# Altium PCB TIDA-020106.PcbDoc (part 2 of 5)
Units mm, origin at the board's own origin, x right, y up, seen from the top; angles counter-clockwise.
Board outline 158.53 x 83.25 mm, 6 copper layers (Top Layer, GND, Power, Sig4, GND (Mid4), Bottom Layer), stack 1.59 mm thick; 407 components, 254 nets, 1274 pads, 2396 vias.
Unrouted connection lines stored in the file: 294.

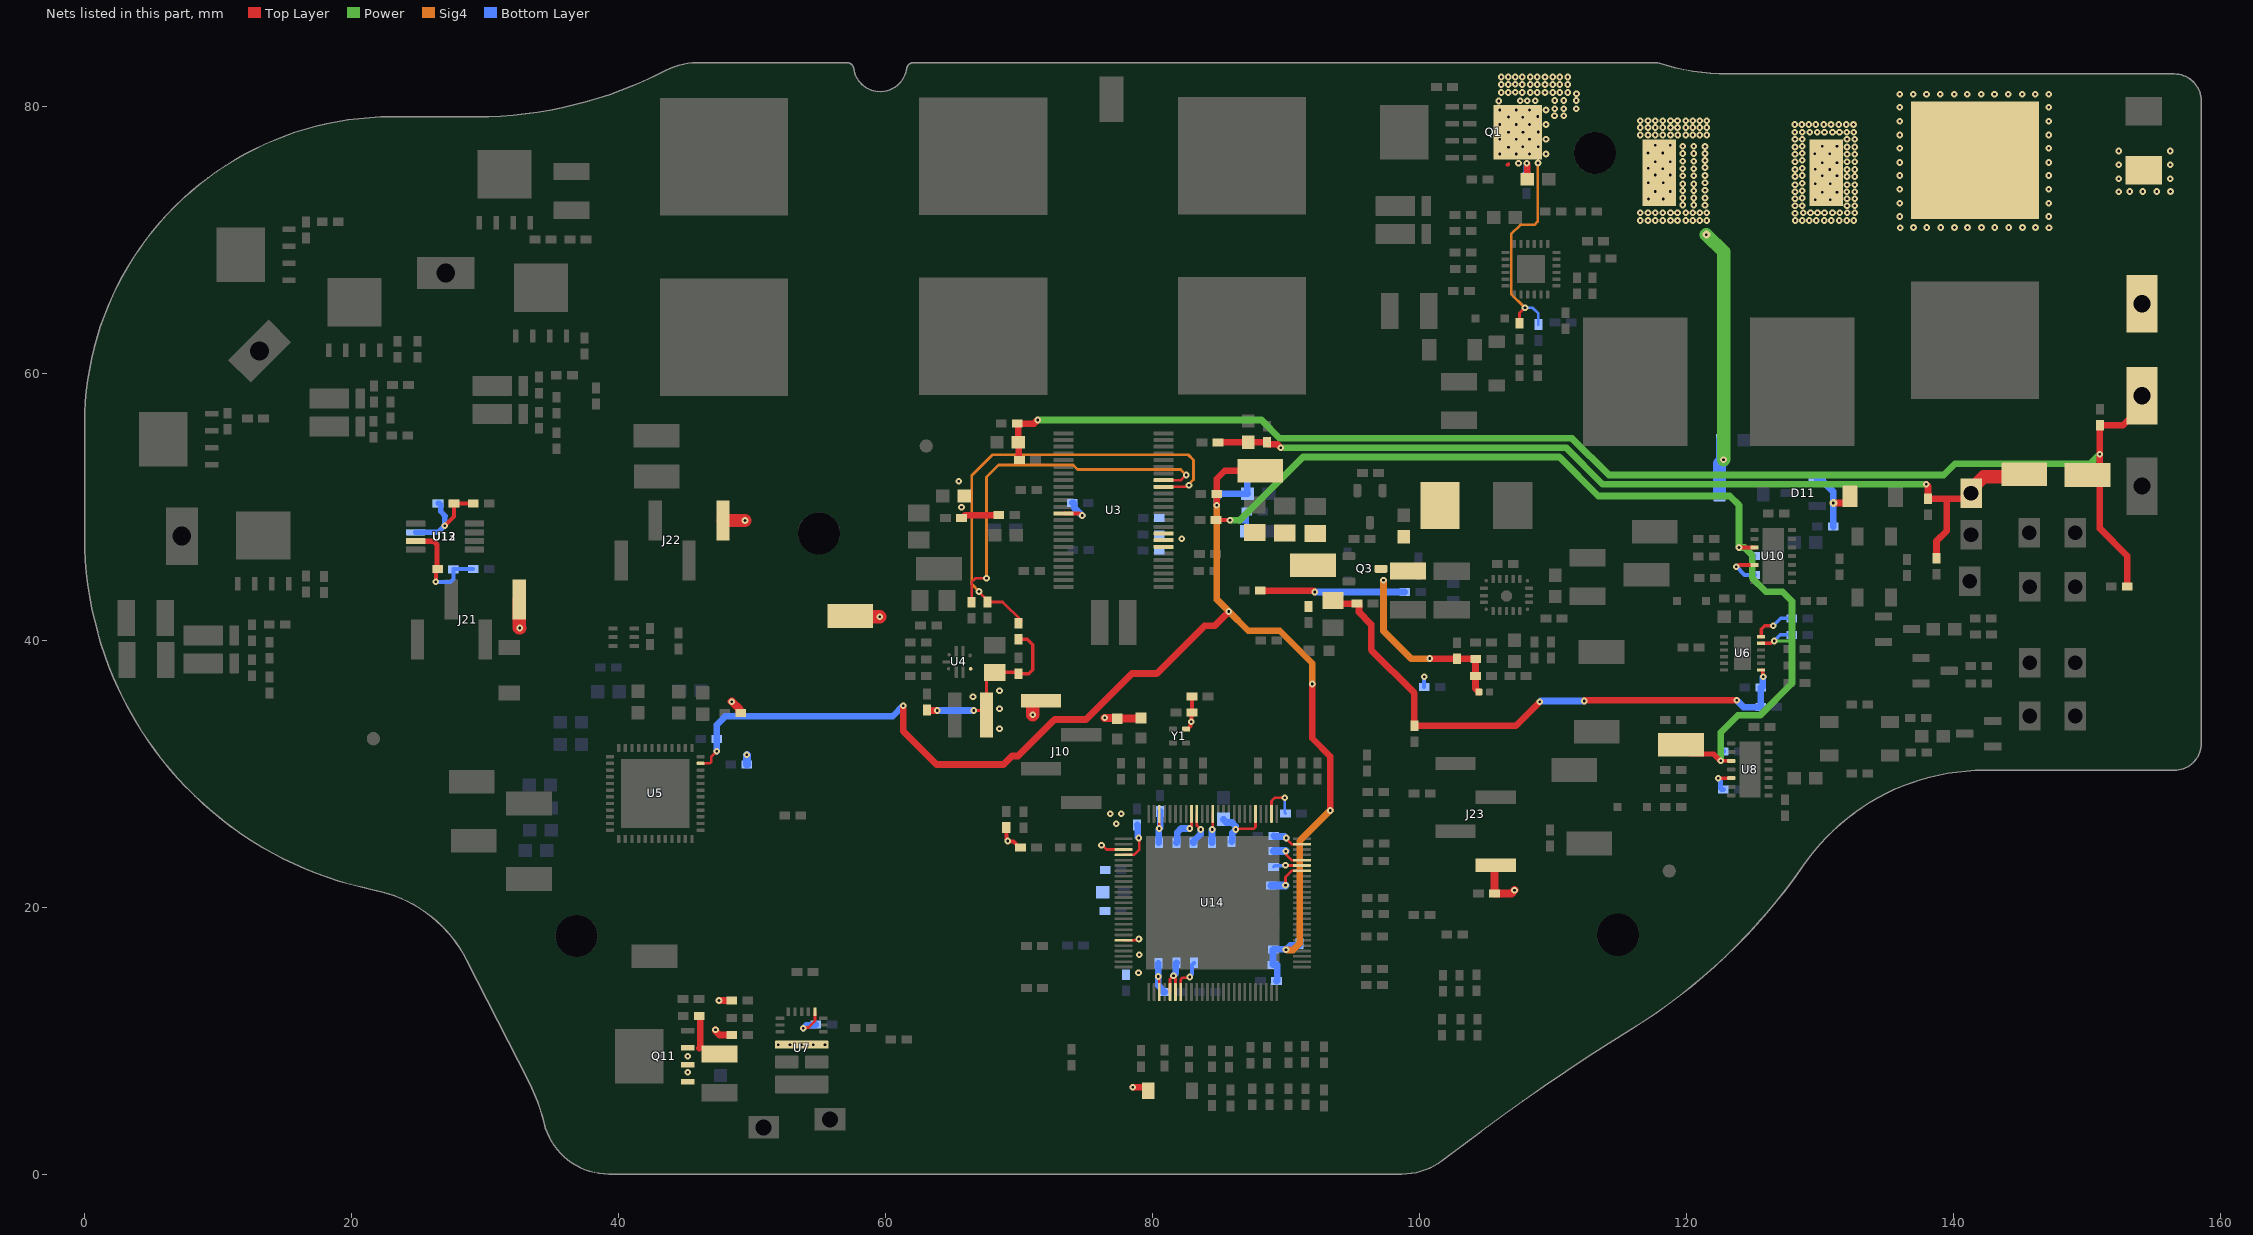
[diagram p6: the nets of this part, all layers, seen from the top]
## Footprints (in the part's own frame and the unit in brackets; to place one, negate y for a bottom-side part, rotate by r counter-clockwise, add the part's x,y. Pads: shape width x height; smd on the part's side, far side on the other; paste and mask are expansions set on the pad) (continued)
RYT0009A-MFG [mm]
  rrect40% 0.875x0.25 smd paste+0 mask+0: 1(-0.763,0.25) 2(-0.763,-0.25) 5(0.763,-0.25) 6(0.763,0.25)
  round 0.255 smd paste+0 mask+0: 3(-0.509,-0.828)
  round 0.278 smd paste+0 mask+0: 4(0.487,-0.787)
  round 0.26 smd paste+0 mask+0: 7(0.537,0.787)
  rrect40% 0.25x0.65 smd paste+0 mask+0: 8(0,0.95)
  round 0.242 smd paste+0 mask+0: 9(-0.509,0.828)
  Top Layer region: -1.2,-0.825 -1.193,-0.85 -1.175,-0.868 -1.15,-0.875 -1.15,-0.875 -0.675,-0.875 -0.656,-0.879 -0.64,-0.89 -0.629,-0.906 -0.625,-0.925 -0.625,-0.925 -0.625,-1.225 -0.618,-1.25 -0.6,-1.268 -0.575,-1.275 -0.575,-1.275 -0.425,-1.275 -0.406,-1.271 -0.39,-1.26 -0.379,-1.244 -0.375,-1.225 -0.375,-1.225 -0.375,-0.912 -0.368,-0.887 -0.35,-0.868 -0.35,-0.868 -0.337,-0.857 -0.328,-0.842 -0.325,-0.825 -0.325,-0.825 -0.325,-0.675 -0.329,-0.656 -0.34,-0.64 -0.356,-0.629 -0.375,-0.625 -0.375,-0.625 -1.15,-0.625 -1.169,-0.629 -1.185,-0.64 -1.196,-0.656 -1.2,-0.675 -1.2,-0.675
  Top Layer region: 1.2,0.825 1.193,0.85 1.175,0.868 1.15,0.875 1.15,0.875 0.675,0.875 0.656,0.879 0.64,0.89 0.629,0.906 0.625,0.925 0.625,0.925 0.625,1.225 0.618,1.25 0.6,1.268 0.575,1.275 0.575,1.275 0.425,1.275 0.406,1.271 0.39,1.26 0.379,1.244 0.375,1.225 0.375,1.225 0.375,0.675 0.379,0.656 0.39,0.64 0.406,0.629 0.425,0.625 0.425,0.625 1.15,0.625 1.169,0.629 1.185,0.64 1.196,0.656 1.2,0.675 1.2,0.675
  Top Layer region: -1.2,0.825 -1.193,0.85 -1.175,0.868 -1.15,0.875 -1.15,0.875 -0.675,0.875 -0.656,0.879 -0.64,0.89 -0.629,0.906 -0.625,0.925 -0.625,0.925 -0.625,1.225 -0.618,1.25 -0.6,1.268 -0.575,1.275 -0.575,1.275 -0.425,1.275 -0.406,1.271 -0.39,1.26 -0.379,1.244 -0.375,1.225 -0.375,1.225 -0.375,0.675 -0.379,0.656 -0.39,0.64 -0.406,0.629 -0.425,0.625 -0.425,0.625 -1.15,0.625 -1.169,0.629 -1.185,0.64 -1.196,0.656 -1.2,0.675 -1.2,0.675
  Top Layer region: 1.2,-0.825 1.193,-0.85 1.175,-0.868 1.15,-0.875 1.15,-0.875 0.675,-0.875 0.656,-0.879 0.64,-0.89 0.629,-0.906 0.625,-0.925 0.625,-0.925 0.625,-1.225 0.618,-1.25 0.6,-1.268 0.575,-1.275 0.575,-1.275 0.425,-1.275 0.406,-1.271 0.39,-1.26 0.379,-1.244 0.375,-1.225 0.375,-1.225 0.375,-0.912 0.372,-0.894 0.363,-0.879 0.35,-0.868 0.35,-0.868 0.337,-0.857 0.328,-0.842 0.325,-0.825 0.325,-0.825 0.325,-0.675 0.329,-0.656 0.34,-0.64 0.356,-0.629 0.375,-0.625 0.375,-0.625 1.15,-0.625 1.169,-0.629 1.185,-0.64 1.196,-0.656 1.2,-0.675 1.2,-0.675
  silkscreen extent -1.92,-1.68 1.05,1.68, body extent -1.3,-1.38 1.3,1.38, height 0.25
RZT0020A-MFG [mm]
  round 0.259 smd paste+0 mask+0: 1(-1.069,1.519) 7(-1.069,-1.569) 11(1.069,-1.569) 17(1.069,1.519)
  rrect40% 0.6x0.25 smd paste+0 mask+0: 2(-1.2,1) 3(-1.2,0.5) 4(-1.2,0) 5(-1.2,-0.5) 6(-1.2,-1) 12(1.2,-1) 13(1.2,-0.5) 14(1.2,0) 15(1.2,0.5) 16(1.2,1)
  rrect40% 0.25x0.6 smd paste+0 mask+0: 8(-0.55,-1.7) 9(-0.05,-1.7) 10(0.5,-1.7) 18(0.5,1.7) 19(-0.05,1.7) 20(-0.55,1.7)
  round 0.855 smd paste-1000 mask+0: 21(-0.075,0)
  Top Layer region: -0.55,1 -0.543,1.025 -0.525,1.043 -0.5,1.05 -0.5,1.05 0.099,1.05 0.124,1.044 0.142,1.026 0.149,1.001 0.149,1.001 0.178,0.897 0.252,0.819 0.354,0.785 0.354,0.785 0.377,0.777 0.394,0.759 0.4,0.735 0.4,0.735 0.4,-0.735 0.394,-0.759 0.377,-0.777 0.354,-0.785 0.354,-0.785 0.252,-0.819 0.178,-0.897 0.149,-1.001 0.149,-1.001 0.142,-1.026 0.124,-1.044 0.099,-1.05 0.099,-1.05 -0.249,-1.05 -0.274,-1.044 -0.292,-1.026 -0.299,-1.001 -0.299,-1.001 -0.328,-0.897 -0.402,-0.819 -0.504,-0.785 -0.504,-0.785 -0.527,-0.777 -0.544,-0.759 -0.55,-0.735 -0.55,-0.735
  Top Layer region: 1.45,1.375 1.469,1.379 1.485,1.39 1.496,1.406 1.5,1.425 1.5,1.425 1.5,1.575 1.496,1.594 1.485,1.61 1.469,1.621 1.45,1.625 1.45,1.625 1.275,1.625 1.237,1.633 1.204,1.654 1.183,1.687 1.175,1.725 1.175,1.725 1.175,1.95 1.171,1.969 1.16,1.985 1.144,1.996 1.125,2 1.125,2 0.975,2 0.956,1.996 0.94,1.985 0.929,1.969 0.925,1.95 0.925,1.95 0.925,1.425 0.929,1.406 0.94,1.39 0.956,1.379 0.975,1.375 0.975,1.375
  Top Layer region: 1.45,-1.375 1.469,-1.379 1.485,-1.39 1.496,-1.406 1.5,-1.425 1.5,-1.425 1.5,-1.575 1.496,-1.594 1.485,-1.61 1.469,-1.621 1.45,-1.625 1.45,-1.625 1.275,-1.625 1.237,-1.633 1.204,-1.654 1.183,-1.687 1.175,-1.725 1.175,-1.725 1.175,-1.95 1.171,-1.969 1.16,-1.985 1.144,-1.996 1.125,-2 1.125,-2 0.975,-2 0.956,-1.996 0.94,-1.985 0.929,-1.969 0.925,-1.95 0.925,-1.95 0.925,-1.425 0.929,-1.406 0.94,-1.39 0.956,-1.379 0.975,-1.375 0.975,-1.375
  Top Layer region: -1.45,-1.375 -1.469,-1.379 -1.485,-1.39 -1.496,-1.406 -1.5,-1.425 -1.5,-1.425 -1.5,-1.575 -1.496,-1.594 -1.485,-1.61 -1.469,-1.621 -1.45,-1.625 -1.45,-1.625 -1.275,-1.625 -1.237,-1.633 -1.204,-1.654 -1.183,-1.687 -1.175,-1.725 -1.175,-1.725 -1.175,-1.95 -1.171,-1.969 -1.16,-1.985 -1.144,-1.996 -1.125,-2 -1.125,-2 -0.975,-2 -0.956,-1.996 -0.94,-1.985 -0.929,-1.969 -0.925,-1.95 -0.925,-1.95 -0.925,-1.425 -0.929,-1.406 -0.94,-1.39 -0.956,-1.379 -0.975,-1.375 -0.975,-1.375
  Top Layer region: -1.45,1.375 -1.469,1.379 -1.485,1.39 -1.496,1.406 -1.5,1.425 -1.5,1.425 -1.5,1.575 -1.493,1.6 -1.475,1.618 -1.45,1.625 -1.45,1.625 -1.275,1.625 -1.237,1.633 -1.204,1.654 -1.183,1.687 -1.175,1.725 -1.175,1.725 -1.175,1.95 -1.168,1.975 -1.15,1.993 -1.125,2 -1.125,2 -0.975,2 -0.956,1.996 -0.94,1.985 -0.929,1.969 -0.925,1.95 -0.925,1.95 -0.925,1.425 -0.929,1.406 -0.94,1.39 -0.956,1.379 -0.975,1.375 -0.975,1.375
  silkscreen extent -2.17,-2.22 1.73,2.22, body extent -1.6,-2.1 1.6,2.1, height 0.25
SMB-Bi [mm] "Molded Diode, 2-Leads, Body 5.4x3.6mm, IPC Medium Density, based on OnSemi component dimensions"
  rect 2.159x2.743 smd: 1(-2.21,0) 2(2.21,0)
  silkscreen extent -3.18,-1.99 3.18,1.99, body extent -2.65,-1.85 2.65,1.85, height 2.26
SOD-123 [mm] "On Semi recommended land pattern"
  rect 0.915x1.22 smd: 1(-1.637,0) 2(1.637,0)
  silkscreen extent -2.74,-1.17 2.03,1.17, body extent -1.93,-0.9 1.93,0.9, height 1.35
SOD-323 [mm] "NXP recommended land pattern"
  rect 0.6x0.6 smd paste-0.05: 1(-1.1,0) 2(1.1,0)
  silkscreen extent -2.06,-0.86 1.53,0.86, body extent -1.3,-0.67 1.3,0.68, height 1.1
SOT-23 [mm] "SOT23, 3-Leads, Body 2.9x1.3mm, Pitch 0.95mm, Lead Span 2.5mm, IPC Medium Density"
  rrect50% 1x0.6 smd: 1(-1.2,0.95) 2(-1.2,-0.95) 3(1.2,0)
  silkscreen extent -1.62,-1.5 0.7,1.5, body extent -1.16,-1.45 1.21,1.45, height 1
Testpoint_Keystone_Miniature [mil] "Miniature SMT test point"
  rect 135x70 smd: 1(0,0)
  silkscreen extent -78,-46 78,45, body extent -52,-20 52,20, height 61
TI_Stacked_Overlay_Small [mm]
  silkscreen extent -10.63,-2.49 10.63,2.49
VAK0015A-MFG [mm]
  rrect40% 0.65x0.25 smd paste+0 mask+0: 1(-1.625,2.375) 2(-1.625,1.875) 3(-1.625,1.375) 8(1.625,1.375) 9(1.625,1.875) 10(1.625,2.375)
  rrect17% 4x0.6 smd paste-1000 mask-1000: 4(0,0.4)
  rrect20% 1.75x1 smd paste-1000 mask-1000: 5(-1.125,-0.9) 7(1.125,-0.9)
  rrect15% 4x1.35 smd paste-1000 mask-1000: 6(0,-2.575)
  rrect40% 0.25x0.65 smd paste+0 mask+0: 11(1,2.875) 12(0.5,2.875) 13(0,2.875) 14(-0.5,2.875) 15(-1,2.875)
  silkscreen extent -2.62,2.25 1.8,3.05, body extent -2.1,-3.35 2.1,3.3, height 0.25
WE-HCM_1390 [mm] "SMD, Body 12.5x13mm"
  rect 2.5x5 smd: 1(-6.25,0) 2(6.25,0)
  silkscreen extent -6.5,-6.75 6.5,6.75, body extent -6.5,-6.75 6.5,6.75, height 9.5
WE-LHMI_7050 [mm] "Wurth"
  rect 2.95x3.5 smd: 1(-2.725,0) 2(2.725,0)
  silkscreen extent -3.55,-3.55 3.55,3.55, body extent -3.8,-3.45 3.8,3.45, height 5
WE-MAPI_3012 [mm] "SMD, 2-Leads, Body 3.2x3.2mm"
  rect 1.3x3.4 smd: 1(-1.05,0) 2(1.05,0)
  silkscreen extent -0.1,-1.6 0.1,1.6, body extent -1.5,-1.5 1.5,1.5, height 1.2
WEEE_Minimum [mm] "WEEElie bin"
  silkscreen extent -2.42,-4.38 2.52,2.65
Wurth_61000418221 [mm] "Header, 2.54mm, 4x1, SMT"
  rect 3x1 smd: 1(-1.5,3.81) 2(1.5,1.27) 3(-1.5,-1.27) 4(1.5,-3.81)
  silkscreen extent -1.27,-5.08 1.27,5.4, body extent -2.5,-5.08 2.5,5.08, height 9.29

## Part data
C1 C2 C13 C35 C41 C55 C59 C66 C70 C71 C81 C82 C84 C85 C86 C87 C88 C90 C94 C118 C120 C148: library part CMP-0860997-1, "CAP, CERM, 1000 pF, 50 V,+/- 10%, X8R, AEC-Q200 Grade 0, 0402", Cap_Case=0402, Manufacturer=TDK, TempCo=X8R, Tolerance_%=10%, Value2=50V, ValueDisplayed=1000pF
C3 C4 C11 C15 C17 C20 C34 C36 C37 C38 C39 C42 C43 C44 C45 C46 C47 C58 C83 C89 C91 C92 C93 C98 C99 C100 C101 C103 C105 C107 C109 C110 C111 C112 C113 C114 C121 C122 C125 C126 C127 C128 C129 C130 C131 C132 C139 C140 C141 C142 C143 C144 C145 C146 C147: library part CMP-0006356-2, "CAP, CERM, 0.1 uF, 50 V, +/- 10%, X7R, AEC-Q200 Grade 1, 0402", Cap_Case=0402, Manufacturer=MuRata, Supplier Part Number 1=490-10672-1-ND, TempCo=X7R, Tolerance_%=10%, Value1=Unknown, Value2=50V, ValueDisplayed=0.1uF
C5 C6 C21 C22 C25 C61 C75 C76 C96: library part CMP-0009182-2, "CAP, CERM, 4.7 uF, 100 V, +/- 10%, X7S, 1210", Cap_Case=1210, Manufacturer=MuRata, Supplier Part Number 1=81-GRM32DC72A475KE1L, TempCo=X7S, Tolerance_%=10%, Value1=Unknown, Value2=100V, ValueDisplayed=4.7uF
C7 C9 C10 C23 C24 C26 C97 C102 C106: library part CMP-0860999-1, "CAP, CERM, 0.1 µF, 100 V,+/- 10%, X8L, AEC-Q200 Grade 0, 0603", Cap_Case=0603, Manufacturer=MuRata, TempCo=X8L, Tolerance_%=10%, Value2=100V, ValueDisplayed=0.1µF
C8 C60 C73 C74: library part CMP-0011277-1, "CAP, AL, 330 uF, 100 V, +/- 20%, SMD", Cap_Case=MN0, Manufacturer=Chemi-Con, Tolerance_%=20%, Value1=Unknown, Value2=100V, ValueDisplayed=330uF
C12 C16 C68: library part CMP-0008815-2, "CAP, CERM, 1 uF, 100 V, +/- 10%, X7R, AEC-Q200 Grade 1, 1206", Cap_Case=1206, Manufacturer=MuRata, Supplier Part Number 1=GCM31CR72A105KA03L-ND, TempCo=X7R, Tolerance_%=10%, Value1=Unknown, Value2=100V, ValueDisplayed=1uF
C14 C18: library part CMP-0006333-1, "CAP, CERM, 0.01 uF, 100 V, +/- 10%, X7S, AEC-Q200 Grade 1, 0402", Cap_Case=0402, Manufacturer=TDK, Supplier Part Number 1=445-6910-1-ND, TempCo=X7S, Tolerance_%=10%, Value1="0.410191 ohm", Value2=100V, ValueDisplayed=0.01uF
C19: library part CMP-0006331-2, "CAP, CERM, 0.068 uF, 50 V, +/- 10%, X7R, AEC-Q200 Grade 1, 0402", Cap_Case=0402, Manufacturer=TDK, Supplier Part Number 1=445-6898-1-ND, TempCo=X7R, Tolerance_%=10%, Value1="0.05606 ohm", Value2=50V, ValueDisplayed=0.068uF
C27 C31 C32 C33 C40 C56 C57: library part CMP-0008305-2, "CAP, CERM, 22 uF, 25 V, +/- 20%, X5R, 0805", Cap_Case=0805, Manufacturer=MuRata, Supplier Part Number 1=490-10749-1-ND, TempCo=X5R, Tolerance_%=20%, Value1=Unknown, Value2=25V, ValueDisplayed=22uF
C28: library part CMP-0011274-1, "CAP, AL, 100 uF, 100 V, +/- 20%, SMD", Cap_Case=LH0, Manufacturer=Chemi-Con, Tolerance_%=20%, Value1=Unknown, Value2=100V, ValueDisplayed=100uF
C29 C63 C64 C65 C67 C69 C72 C77: library part CMP-0123897-1, "Auto Grade Capacitor, 0603, X7R, 25V, 1uF, ±10%", Digikey Part Number=2679-AGC0603X7R250-105KXPTR-ND, Manufacturer=Venkel, Operating Temperature Range="-55°C to +125°C", TempCo=15%, Temperature Characteristic=X7R, Tolerance_%=10%, ValueDisplayed=1uF
C30: library part CMP-0122034-1, "10 pF ±10% 50V Ceramic Capacitor X7R 0402 (1005 Metric)", Digikey Part Number=399-C0402C100K5RAC7867CT-ND, Manufacturer=KEMET, Operating Temperature Range="-55°C to +125°C", TempCo=15%, Temperature Characteristic=X7R, Tolerance_%=10%, ValueDisplayed=10pF
C48 C49 C50 C51 C52 C123 C124: library part CMP-0007497-1, "CAP, CERM, 10 uF, 10 V, +/- 20%, X7R, 0603", Cap_Case=0603, Manufacturer=MuRata, Supplier Part Number 1=81-GRM188Z71A106MA3D, TempCo=X7R, Tolerance_%=20%, Value1=Unknown, Value2=10V, ValueDisplayed=10uF
C53: library part CMP-0084284-1, "CAP, CERM, 2.2 µF, 10 V,+/- 10%, X7R, AEC-Q200 Grade 1, 0603", Cap_Case=0603, Manufacturer=MuRata, TempCo=X7R, Tolerance_%=10%, Value2=10V, ValueDisplayed=2.2µF
C54 C116 C117: library part CMP-0007498-2, "CAP, CERM, 4.7 uF, 10 V, +/- 20%, X7R, 0603", Cap_Case=0603, Manufacturer=MuRata, TempCo=X7R, Tolerance_%=20%, Value1=Unknown, Value2=10V, ValueDisplayed=4.7uF
C62: library part CMP-0007007-3, "CAP, CERM, 10 uF, 25 V, +/- 20%, X5R, 0603", Cap_Case=0603, Manufacturer=TDK, PartNumber=C1608X5R1E106M080AC, Supplier Part Number 1=445-9015-1-ND, TempCo=X5R, Tolerance_%=20%, Value1="0.004639 ohm", Value2=25V, ValueDisplayed=10uF
C78 C79 C80: library part CMP-0860801-1, "CAP, CERM, 470 pF, 50 V,+/- 10%, X7R, AEC-Q200 Grade 1, 0402", Cap_Case=0402, Manufacturer=MuRata, TempCo=X7R, Tolerance_%=10%, Value2=50V, ValueDisplayed=470pF
C95: library part CMP-0007095-1, "CAP, CERM, 0.33 uF, 50 V, +/- 10%, X7R, AEC-Q200 Grade 1, 0603", Cap_Case=0603, Manufacturer=TDK, Supplier Part Number 1=445-174426-1-ND, TempCo=X7R, Tolerance_%=10%, Value1="0.01584 ohm", Value2=50V, ValueDisplayed=0.33uF
C104 C108: library part CMP-0079247-1, "CAP, CERM, 4700 pF, 100 V,+/- 10%, X7R, AEC-Q200 Grade 1, 0603", Cap_Case=0603, Manufacturer=MuRata, Supplier Part Number 1=490-4930-1-ND, TempCo=X7R, Tolerance_%=10%, Value2=100V, ValueDisplayed=4700pF
C133 C134 C135 C136 C137 C138: library part CMP-0081010-1, "CAP, CERM, 2.2 µF, 25 V,+/- 20%, X5R, 0402", Cap_Case=0402, Manufacturer=MuRata, Supplier Part Number 1=490-10457-1-ND, TempCo=X5R, Tolerance_%=20%, Value2=25V, ValueDisplayed=2.2µF
D1: library part CMP-0006055-3, "Diode, TVS, Bi, 51 V, 82.4 Vc, SMB", Manufacturer=Bourns, Value1=600W
D2 D6 D7: library part CMP-0079597-2, "Diode, Switching, 75 V, 0.15 A, AEC-Q101, SOD-323", Manufacturer="Diodes Inc.", Value1=0.15A, Value2=1.25V
D3 D12: library part CMP-0080760-2, "Diode, Schottky, 100 V, 0.15 A, AEC-Q101, SOD-123", Manufacturer=Vishay-Semiconductor, Value1=0.15A, Value2=1V
D4: library part CMP-0078478-1, "LED, Green, SMD", Color=Green, Manufacturer=Lite-On, Power_TotalModule=75mW, Supplier Part Number 1=160-1446-1-ND, Value1=0.075W, Value2=2V
D5: library part CMP-0125988-1, "Automotive, dual, 3-pF, ±24-V, ±30-kV ESD protection diode for in-vehicle networks 3-SOT-23 -55 to 150", Breakdown Voltage=25.5V, Clamping Voltage=37V, Digikey Part Number=296-ESD2CAN24DBZRQ1CT-ND, Manufacturer="Texas Instruments", Mouser Part Number=595-ESD2CAN24DBZRQ1, Operating Temperature Range="-55°C to +150°C", ValueDisplayed=3pF
D8: library part CMP-0002891-1, "LED, Green, SMD", Color=green, Manufacturer=Lite-On, Supplier Part Number 1=160-1888-1-ND, Value1=W, Value2=3.2V
D9: library part CMP-0002950-1, "LED, Red, SMD", Color=Red, Manufacturer=Lite-On, Power_TotalModule=75mW, Supplier Part Number 1=160-1447-1-ND, Value1=0.075W, Value2=2V
D10: library part CMP-0128583-1, "Zener Diode Single 62V 5% 185Ohm 500mW 2-Pin SOD-123 T/R", Digikey Part Number=MMSZ5265B-TP-ND, Manufacturer=MCC, Max Reverse Leakage Current=0.1uA, Mouser Part Number=833-MMSZ5265B-TP, Operating Temperature Range="-65°C to +150°C", Power_W=500mW
D11: library part CMP-0126395-1, "Zener Diode 27 V 250 mW ±5% Surface Mount SOT-23-3", Digikey Part Number=296-BZX84C27VDBZRCT-ND, Manufacturer="Texas Instruments", Max Reverse Leakage Current=0.03uA, Mouser Part Number=595-BZX84C27VDBZR, Operating Temperature Range="-55°C to +150°C", Power_W=250mW
D13: library part CMP-0005829-3, "Diode, Zener, 10 V, 200 mW, SOD-323", Manufacturer="Diodes Inc.", Power_W=200mW, Value1=0.2W
FID1 FID2 FID3: library part CMP-0077181-1, "Fiducial mark.  There is nothing to buy or mount.", Manufacturer=N/A
J10 J21 J22 J23: library part CMP-0054788-1, "Header, 2.54mm, 4x1, Gold, SMT", Color=Black, Manufacturer="Wurth Elektronik", Supplier Part Number 1=732-5365-ND
L1: library part CMP-0063911-1, "Inductor, Shielded Drum Core, Ferrite, 250 nH, 50 A, 0.000165 ohm, SMD", Manufacturer="Wurth Elektronik", Supplier Part Number 1=732-3005-1-ND, Value1="0.000165 ohm", Value2=50A, ValueDisplayed=250nH
L2: library part CMP-0064107-1, "Inductor, Shielded Drum Core, Powdered Iron, 3.3 uH, 6 A, 0.019 ohm, SMD", Manufacturer="Wurth Elektronik", Supplier Part Number 1=732-3353-1-ND, Value1="0.019 ohm", Value2=6A, ValueDisplayed=3.3uH
L3: library part CMP-0084500-1, "Inductor, Shielded, Metal Composite, 2.2 µH, 1.8 A, 0.115 ohm, SMD", Manufacturer="Wurth Elektronik", Value1="0.115 ohm", Value2=1.8A, ValueDisplayed=2.2µH
L4: library part CMP-0090842-1, "Power Inductor, shielded, composite, 1uH 20% tol, DCR 7.2mOhms, SRF 65MHz, Isat 4.8A, Irms 13A, AEC-Q200", Manufacturer=Coilcraft, Operating Temperature Range="to +165°C", Self Resonant Frequency=65MHz, Test Frequency=1MHz, Tolerance_%=20%
L5 L6: library part CMP-0062430-2, "Inductor, Ferrite, 100 uH, 0.15 A, 2 ohm, SMD", Manufacturer=TDK, Supplier Part Number 1=445-3959-1-ND, Value1="2 ohm", Value2=0.15A, ValueDisplayed=100uH
L7 L8 L10: library part CMP-0003235-1, "Ferrite Bead, 100 ohm @ 100 MHz, 1.2 A, 0402", Manufacturer="Wurth Elektronik", Supplier Part Number 1=732-2362-1-ND, Value1="0.09 ohm", Value2=1.2A, ValueDisplayed="100 ohm"
LBL1: library part CMP-0003625-1, "Thermal Transfer Printable Labels, 0.650\" W x 0.200\" H - 10,000 per roll", Manufacturer=Brady, Supplier Part Number 1=97C5133
Logo1: library part CMP-0074844-1
Logo2: library part CMP-0074838-1, "Texas Instrument Corporate Signature"
Logo3: library part CMP-0074847-1, "FCC_disclaimer"
Logo4: library part CMP-0074769-1
LOGO5: library part CMP-0074837-1, "IEC 61010-1 Hot Surface Warning"
LOGO6: library part CMP-0074835-1, "IEC 61010-1 High Voltage Warning"
MP1 MP2 MP3 MP4: library part CMP-0125643-1, "M3 Pan Head Machine Screw Slotted Drive Nylon", Digikey Part Number=36-29344-ND, Manufacturer="Keystone Electronics", Mouser Part Number=534-29344, Operating Temperature Range=to
Q1 Q2 Q4 Q5 Q7 Q8 Q9 Q10 Q11: library part CMP-0086155-1, "MOSFET, N-CH, 80 V, 60 A, AEC-Q101, PowerPAK_SO-8L", Alternate Manufacturer=None, Manufacturer=Vishay-Siliconix, Value1="? ohm", Value2="36 nC"
Q3: library part CMP-0000613-1, "MOSFET, N-CH, 30 V, 4 A, AEC-Q101, SOT-23", Alternate Manufacturer=None, Manufacturer="Diodes Inc.", Supplier Part Number 1=DMN3053L-7DICT-ND, Value1=0, Value2="7.3 nC"
Q6: library part CMP-0049400-1, "Trans Digital BJT NPN/PNP 50V 100mA 250mW 6-Pin SOT-363 T/R", Collector Base Voltage=50V, Digikey Part Number=BCR22PNH6327XTSA1CT-ND, Manufacturer=Infineon, Mouser Part Number=726-BCR22PNH6327XTSA, Operating Temperature Range="to +150°C", Power_W=250mW, Unity Gain Freq=130MHz
Q12: library part CMP-0001041-2, "MOSFET, N-CH, 100 V, 0.7 A, AEC-Q101, SOT-23", Alternate Manufacturer=None, Manufacturer="Diodes Inc.", Supplier Part Number 1=ZXMN10A07FCT-ND, Value2="2.9 nC"
R1 R2 R12 R13 R21 R27 R31 R32 R33 R48 R52 R56 R69 R70 R74 R75 R87 R120 R122 R124 R126 R155: library part CMP-0025950-3, "RES, 100 k, 1%, 0.063 W, AEC-Q200 Grade 0, 0402", Manufacturer=Vishay-Dale, Power_W=63mW, Supplier Part Number 1=541-100KLCT-ND, TempCo="100 ppm/C", Tolerance_%=1%, Value2=0.063W, Value_Code=100k
R3 R4: library part CMP-0026510-2, "RES, 69.8 k, 1%, 0.063 W, AEC-Q200 Grade 0, 0402", Manufacturer=Vishay-Dale, Power_W=63mW, Supplier Part Number 1=541-69.8KLCT-ND, TempCo="100 ppm/C", Tolerance_%=1%, Value2=0.063W, Value_Code=69k8, ValueDisplayed=69.8k
R5 R6 R15 R62 R91 R92 R102 R104 R112 R114 R130 R136 R147 R148 R149 R150 R153 R156: library part CMP-0025958-3, "RES, 10.0 k, 1%, 0.063 W, AEC-Q200 Grade 0, 0402", Manufacturer=Vishay-Dale, Power_W=63mW, Supplier Part Number 1=541-10.0KLCT-ND, TempCo="100 ppm/C", Tolerance_%=1%, Value2=0.063W, Value_Code=10k0, ValueDisplayed=10.0k
R7: library part CMP-0123675-1, "1 mOhms ±1% 7W Chip Resistor Wide 1612 (3831 Metric), 1216 Current Sense, Moisture Resistant", Digikey Part Number=4423-BVN-M-R001-1.0CT-ND, Manufacturer=Isabellenhuette, Operating Temperature Range="-65°C to +170°C", Power_W=7W, TempCo=50ppm/°C, Tolerance_%=1%
R8 R9 R22 R23 R25 R29 R30 R37 R38 R39 R40 R41 R45 R49 R50 R51 R53 R54 R55 R57 R58 R66 R67 R72 R73 R97 R98 R99 R105 R109 R115 R128 R129 R144 R145 R146: library part CMP-0026822-3, "RES, 0, 5%, 0.063 W, AEC-Q200 Grade 0, 0402", Manufacturer=Vishay-Dale, Power_W=63mW, Supplier Part Number 1=541-0.0JCT-ND, TempCo="200 ppm/C", Tolerance_%=5%, Value2=0.063W, Value_Code=0000, ValueDisplayed=0
R10 R17 R19 R24 R26 R28 R36 R95 R119 R121 R123 R125 R131 R134 R151 R152 R154: library part CMP-0026071-3, "RES, 1.00 k, 1%, 0.063 W, AEC-Q200 Grade 0, 0402", Manufacturer=Vishay-Dale, Power_W=63mW, Supplier Part Number 1=541-1.00KLCT-ND, TempCo="100 ppm/C", Tolerance_%=1%, Value2=0.063W, Value_Code=1k00, ValueDisplayed=1.00k
R11: library part CMP-0025948-2, "RES, 50, 1%, 0.125 W, AEC-Q200 Grade 1, 0402", Manufacturer="AT Ceramics", Power_W=125mW, Supplier Part Number 1=1284-1326-1-ND, TempCo="150 ppm/C", Tolerance_%=1%, Value2=0.125W, Value_Code=50R0, ValueDisplayed=50
R14: library part CMP-0026094-3, "RES, 1.74 k, 1%, 0.063 W, AEC-Q200 Grade 0, 0402", Manufacturer=Vishay-Dale, Power_W=63mW, Supplier Part Number 1=541-1.74KLCT-ND, TempCo="100 ppm/C", Tolerance_%=1%, Value2=0.063W, Value_Code=1k74, ValueDisplayed=1.74k
R16 R43 R84 R138 R139: library part CMP-0025951-3, "RES, 100, 1%, 0.063 W, AEC-Q200 Grade 0, 0402", Manufacturer=Vishay-Dale, Power_W=63mW, Supplier Part Number 1=541-100LCT-ND, TempCo="100 ppm/C", Tolerance_%=1%, Value2=0.063W, Value_Code=100R, ValueDisplayed=100
R18: library part CMP-0026555-2, "RES, 7.50 k, 1%, 0.063 W, AEC-Q200 Grade 0, 0402", Manufacturer=Vishay-Dale, Power_W=63mW, Supplier Part Number 1=541-7.50KLCT-ND, TempCo="100 ppm/C", Tolerance_%=1%, Value2=0.063W, Value_Code=7k50, ValueDisplayed=7.50k
R20: library part CMP-0026207-2, "RES, 26.1 k, 1%, 0.063 W, AEC-Q200 Grade 0, 0402", Manufacturer=Vishay-Dale, Power_W=63mW, Supplier Part Number 1=541-26.1KLCT-ND, TempCo="100 ppm/C", Tolerance_%=1%, Value2=0.063W, Value_Code=26k1, ValueDisplayed=26.1k
R34 R35: library part CMP-0026553-2, "RES, 7.15 k, 1%, 0.063 W, AEC-Q200 Grade 0, 0402", Manufacturer=Vishay-Dale, Power_W=63mW, Supplier Part Number 1=541-7.15KLCT-ND, TempCo="100 ppm/C", Tolerance_%=1%, Value2=0.063W, Value_Code=7k15, ValueDisplayed=7.15k
R42 R59 R89 R93 R94 R96 R101 R106 R107 R108 R111 R116 R117 R118 R133 R135 R137 R140 R141 R142 R143: library part CMP-0026908-3, "RES, 33, 5%, 0.063 W, AEC-Q200 Grade 0, 0402", Manufacturer=Vishay-Dale, Power_W=63mW, Supplier Part Number 1=541-33JCT-ND, TempCo="200 ppm/C", Tolerance_%=5%, Value2=0.063W, Value_Code=33R0, ValueDisplayed=33
R44: library part CMP-0026040-3, "RES, 16.2 k, 1%, 0.063 W, AEC-Q200 Grade 0, 0402", Manufacturer=Vishay-Dale, Power_W=63mW, Supplier Part Number 1=541-16.2KLCT-ND, TempCo="100 ppm/C", Tolerance_%=1%, Value2=0.063W, Value_Code=16k2, ValueDisplayed=16.2k
R46: library part CMP-0025956-3, "RES, 107 k, 1%, 0.063 W, AEC-Q200 Grade 0, 0402", Manufacturer=Vishay-Dale, Power_W=63mW, Supplier Part Number 1=541-107KLCT-ND, TempCo="100 ppm/C", Tolerance_%=1%, Value2=0.063W, Value_Code=107k
R47: library part CMP-0026027-3, "RES, 15.0 k, 1%, 0.063 W, AEC-Q200 Grade 0, 0402", Manufacturer=Vishay-Dale, Power_W=63mW, Supplier Part Number 1=541-15.0KLCT-ND, TempCo="100 ppm/C", Tolerance_%=1%, Value2=0.063W, Value_Code=15k0, ValueDisplayed=15.0k
R60 R63 R78 R79 R82 R83 R85 R86 R88 R90: library part CMP-0025963-3, "RES, 10.0, 1%, 0.063 W, AEC-Q200 Grade 0, 0402", Manufacturer=Vishay-Dale, Power_W=63mW, Supplier Part Number 1=541-10.0LCT-ND, TempCo="100 ppm/C", Tolerance_%=1%, Value2=0.063W, Value_Code=10R0, ValueDisplayed=10.0
R61 R80 R81: library part CMP-0126683-1, "0.5 mOhms ±1% 9W Chip Resistor Wide 1612 (3831 Metric), 1216 Current Sense, Moisture Resistant", Digikey Part Number=4423-BVN-Z-R0005-1.0CT-ND, Manufacturer=Isabellenhuette, Operating Temperature Range="-65°C to +170°C", Power_W=9W, TempCo=50ppm/°C, Tolerance_%=1%
R64 R65 R68: library part CMP-0078498-1, "RES, 3.00, 1%, 0.1 W, AEC-Q200 Grade 0, 0603", Manufacturer=Rohm, Power_W=100mW, Supplier Part Number 1=RHM3AYCT-ND, TempCo="100 ppm/C", Tolerance_%=1%, Value2=0.1W, Value_Code=3R00, ValueDisplayed=3.00
R71 R76 R77: library part CMP-0026035-3, "RES, 162, 1%, 0.063 W, AEC-Q200 Grade 0, 0402", Manufacturer=Vishay-Dale, Power_W=63mW, Supplier Part Number 1=541-162LCT-ND, TempCo="100 ppm/C", Tolerance_%=1%, Value2=0.063W, Value_Code=162R, ValueDisplayed=162
R100 R103 R110 R113: library part CMP-0026487-2, "RES, 60.4, 1%, 0.063 W, AEC-Q200 Grade 0, 0402", Manufacturer=Vishay-Dale, Power_W=63mW, Supplier Part Number 1=541-60.4LCT-ND, TempCo="100 ppm/C", Tolerance_%=1%, Value2=0.063W, Value_Code=60R4, ValueDisplayed=60.4
TP1 TP2 TP3 TP4 TP5 TP6 TP7 TP8 TP9 TP10 TP11 TP12 TP13 TP14 TP15 TP17 TP18 TP19 TP22 TP23: library part CMP-0055152-1, "Test Point, Miniature, SMT", Manufacturer=Keystone, Supplier Part Number 1=36-5015TR-ND
TP16: library part CMP-0055152-2, "Test Point, Miniature, SMT", Manufacturer="Keystone Electronics", Supplier Part Number 1=36-5015TR-ND
U1: library part CMP-0021701-1, "Ideal Diode Surge Stopper with Circuit breaker, overvoltage protection and fault output", Manufacturer="Texas Instruments", Max Supply Voltage=65V, Min Supply Voltage=3V, Nominal Supply Current=650-700uA, Operating Temperature Range="-40°C to +150°C"
U2: library part CMP-0096221-1, "3.5V to 65V Synchronous Step-Down Voltage Regulator", Manufacturer="Texas Instruments", Operating Temperature Range=to
U3: library part CMP-0095884-2, "Power Management IC For Safety-Relevant Applications HTSSOP48 5 Outputs 4 LDO and 1 Synchronous Buck-Boost Regulator", Manufacturer="Texas Instruments", Max Supply Voltage=28V, Min Supply Voltage=2.3V, Operating Temperature Range="-40°C to +150°C"
U4: library part CMP-0121948-1, "3-V to 18-V, 2-A, Automotive Low IQ Buck Converter with +165°C TJ", Digikey Part Number=296-TPS62902QRYTRQ1CT-ND, Manufacturer="Texas Instruments", Max Supply Voltage=18V, Min Supply Voltage=3V, Mouser Part Number=595-TPS62902QRYTRQ1, Nominal Supply Current=8mA, Operating Temperature Range="-40°C to +165°C", Output Voltage=0.4-5.5V, Switching Frequency=1/2.5MHz
U5: library part CMP-0127481-1, Manufacturer="Texas Instruments", Operating Temperature Range=to
U6: library part CMP-0123269-1, Manufacturer="Texas Instruments", Operating Temperature Range=to
U7: library part CMP-0121932-1, "Automotive 65-V H-Bridge Driver with Integrated Current Sense and Diagnostics", Manufacturer="Texas Instruments", Max Supply Voltage=65V, Min Supply Voltage=3V, Nominal Supply Current=3mA, Operating Temperature Range="-40°C to +150°C", Switching Frequency=0-100kHz
U8 U10: library part CMP-0013353-2, "Fault Protected CAN Transceiver with CAN FD, DMT0014A (VSON-14)", Alternate Manufacturer="Texas Instruments", Alternate PartNumber=TCAN1043HGDMTQ1
U9 U11: library part CMP-0127962-1, "Automotive 2-Channel, 48V ESD Protection Diode for In-Vehicle Networks", Breakdown Voltage=52V, Clamping Voltage=64V, Manufacturer="Texas Instruments", Operating Temperature Range="-55°C to +150°C", ValueDisplayed=1.9pF
U12 U13: library part CMP-0095386-1, "Hall Effect Magnetic Sensor VSSOP8", Manufacturer="Texas Instruments", Max Supply Voltage=5.5V, Min Supply Voltage=2.7V, Operating Temperature Range="-40°C to +150°C"
U14: library part CMP-0128482-1, "Real-Time Microcontrollers", Frequency_Fixed=200MHz, Manufacturer="Texas Instruments", Max Supply Voltage=3.63V, Min Supply Voltage=1.19V, Operating Temperature Range="-40°C to +125°C"
Y1: library part CMP-0128115-1, "Automotive, low-power, low-ppm, bulk-acoustic-wave (BAW), fixed-frequency LVCMOS oscillator 4-VSON -40 to 125", Digikey Part Number=296-CDC6C025000ADLYRQ1CT-ND, Frequency Stability=25ppm, Frequency_Fixed=25MHz, Load Capacitance=30pF, Manufacturer="Texas Instruments", Max Supply Voltage=3.63V, Min Supply Voltage=1.62V, Operating Temperature Range="-40°C to +125°C"

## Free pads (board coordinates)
  round 0.006 on Bottom Overlay: 1(0,47.752) 1(0,47.752) 1(0,47.628) 1(0,47.628) 1(0,47.753) 1(0,47.753) 1(0,47.752) 1(0,47.752) 1(0,56.202) 1(0,56.202) 1(0,56.226) 1(0,56.226) 1(12.197,39.576) 1(12.197,39.576) 1(12.197,39.576) 1(12.197,39.576) 1(21.501,47.871) 1(21.501,47.871) 1(21.501,47.871) 1(21.501,47.871) 1(21.501,47.871) 1(21.501,47.871) 1(21.501,47.871) 1(21.501,47.871) 1(21.686,21.28) 1(21.686,21.28) 1(21.686,21.28) 1(21.686,21.28) 1(23,79.202) 1(23,79.202) 1(23,79.202) 1(23,79.202) 1(26.556,21.055) 1(26.556,21.055) 1(26.556,21.055) 1(26.556,21.055) 1(28.628,16.015) 1(28.628,16.015) 1(28.628,16.015) 1(28.628,16.015) 1(28.996,15.291) 1(28.996,15.291) 1(28.996,15.291) 1(28.996,15.291) 1(29.333,79.202) 1(29.333,79.202) 1(29.334,79.202) 1(29.334,79.202) 1(32.498,47.632) 1(32.498,47.632) 1(32.498,47.632) 1(32.498,47.632) 1(32.498,47.632) 1(32.498,47.632) 1(32.498,47.632) 1(32.498,47.632) 1(33.252,6.937) 1(33.252,6.937) 1(33.253,6.938) 1(33.253,6.938) 1(34.412,3.814) 1(34.412,3.814) 1(34.412,3.814) 1(34.412,3.814) 1(39.269,0) 1(39.269,0) 1(39.269,0) 1(39.269,0) 1(43.558,82.687) 1(43.558,82.687) 1(43.558,82.687) 1(43.558,82.687) 1(45.87,83.254) 1(45.87,83.254) 1(45.87,83.254) 1(45.87,83.254) 1(57.109,83.254) 1(57.109,83.254) 1(57.109,83.254) 1(57.109,83.254) 1(57.605,82.82) 1(57.605,82.82) 1(57.605,82.82) 1(57.605,82.82) 1(59.587,81.087) 1(59.587,81.087) 1(59.587,81.087) 1(59.587,81.087) 1(61.569,82.82) 1(61.569,82.82) 1(61.569,82.82) 1(61.569,82.82) 1(62.064,83.254) 1(62.064,83.254) 1(62.064,83.254) 1(62.064,83.254) 1(67.509,7.773) 1(67.509,7.773) 1(67.509,7.773) 1(67.509,7.773) 1(98.671,0) 1(98.671,0) 1(98.671,0) 1(98.671,0) 1(101.668,0.997) 1(101.668,0.997) 1(101.668,0.997) 1(101.668,0.997) 1(108.509,9.308) 1(108.509,9.308) 1(108.509,9.308) 1(108.509,9.308) 1(115.806,10.827) 1(115.806,10.827) 1(115.806,10.827) 1(115.806,10.827) 1(117.835,83.254) 1(117.835,83.254) 1(117.835,83.254) 1(117.835,83.254) 1(123.124,82.41) 1(123.124,82.41) 1(123.124,82.41) 1(123.124,82.41) 1(128.731,23.117) 1(128.731,23.117) 1(128.731,23.117) 1(128.731,23.117) 1(136,29.103) 1(136,29.103) 1(142.315,30.252) 1(142.315,30.252) 1(142.315,30.252) 1(142.315,30.252) 1(148,82.403) 1(148,82.403) 1(156.533,30.252) 1(156.533,30.252) 1(156.533,30.252) 1(156.533,30.252) 1(156.533,82.41) 1(156.533,82.41) 1(156.533,82.41) 1(156.533,82.41) 1(158.533,32.252) 1(158.533,32.252) 1(158.533,32.252) 1(158.533,32.252) 1(158.533,80.41) 1(158.533,80.41) 1(158.533,80.41) 1(158.533,80.41)

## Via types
v1: diameter 0.5, hole 0.2, Top Layer to Bottom Layer, 2306 vias
v2: diameter 0.5, hole 0.2, Top Layer to Bottom Layer, tented both sides, 87 vias
v3: diameter 0.6, hole 0.2, Top Layer to Bottom Layer, 3 vias

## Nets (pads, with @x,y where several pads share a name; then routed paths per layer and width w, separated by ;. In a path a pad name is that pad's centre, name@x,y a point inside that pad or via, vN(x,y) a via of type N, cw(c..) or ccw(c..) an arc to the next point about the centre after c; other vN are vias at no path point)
1.25V: C57.1 C58.2 C123.1 C124.1 C125.1 C126.1 C127.1 C128.1 C129.1 C130.1 C131.1 C132.1 L4.2 R44.2 R46.2 U4.3 U14.5 U14.6 U14.45 U14.49 U14.55 U14.66 U14.78 U14.95 | length 32.9
  Top Layer w0.2: v1(76.169,24.623) 76.25,24.623 76.555,24.317 U14.78@77.827,24.317 ; U14.95@77.827,17.517 78.872,17.517 v1(78.967,17.612) ; U14.5@81.302,13.642 81.302,14.612 v1@81.552,14.862 ; v1(81.552,14.867) v1@81.552,14.862 ; U14.6@81.702,13.642 81.702,14.636 81.552,14.786 v1@81.552,14.862 ; U14.66@83.302,26.992 83.302,26.106 v1(83.593,25.815) ; v1(86.223,25.815) 86.271,25.863 87.552,25.863 87.702,26.013 U14.55@87.702,26.992 ; v1(89.952,23.14) 89.975,23.117 U14.45@91.177,23.117 ; v1(89.992,25.18) 89.992,25.132 90.407,24.717 U14.49@91.177,24.717
  Top Layer w0.25: U4.3@66.364,37.856 U4.3@66.365,37.856 ; v1(66.604,34.724) 67.216,34.724 L4.2@67.546,34.394 67.546,37.072 68.056,37.582 C57.1@68.157,37.582 69.837,37.582 C58.2@69.935,37.484 70.729,37.484 71.016,37.771 71.016,39.642 70.595,40.063 R44.2@69.935,40.063
  Top Layer w0.5: R46.2@63.077,34.759 63.112,34.724 v1(63.855,34.724)
  Bottom Layer w0.25: C127.1@89.053,23.011 89.134,23.092 89.904,23.092 v1(89.952,23.14)
  Bottom Layer w0.5: v1(63.855,34.724) v1(66.604,34.724) ; v1(81.552,14.867) 81.738,15.053 81.738,15.78 C126.1@81.788,15.83 ; C130.1@83.062,24.83 83.062,24.93 83.593,25.462 v1(83.593,25.815) ; C123.1@85.302,26.587 85.302,26.562 85.527,26.337 85.93,26.337 86.223,26.044 v1(86.223,25.815) 85.969,25.562 85.969,24.967 C129.1@85.919,24.917 ; C128.1@89.079,25.342 89.129,25.292 89.88,25.292 v1(89.992,25.18)
  other v1: 78.942,15.072 78.985,16.426 77.274,26.254 76.817,26.987 77.652,26.987 68.521,33.352 68.521,34.864 66.546,35.77 68.521,36.205
1.25V_EN: R45.2 U3.17 | length 27.8
  Top Layer w0.2: R45.2@66.439,42.836 66.439,44.337 66.736,44.634 v1(67.546,44.634) ; U3.17@80.824,51.985 82.13,51.985 v1(82.511,52.367)
  Sig4 w0.2: v1(67.546,44.634) 67.546,52.211 68.445,53.111 74.038,53.111 74.364,52.785 82.092,52.785 v1(82.511,52.367)
1.25V_VMON1: R44.1 R47.2 U3.16 | length 34.6
  Top Layer w0.2: v1(66.989,43.646) 66.989,43.611 67.638,42.961 R47.2@67.638,42.861 68.766,42.861 70.162,41.466 R44.1@70.162,41.366 ; U3.16@80.824,51.485 82.605,51.485 v1(82.715,51.595)
  Sig4 w0.2: v1(66.989,43.646) 66.446,44.189 66.446,52.318 68.013,53.885 82.662,53.885 83.061,53.486 83.061,52.023 82.715,51.676 v1(82.715,51.595)
3.3V: C37.2 C43.2 C48.1 C91.2 C98.2 C103.1 C107.1 C109.1 C112.1 C121.1 C122.1 C137.1 C138.2 C139.1 C140.1 C141.1 C142.1 C143.1 C144.1 C145.1 C146.1 C147.1 D8.1 D9.1 D12.1 J10.1 J21.1 J22.1 J23.1 R15.2 R31.1 R37.1 R54.1 R62.2 R91.2 R92.1 R120.1 R122.1 R124.1 R126.1 R147.1 R148.1 TP5.1 U3.37 U6.6 U7.11 U8.5 U10.5 U12.7 U13.7 U14.3 U14.7 U14.44 U14.46 U14.52 U14.63 U14.67 U14.73 U14.79 Y1.4 | length 86
  Top Layer w0.2: v1(53.82,10.925) 53.877,10.982 54.214,10.982 54.71,11.478 U7.11@54.71,12.17 ; U14.79@77.827,23.917 78.597,23.917 78.995,24.315 78.995,25.138 v1(78.952,25.181) ; v1(80.425,14.804) 80.425,14.723 80.502,14.646 U14.3@80.502,13.642 ; v1(80.502,25.892) U14.73@80.502,26.992 ; U14.7@82.102,13.642 82.102,14.595 82.227,14.72 82.735,14.72 v1(82.777,14.762) ; v1(82.784,25.892) 82.784,25.973 82.902,26.092 U14.67@82.902,26.992 ; v1(84.453,25.815) 84.502,25.865 U14.63@84.502,26.992 ; U14.52@88.902,26.992 88.902,27.947 89.154,28.199 v1(89.896,28.199) ; v1(89.952,21.635) 89.952,22.262 90.407,22.717 U14.44@91.177,22.717 ; v1(89.96,24.191) 90.017,24.134 90.017,23.907 90.407,23.517 U14.46@91.177,23.517
  Top Layer w0.25: v1(122.352,29.664) 122.355,29.661 123.333,29.661 U8.5@123.336,29.658 ; U6.6@125.571,40.259 125.571,40.817 125.834,41.08 v1(126.484,41.08)
  Top Layer w0.3: v1(26.287,44.368) 26.326,44.406 26.326,45.214 C109.1@26.439,45.327 ; v1(26.964,48.557) 27.671,49.264 R122.1@27.671,50.246 27.679,50.237 29.091,50.237 R120.1@29.1,50.229 R120.1@29.063,50.191 ; C48.1@65.731,50.658 C48.1@65.875,50.801 ; v1@69.031,25.117 R147.1@69.031,25.962 ; v1(69.141,24.952) 69.179,24.914 69.563,24.914 69.995,24.482 R148.1@70.095,24.482 ; U3.37@73.324,49.485 74.507,49.485 74.66,49.332 v1(74.714,49.332) ; Y1.4@82.502,33.339 82.627,33.339 82.845,33.557 82.845,33.856 v1(82.883,33.894) 82.911,33.923 82.911,34.546 82.943,34.578 82.943,35.766 R15.2@82.946,35.77 ; v1@82.944,33.894 v1@82.944,33.951 ; v1(123.717,45.501) 123.771,45.501 123.91,45.64 U10.5@125.089,45.64
  Top Layer w0.4: U12.7@24.8,47.425 24.825,47.4 26.155,47.4 26.389,47.166 26.389,45.377 C109.1@26.439,45.327
  Top Layer w0.5: v1(47.254,10.808) 47.254,10.717 47.547,10.425 R91.2@48.469,10.425 ; v1(47.509,13.005) R92.1@48.469,13.005 ; C43.2@65.675,49.158 65.775,49.158 65.98,49.363 R37.1@68.472,49.363 ; v1(78.512,6.504) 79.457,6.504 79.665,6.297 D12.1@79.665,6.255
  Top Layer w0.6: v1(48.469,35.385) 48.492,35.385 49.042,34.835 49.042,34.528 R54.1@49.142,34.528 ; v1(76.396,34.177) 77.27,34.177 D8.1@77.348,34.1 77.382,34.134 79.088,34.134 D9.1@79.123,34.168 ; J23.1@105.002,22.94 105.202,23.14 J23.1@105.694,23.14 105.602,23.048 C122.1@105.602,21.031 106.866,21.031 v1(107.105,21.27)
  Top Layer w1: J21.1@32.55,43.043 32.55,40.938 v1(32.577,40.911) ; J22.1@47.812,48.963 49.463,48.963 v1(49.465,48.965) ; TP5.1@57.35,41.798 57.387,41.761 v1(59.557,41.761) ; v1(71.016,34.398) 71.016,35.455 J10.1@71.149,35.455
  Bottom Layer w0.2: v1(89.896,28.199) 89.896,27.063 C143.1@89.952,27.008
  Bottom Layer w0.25: v1(126.484,41.08) 127.038,41.634 C91.2@127.859,41.634
  Bottom Layer w0.3: v1(26.287,44.368) 27.388,44.368 27.615,44.596 R126.1@27.615,45.293 27.632,45.31 29.083,45.31 R124.1@29.1,45.327 ; v1(82.777,14.762) 82.777,14.816 82.958,14.997 82.958,15.68 C140.1@83.108,15.83 ; R31.1@100.333,36.505 v1(100.333,37.252) ; v1(123.717,45.501) 124.326,44.892 C107.1@125.102,44.892
  Bottom Layer w0.4: U13.7@24.789,48.077 26.456,48.077 26.936,48.557 v1(26.964,48.557) 26.983,48.576 26.983,49.283 27,49.3 26.671,49.629 26.671,50.146 26.571,50.246 C112.1@26.471,50.246 ; v1(122.352,29.664) 122.352,29.637 122.534,29.456 122.534,28.914 122.634,28.814 C103.1@122.734,28.814
  Bottom Layer w0.5: v1(53.82,10.925) 54.05,11.155 54.723,11.155 C98.2@54.773,11.205 ; C37.2@73.968,50.281 74.068,50.281 74.118,50.231 74.118,49.928 v1(74.714,49.332) ; C144.1@78.84,26.152 78.89,26.102 78.89,25.243 v1(78.952,25.181) ; C139.1@80.425,15.804 v1(80.425,14.804) 80.425,14.12 80.752,13.792 80.752,13.692 80.802,13.642 C137.1@80.902,13.642 ; C147.1@80.454,24.83 80.454,25.844 v1(80.502,25.892) 80.562,25.952 C138.2@80.562,27.167 ; C145.1@81.788,24.832 81.838,24.882 81.838,25.599 82.131,25.892 v1(82.784,25.892) ; C146.1@84.448,24.83 84.448,25.81 v1(84.453,25.815)
  Bottom Layer w0.6: R62.2@49.604,30.682 v1(49.604,31.404) ; C141.1@88.885,21.635 v1(89.952,21.635) ; C142.1@89.085,24.191 v1(89.96,24.191)
  other v1: 65.675,49.952 65.473,51.889
3.3Vref: C44.2 C49.1 C83.1 C134.1 L7.1 L8.1 L10.2 R39.1 TP7.1 U5.23 | length 105
  Top Layer w0.2: U5.23@46.143,30.765 46.819,30.765 46.936,30.882 46.936,31.269 v1(47.351,31.683)
  Top Layer w0.5: v1(61.323,35.095) 61.323,33.165 63.807,30.682 68.819,30.682 69.463,31.325 69.923,31.325 72.653,34.055 75.01,34.055 78.453,37.498 80.312,37.498 83.88,41.066 84.629,41.066 v1(85.707,42.144) ; v1(84.807,50.11) 84.793,50.123 R39.1@84.793,50.935 84.793,52.086 85.393,52.685 TP7.1@88.062,52.685 ; v1(91.953,36.718) 91.953,32.646 93.293,31.306 v1(93.293,27.233)
  Sig4 w0.5: v1(84.807,50.11) 84.807,43.044 v1(85.707,42.144) 87.153,40.698 89.52,40.698 91.953,38.265 v1(91.953,36.718) ; v1(89.984,16.797) 90.05,16.797 90.057,16.789 90.52,16.789 91.003,17.273 91.003,24.943 v1(93.293,27.233)
  Bottom Layer w0.5: v1(47.351,31.683) 47.344,31.69 C83.1@47.344,32.585 47.344,33.641 48.003,34.3 60.527,34.3 v1(61.323,35.095) ; v1(84.807,50.11) 84.807,50.68 85.1,50.973 C49.1@87.103,50.973 87.093,50.984 87.093,52.41 C44.2@87.082,52.42 ; L7.1@88.989,15.681 89.011,15.702 89.011,16.816 C134.1@89.032,16.838 89.943,16.838 v1(89.984,16.797) 90.31,17.123 90.953,17.123 91.003,17.173 L8.1@91.003,17.273 ; L10.2@89.277,14.465 89.29,14.465 89.34,14.515 L7.1@89.34,15.681
5V: C46.2 C51.1 C92.2 C101.1 C105.1 R38.1 TP6.1 U6.5 U8.3 U10.3 | length 82
  Top Layer w0.25: v1(122.551,30.958) U8.3@123.336,30.958 ; U6.5@125.571,39.759 126.312,39.759 126.489,39.935 v1(126.556,39.935)
  Top Layer w0.3: R38.1@84.746,49.005 85.769,49.005 v1(85.789,48.985) ; v1(123.91,46.938) 123.913,46.94 U10.3@125.089,46.94
  Top Layer w0.4: TP6.1@119.575,32.158 120.264,31.469 122.012,31.469 122.523,30.958 v1(122.551,30.958)
  Power w0.25: v1(126.556,39.935) 127.826,39.935 127.889,39.873
  Power w0.5: v1(85.789,48.985) 86.533,48.985 91.263,53.716 110.462,53.716 113.378,50.8 123.224,50.8 123.91,50.114 v1(123.91,46.938) 124.341,46.938 124.898,46.381 124.898,44.665 125.941,43.622 127.175,43.622 127.889,42.908 127.889,39.873 127.889,36.769 125.485,34.365 123.826,34.365 122.551,33.09 v1(122.551,30.958)
  Bottom Layer w0.25: v1(126.556,39.935) 127.015,40.393 C92.2@127.859,40.393
  Bottom Layer w0.3: v1(85.789,48.985) 85.827,48.947 86.409,48.947 86.466,48.89 87.049,48.89 ; C51.1@87.049,48.165 87.049,48.89 ; C46.2@87.049,49.644 87.049,48.89 ; v1(123.91,46.938) 123.949,46.9 124.379,46.9 124.989,46.29 C105.1@125.089,46.29
  Bottom Layer w0.4: v1(122.551,30.958) 122.57,30.977 122.57,31.568 122.67,31.668 C101.1@122.734,31.668
5Vp1: C4.1 C47.2 C52.1 J15.1 R6.2 R41.1 TP9.1 | length 104.2
  Top Layer w0.5: C47.2@69.85,56.216 71.103,56.216 v1(71.379,56.492) ; C47.2@69.935,56.166 C52.1@69.935,54.818 69.976,54.777 69.976,53.526 R41.1@70.017,53.485 ; R6.2@153,44 153,46.296 150.949,48.347 C4.1@150.949,56.102 152.702,56.102 154.1,57.5 J15.1@154.1,58.291 ; J15.1@153.891,58.291 J15.1@154.03,58.43 ; J15.1@154.17,58.152 J15.1@154.17,58.361
  Power w0.5: v1(71.379,56.492) 88.145,56.492 89.521,55.116 111.417,55.116 114.169,52.364 139.257,52.364 140.113,53.219 150.239,53.219 v1(150.949,53.929)
5Vp2: C3.2 C45.2 C50.1 J11.1 R5.1 R40.1 TP8.1 | length 69.4
  Top Layer w0.5: R40.1@84.892,54.818 C50.1@87.164,54.818 87.168,54.814 88.565,54.814 C45.2@88.569,54.81 88.569,54.71 88.619,54.66 89.345,54.66 v1(89.59,54.416) ; v1(137.947,51.664) 138.071,51.539 C3.2@138.071,50.598 139.485,50.598 ; R5.1@138.715,46.14 138.715,47.42 139.485,48.19 139.485,50.598 ; J11.1@141.3,50.999 140.898,50.598 139.485,50.598 ; TP8.1@145.286,52.431 145.443,52.431 TP8.1@146.093,51.781
  Top Layer w1: J11.1@141.3,50.999 141.3,51.299 142.241,52.24 144.695,52.24 TP8.1@145.084,52.629
  Power w0.5: v1(89.59,54.416) 110.957,54.416 113.709,51.664 v1(137.947,51.664)
12V: C27.1 C31.1 C32.1 C33.1 C34.1 C35.1 C36.1 C89.2 R22.1 R23.1 R24.2 R51.2 R97.2 R130.1 TP3.1 U3.7 U3.8 U3.9 U6.1 | length 53.9
  Top Layer w0.25: U6.1@125.571,37.759 125.683,37.759 125.683,37.306 v1(125.731,37.259)
  Top Layer w0.5: R51.2@88.052,43.706 92.036,43.706 v1(92.141,43.601) ; C27.1@93.339,42.959 C27.1@93.504,42.959 93.733,42.73 R23.1@95.3,42.73 95.4,42.73 95.45,42.68 95.45,42.092 96.363,41.178 96.363,39.267 99.603,36.027 R130.1@99.603,33.587 107.199,33.587 v1(108.988,35.376) ; v1(112.313,35.445) 112.371,35.503 v1(123.736,35.503)
  Bottom Layer w0.5: v1(92.141,43.601) R22.1@98.878,43.601 ; v1(108.988,35.376) 109.057,35.445 v1(112.313,35.445) ; v1(123.736,35.503) 124.257,34.982 R97.2@125.536,34.982 ; R97.2@125.536,34.982 C89.2@125.537,36.444 125.637,36.444 125.687,36.494 125.687,37.214 v1(125.731,37.259)
  other v1: 82.17,47.591
12V_Cobra: C25.1 C26.2 C30.2 L2.2 Q3.3 R25.2 R32.1 R33.1 | length 14
  Top Layer w0.5: v1(100.756,38.624) 100.778,38.601 R32.1@104.019,38.601 ; R32.1@104.182,38.567 104.182,37.32 R33.1@104.177,37.316 104.177,36.37 C30.2@104.432,36.114
  Sig4 w0.5: v1(97.285,44.485) 97.285,40.687 99.349,38.624 ; 99.365,38.607 v1@100.773,38.607
48V/12V_BDC: C96.2 C97.1 Q11.1 Q11.2 Q11.3 R87.1 U7.4 | length 2.5
  Top Layer w0.5: R87.1@46.026,11.849 46.063,11.849 46.113,11.799 46.113,9.508 46.041,9.436
  Bottom Layer w0.2: v1@45.156,7.624 45.158,7.624 v1(45.163,7.628)
  other v1: 45.163,8.83
  other v2: 51.96,9.695 52.835,9.695 53.71,9.695 54.585,9.695 55.46,9.695
48V/12V_C: C16.1 D11.1 R99.2 | length 5.8
  Top Layer w0.5: v3(130.984,50.265) 131.936,50.265 132.236,50.565 C16.1@132.236,50.781 C16.1@132.218,50.799
  Bottom Layer w0.5: D11.1@129.781,51.964 130.131,51.964 130.965,51.13 130.965,50.284 v3(130.984,50.265) 130.984,48.502 R99.2@130.983,48.501
48V/12V_IN: C8.1 D1.2 J3.1 L1.1
  other v1: 135.985,70.892 147.138,70.892 136.985,70.908 137.985,70.908 139.02,70.908 140.058,70.908 141.029,70.908 142.085,70.908 143.085,70.908 144.12,70.908 145.158,70.908 146.129,70.908 128.124,71.433 128.651,71.433 129.18,71.436 129.703,71.433 130.307,71.433 130.838,71.433 131.414,71.433 131.982,71.433 132.523,71.433 135.957,71.733 147.109,71.733 128.117,71.986 128.74,72.003 129.267,72.003 129.797,72.005 130.32,72.003 130.924,72.003 131.455,72.003 132.03,72.003 132.599,72.003 128.11,72.54 128.65,72.543 132,72.54 132.599,72.54 135.957,72.733 147.109,72.733 129.633,72.975 130.739,72.975 128.11,73.067 132,73.067 132.599,73.067 128.65,73.122 130.153,73.546 131.258,73.546 128.107,73.596 131.997,73.596 132.596,73.596 152.356,73.594 153.19,73.6 154.162,73.6 155.2,73.6 156.235,73.6 128.65,73.662 135.957,73.768 147.109,73.768 128.11,74.119 132,74.119 132.599,74.119 129.626,74.186 130.739,74.186 128.65,74.231 152.356,74.562 156.223,74.565 128.11,74.723 132,74.723 132.599,74.723 128.65,74.806 130.153,74.783 131.258,74.783 135.957,74.806 147.109,74.806 128.11,75.254 130.705,75.254 132,75.254 132.599,75.254 129.626,75.273 128.65,75.337 152.356,75.6 156.223,75.6 130.153,75.767 131.258,75.767 135.957,75.778 147.109,75.778 128.11,75.83 132,75.83 132.599,75.83 128.65,75.941 128.11,76.398 132,76.398 132.599,76.398 129.601,76.42 130.705,76.42 128.653,76.464 152.356,76.635 156.223,76.638 135.957,76.833 147.109,76.833 128.11,76.938 132,76.938 132.599,76.938 128.65,76.994 130.153,77.003 131.258,77.003 128.11,77.517 128.65,77.521 132,77.517 132.599,77.517 135.957,77.833 147.109,77.833 128.104,78.041 128.645,78.041 129.213,78.041 129.789,78.041 130.32,78.041 130.924,78.041 131.447,78.038 131.976,78.041 132.503,78.041 128.093,78.623 128.62,78.623 129.149,78.626 129.672,78.623 130.277,78.623 130.808,78.623 131.383,78.623 131.951,78.623 132.492,78.623 135.957,78.868 147.109,78.868 135.957,79.906 147.109,79.906 135.957,80.878 147.109,80.878 136.957,80.894 137.957,80.894 138.992,80.894 140.029,80.894 141.001,80.894 142.057,80.894 143.057,80.894 144.092,80.894 145.129,80.894 146.101,80.894
48V/12V_IN_FILTERED: C9.2 C10.2 D3.2 L1.2 Q1.5 R12.2 R13.2 R153.1 | length 40.3
  Top Layer w0.2: R12.2@107.48,63.736 107.48,64.496 v1(107.881,64.896)
  Top Layer w0.25: 106.554,75.614 106.632,75.614 106.654,75.635 106.654,75.706
  Top Layer w0.5: v1(108.013,75.721) 108.059,75.676 C10.2@108.059,74.515
  Top Layer w1: Q1.5@107.281,77.863 Q1.5@107.459,78.041
  Power w1: v3(121.473,70.374) 122.768,69.079 122.768,53.529 v1(122.753,53.514)
  Sig4 w0.2: v1(107.881,64.896) 106.852,65.925 106.852,70.419 107.541,71.108 108.599,71.108 108.84,71.349 108.84,75.719 v1(108.859,75.738)
  Bottom Layer w0.2: v1(107.881,64.896) 108.454,64.896 108.886,64.465 R13.2@108.886,63.641
  Bottom Layer w0.5: R153.1@108.013,74.659 R153.1@108.013,74.808 ; R153.1@108.013,74.809 v1(108.013,75.721)
  Bottom Layer w1: D3.2@122.454,50.999 122.454,53.215 v1(122.753,53.514) 122.712,53.555 C9.2@122.712,54.963
  other v1: 116.52,71.433 117.099,71.433 117.639,71.433 118.208,71.433 118.783,71.433 119.314,71.433 119.918,71.433 120.441,71.43 120.971,71.433 121.498,71.433 116.52,72.005 117.099,72.005 117.639,72.005 118.208,72.005 118.783,72.005 119.314,72.005 119.918,72.005 120.441,72.003 120.971,72.005 121.498,72.005 119.7,72.591 120.523,72.591 121.369,72.581 117.135,73.037 118.242,73.037 119.7,73.118 120.523,73.118 121.369,73.122 117.656,73.608 118.761,73.608 119.697,73.648 120.52,73.648 121.369,73.69 119.7,74.171 120.523,74.171 117.129,74.249 118.242,74.249 121.369,74.266 119.7,74.775 120.523,74.775 121.369,74.797 117.656,74.845 118.761,74.845 119.7,75.306 120.523,75.306 117.129,75.335 118.208,75.316 121.369,75.401 107.4,75.731 117.656,75.829 118.761,75.829 119.7,75.881 120.523,75.881 121.372,75.924 106.004,76.406 107.241,76.406 108.225,76.406 109.462,76.406 119.7,76.45 120.523,76.45 121.369,76.453 117.103,76.482 118.208,76.482 106.645,76.925 107.713,76.959 108.878,76.959 119.7,76.99 120.523,76.99 121.369,76.98 117.656,77.066 118.761,77.066 106.004,77.511 107.241,77.511 108.225,77.511 109.462,77.511 116.527,77.833 117.106,77.833 117.646,77.833 118.215,77.833 118.79,77.833 119.321,77.833 119.925,77.833 120.448,77.83 120.978,77.833 121.505,77.833 106.645,78.038 107.731,78.038 108.878,78.064 116.52,78.399 117.099,78.399 117.639,78.399 118.208,78.399 118.783,78.399 119.314,78.399 119.918,78.399 120.441,78.396 120.971,78.399 121.498,78.399 106.004,78.628 107.241,78.628 108.225,78.628 109.462,78.628 116.52,78.913 117.099,78.913 117.639,78.913 118.208,78.913 118.783,78.913 119.314,78.913 119.918,78.913 120.441,78.91 120.971,78.913 121.498,78.913 107.713,79.164 106.645,79.182 108.84,79.217 110.102,79.287 110.792,79.287 106.004,79.706 107.241,79.706 108.225,79.706 109.462,79.706 110.105,79.809 110.795,79.809 111.736,79.809 105.927,80.388 107.536,80.409 108.059,80.406 108.663,80.406 110.105,80.414 110.795,80.414 111.736,80.414 111.739,80.937 106.1,81.024 106.627,81.024 107.157,81.027 107.679,81.024 108.284,81.024 108.815,81.024 109.39,81.024 109.958,81.024 110.499,81.024 111.077,81.024 106.1,81.623 106.627,81.623 107.157,81.626 107.679,81.623 108.284,81.623 108.815,81.623 109.39,81.623 109.958,81.623 110.499,81.623 111.077,81.623 106.1,82.179 106.627,82.179 107.157,82.181 107.679,82.179 108.284,82.179 108.815,82.179 109.39,82.179 109.958,82.179 110.499,82.179 111.077,82.179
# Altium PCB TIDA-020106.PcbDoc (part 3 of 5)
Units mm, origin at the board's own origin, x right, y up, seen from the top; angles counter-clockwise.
Board outline 158.53 x 83.25 mm, 6 copper layers (Top Layer, GND, Power, Sig4, GND (Mid4), Bottom Layer), stack 1.59 mm thick; 407 components, 254 nets, 1274 pads, 2396 vias.
Unrouted connection lines stored in the file: 294.

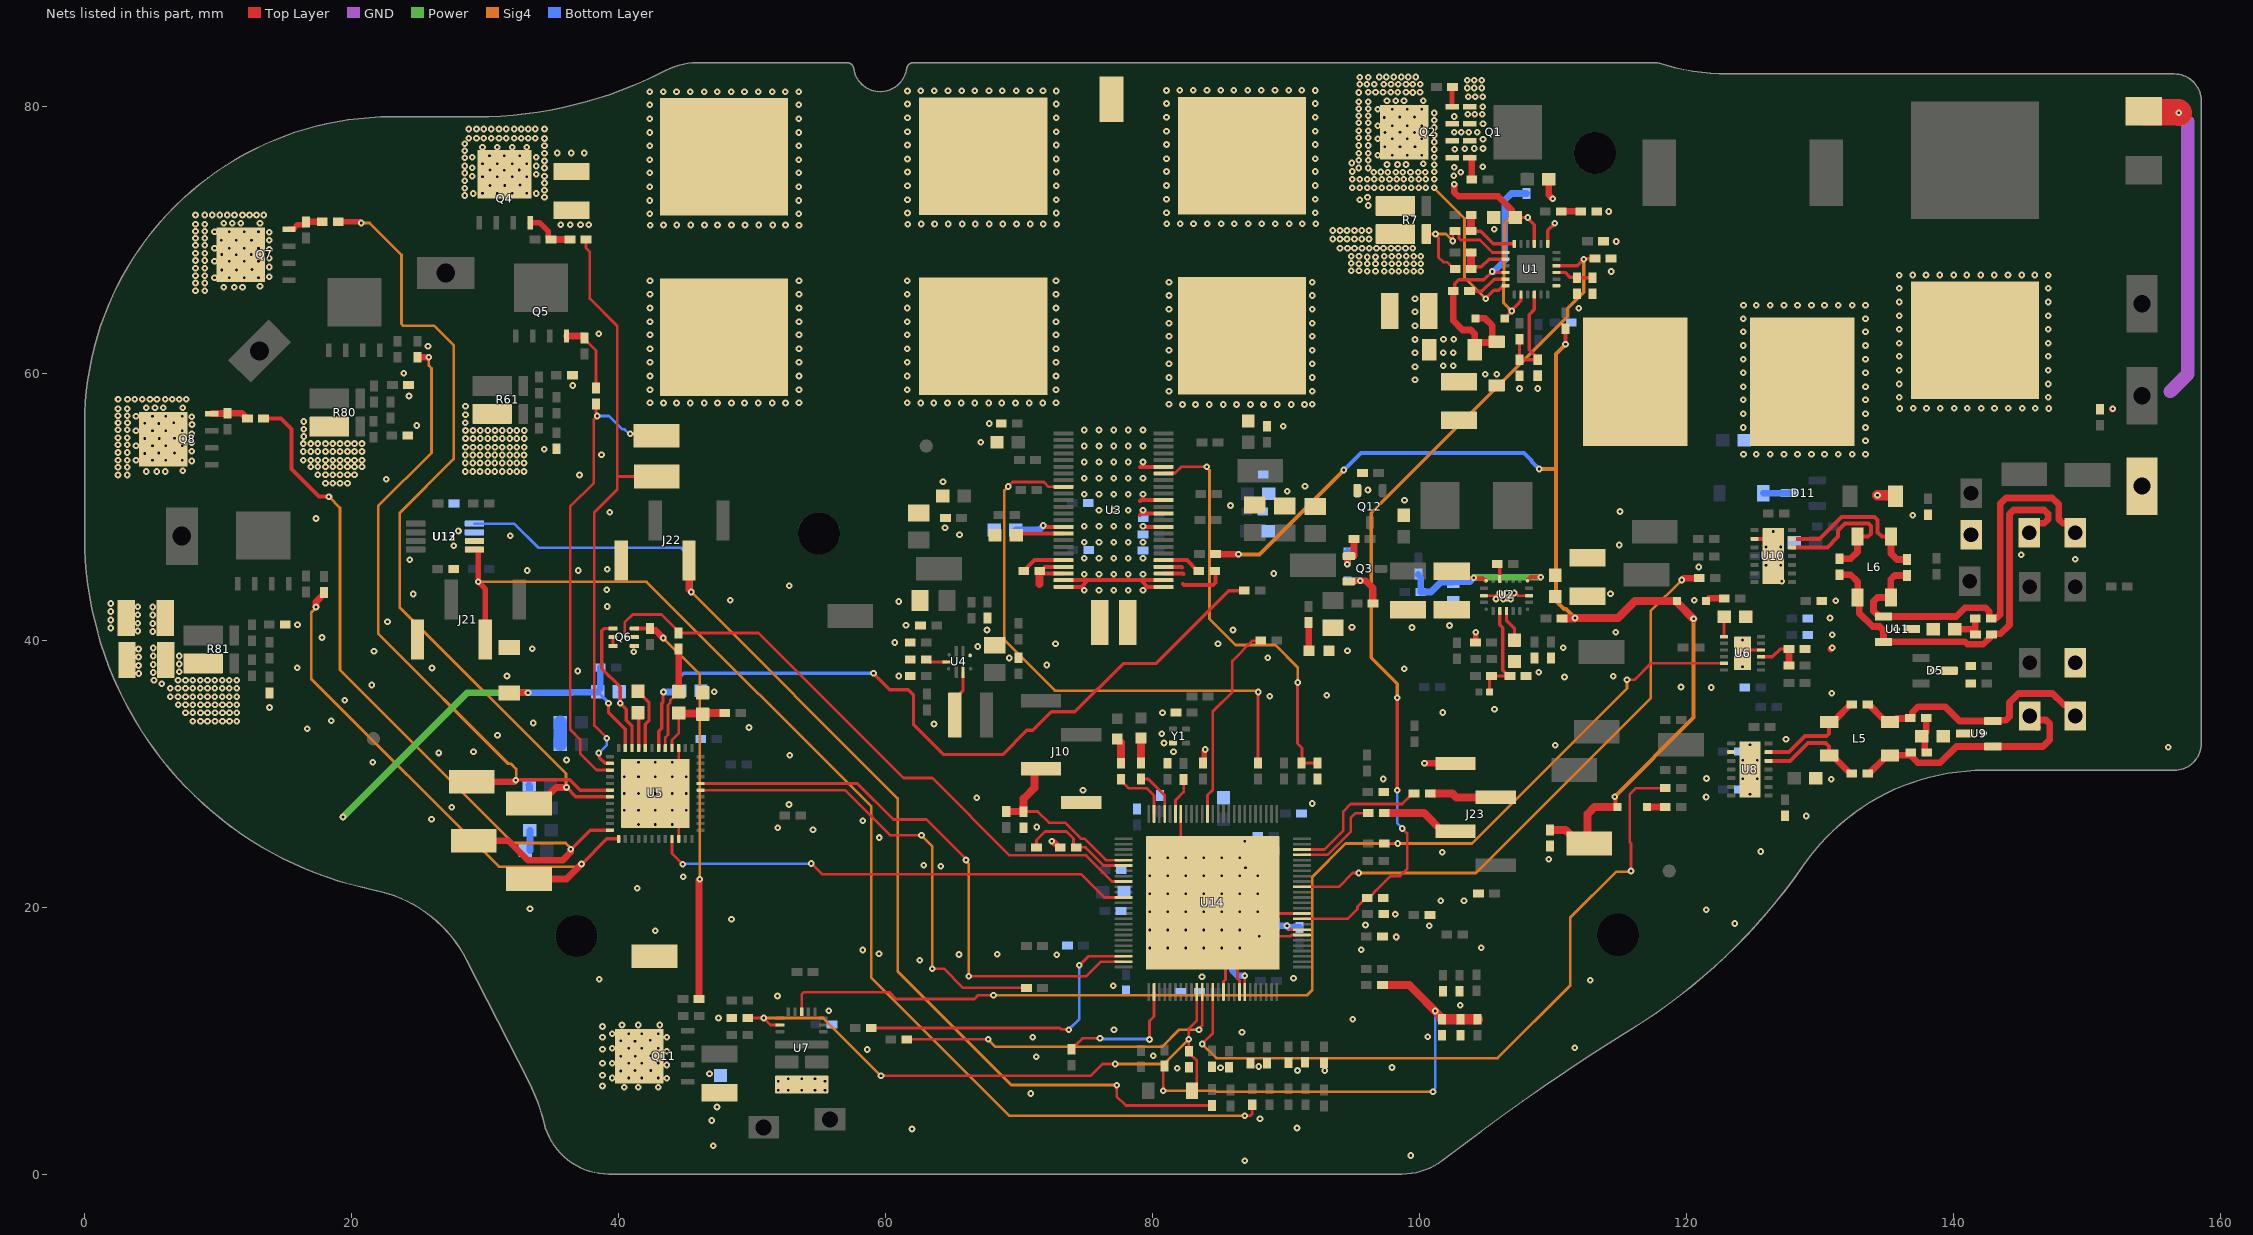
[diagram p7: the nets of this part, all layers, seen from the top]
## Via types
v1: diameter 0.5, hole 0.2, Top Layer to Bottom Layer, 2306 vias
v2: diameter 0.5, hole 0.2, Top Layer to Bottom Layer, tented both sides, 87 vias
v3: diameter 0.6, hole 0.2, Top Layer to Bottom Layer, 3 vias

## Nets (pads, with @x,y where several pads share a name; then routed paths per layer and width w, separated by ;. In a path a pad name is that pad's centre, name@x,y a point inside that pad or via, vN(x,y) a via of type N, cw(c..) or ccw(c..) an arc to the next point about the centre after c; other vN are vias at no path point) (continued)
48V/12V_P: C5.1 C6.1 C21.1 C22.1 C23.2 C24.2 C28.1 C60.1 C61.1 C67.2 C68.1 C73.1 C74.1 C75.1 C76.1 Q4.5 Q7.5 Q8.5 Q11.5 R7.1 R22.2 R27.1 R58.2 TP1.1 U2.11 U2.17 U5.35 | length 46
  Top Layer w0.25: v1(39.233,35.268) 39.233,34.589 40.493,33.329 U5.35@40.493,31.915
  Top Layer w0.3: C22.1@102.402,45.165 102.9,44.667 v1(104.038,44.667) 104.076,44.629 104.73,44.629 104.909,44.45 U2.17@104.983,44.45 ; 108.158,44.587 108.286,44.715 v1(109.061,44.715)
  Top Layer w0.5: C68.1@31.813,36.063 v1(33.213,36.063)
  Power w0.5: v1(19.351,26.751) 28.663,36.063 v1(33.213,36.063) ; v1(104.038,44.667) 104.086,44.715 v1(109.061,44.715)
  Bottom Layer w0.25: C67.2@38.433,36.143 39.185,35.391 39.185,35.316 v1(39.233,35.268)
  Bottom Layer w0.5: v1(33.213,36.063) 36.484,36.063 36.524,36.103 38.393,36.103 C67.2@38.433,36.143 38.612,36.322 R58.2@38.612,37.959 ; R27.1@99.9,44.914 99.9,44.855 100.078,44.677 R22.2@100.078,43.601 100.852,43.601 101.591,44.339 102.441,44.339 102.467,44.366 103.737,44.366 v1(104.038,44.667)
  other v1: 40.421,6.505 41.456,6.505 42.96,6.504 38.788,6.599 43.593,7.178 39.516,7.205 40.753,7.205 41.737,7.205 42.974,7.205 38.788,7.41 40.157,7.724 41.225,7.758 42.391,7.758 43.593,8.178 38.788,8.31 39.516,8.31 40.753,8.31 41.737,8.31 42.974,8.31 40.157,8.837 41.243,8.837 42.391,8.863 43.593,9.213 38.788,9.345 39.516,9.428 40.753,9.428 41.737,9.428 42.974,9.428 40.157,9.981 41.225,9.963 42.352,10.016 38.788,10.251 43.593,10.251 39.516,10.505 40.753,10.505 41.737,10.505 42.974,10.505 38.788,11.061 40.249,11.164 41.456,11.164 43.068,11.17 4.046,37.499 4.035,38.095 4.035,38.733 4.035,39.332 3.987,40.677 1.957,40.91 3.976,41.273 1.946,41.506 3.976,41.911 1.946,42.144 3.976,42.51 1.946,42.743 2.5,52.365 3.2,52.365 4.616,52.627 5.396,52.627 6.028,52.627 7.335,52.693 2.5,52.944 3.2,52.944 8.022,53.417 3.849,53.465 5.086,53.465 6.07,53.465 7.306,53.465 2.5,53.484 3.2,53.484 4.489,53.984 5.557,54.017 6.723,54.017 2.5,54.052 3.2,54.052 8.022,54.139 3.849,54.57 5.086,54.57 6.07,54.57 7.306,54.57 2.5,54.628 3.2,54.628 8.022,54.789 4.489,55.096 5.576,55.096 6.723,55.122 2.5,55.159 3.2,55.159 8.022,55.452 3.849,55.687 5.086,55.687 6.07,55.687 7.306,55.687 2.5,55.763 3.2,55.763 8.034,56.145 5.557,56.222 4.489,56.241 2.503,56.286 3.203,56.286 6.684,56.275 8.022,56.741 3.849,56.765 5.086,56.765 6.07,56.765 7.306,56.765 2.5,56.815 3.2,56.815 2.5,57.342 3.2,57.342 4.616,57.403 5.885,57.403 7.335,57.403 5.266,57.412 2.503,58.03 3.208,58.033 3.748,58.033 4.317,58.033 4.892,58.033 5.423,58.033 6.028,58.033 6.55,58.03 7.08,58.033 7.607,58.033 8.296,66.177 8.996,66.177 10.412,66.439 11.193,66.439 11.824,66.439 13.131,66.504 8.296,66.755 8.996,66.755 9.72,67.141 10.825,67.141 11.942,67.141 13.02,67.141 13.818,67.229 8.296,67.295 8.996,67.295 96.073,67.625 96.688,67.625 97.35,67.631 97.907,67.631 98.428,67.631 98.992,67.631 99.545,67.631 100.079,67.631 94.875,67.668 95.451,67.658 10.273,67.725 11.377,67.725 12.53,67.763 8.296,67.864 8.996,67.864 13.818,67.951 95.451,68.193 96.073,68.182 96.688,68.182 97.35,68.191 97.907,68.191 98.428,68.191 98.992,68.191 99.545,68.191 100.079,68.191 94.875,68.225 9.72,68.378 10.825,68.378 11.942,68.378 13.02,68.378 8.296,68.439 8.996,68.439 13.818,68.601 96.073,68.703 96.688,68.703 94.875,68.745 95.451,68.745 97.35,68.745 97.907,68.745 98.428,68.745 98.992,68.745 99.545,68.745 100.079,68.745 11.351,68.872 10.273,68.89 12.477,68.89 8.296,68.97 8.996,68.97 13.818,69.264 9.72,69.362 10.825,69.362 11.942,69.362 13.02,69.362 94.032,69.355 94.589,69.355 95.11,69.355 95.674,69.355 96.227,69.355 96.761,69.355 97.293,69.355 97.85,69.355 98.371,69.355 98.935,69.355 99.488,69.355 8.296,69.575 8.996,69.575 10.239,69.958 11.351,69.958 12.496,69.958 13.83,69.957 93.475,70.048 94.032,70.048 94.552,70.048 95.117,70.048 95.67,70.048 96.204,70.048 8.299,70.097 8.999,70.097 13.818,70.553 9.72,70.599 10.825,70.599 11.942,70.599 13.02,70.599 8.296,70.627 8.996,70.627 93.475,70.686 94.032,70.686 94.552,70.686 95.117,70.686 95.67,70.686 96.204,70.686 42.355,71.084 53.508,71.084 43.355,71.1 44.355,71.1 45.39,71.1 46.428,71.1 47.4,71.1 48.455,71.1 49.455,71.1 50.49,71.1 51.528,71.1 52.5,71.1 61.662,71.148 72.815,71.148 8.296,71.154 8.996,71.154 62.662,71.164 63.662,71.164 64.697,71.164 65.735,71.164 66.707,71.164 67.762,71.164 68.762,71.164 69.797,71.164 70.835,71.164 71.807,71.164 81.057,71.183 82.057,71.199 83.057,71.199 84.092,71.199 85.129,71.199 86.101,71.199 87.157,71.199 88.157,71.199 89.192,71.199 90.229,71.199 91.201,71.199 92.209,71.183 10.412,71.215 11.063,71.223 11.681,71.215 13.131,71.215 8.299,71.842 9.004,71.845 9.545,71.845 10.113,71.845 10.689,71.845 11.22,71.845 11.824,71.845 12.347,71.842 12.876,71.845 13.403,71.845 42.327,71.925 53.48,71.925 61.634,71.989 72.787,71.989 81.029,72.024 92.181,72.024 42.327,72.925 53.48,72.925 61.634,72.989 72.787,72.989 81.029,73.024 92.181,73.024 34.443,73.178 28.471,73.303 29.103,73.45 33.813,73.45 29.803,73.469 30.908,73.469 32.026,73.469 33.103,73.469 34.443,73.705 28.471,73.843 42.327,73.96 53.48,73.96 61.634,74.024 72.787,74.024 30.356,74.053 31.461,74.053 81.029,74.059 92.181,74.059 32.614,74.091 34.44,74.234 28.471,74.412 29.803,74.706 30.908,74.706 32.026,74.706 33.103,74.706 29.037,74.757 34.443,74.757 33.813,74.9 28.471,74.987 42.327,74.998 53.48,74.998 61.634,75.062 72.787,75.062 81.029,75.096 92.181,75.096 31.435,75.2 30.356,75.219 32.561,75.219 34.443,75.361 29.037,75.388 28.471,75.518 33.822,75.518 29.803,75.69 30.908,75.69 32.026,75.69 33.103,75.69 34.443,75.892 42.327,75.97 53.48,75.97 61.634,76.034 72.787,76.034 81.029,76.068 92.181,76.068 28.471,76.122 29.037,76.169 33.813,76.169 30.322,76.286 31.435,76.286 32.579,76.286 34.443,76.468 35.402,76.489 36.457,76.489 37.429,76.489 28.474,76.645 29.803,76.927 30.908,76.927 32.026,76.927 33.103,76.927 34.443,77.036 42.327,77.025 53.48,77.025 61.634,77.089 72.787,77.089 81.029,77.124 92.181,77.124 28.471,77.175 28.775,77.585 29.354,77.585 29.894,77.585 30.462,77.585 31.038,77.585 31.569,77.585 32.173,77.585 32.696,77.582 33.225,77.585 33.752,77.585 34.443,77.577 42.327,78.025 53.48,78.025 61.634,78.089 72.787,78.089 81.029,78.124 92.181,78.124 28.775,78.285 29.354,78.285 29.894,78.285 30.462,78.285 31.038,78.285 31.569,78.285 32.173,78.285 32.696,78.282 33.225,78.285 33.752,78.285 34.44,78.282 42.327,79.06 53.48,79.06 61.634,79.124 72.787,79.124 81.029,79.159 92.181,79.159 42.327,80.098 53.48,80.098 61.634,80.162 72.787,80.162 81.029,80.196 92.181,80.196 42.327,81.07 53.48,81.07 43.327,81.086 44.327,81.086 45.362,81.086 46.4,81.086 47.372,81.086 48.427,81.086 49.427,81.086 50.462,81.086 51.5,81.086 52.472,81.086 61.634,81.134 62.634,81.15 63.634,81.15 64.669,81.15 65.707,81.15 66.679,81.15 67.734,81.15 68.734,81.15 69.769,81.15 70.807,81.15 71.779,81.15 72.787,81.134 81.029,81.168 92.181,81.168 82.029,81.184 83.029,81.184 84.064,81.184 85.101,81.184 86.073,81.184 87.129,81.184 88.129,81.184 89.164,81.184 90.201,81.184 91.173,81.184
BOOT1: J10.3 R147.2 R149.2 U14.80 | length 13.9
  Top Layer w0.2: R149.2@70.336,27.162 71.379,27.162 72.219,26.322 73.44,26.322 74.634,25.128 74.886,25.128 76.497,23.517 U14.80@77.827,23.517
  Top Layer w0.5: R147.2@69.031,27.162 69.035,27.157 70.331,27.157 R149.2@70.336,27.153
  Top Layer w0.6: R149.2@70.336,27.162 70.336,28.122 71.149,28.935 J10.3@71.149,30.375
BOOT2: R148.2 R150.2 U14.81 | length 8.7
  Top Layer w0.2: R148.2@71.295,24.482 71.295,25.029 71.931,25.665 73.531,25.665 74.068,25.128 74.068,24.682 R150.2@74.269,24.482 ; R150.2@74.269,24.482 74.966,24.482 76.331,23.117 U14.81@77.827,23.117
CAN1H: J17.1 L5.2 R98.1 R100.2 U9.2 | length 19.9
  Top Layer w0.5: R98.1@133.551,35.17 133.651,35.17 134.756,34.065 135.026,34.065 L5.2@135.226,33.865 135.451,33.865 135.716,34.13 136.697,34.13 R100.2@136.747,34.18 136.847,34.18 136.897,34.23 136.897,34.57 137.344,35.017 139.353,35.017 140.433,33.937 U9.2@142.933,33.937 142.983,33.987 143.901,33.987 144.175,34.262 144.175,35.323 144.859,36.007 147.404,36.007 148.25,35.161 148.55,35.161 149.1,34.611 J17.1@149.1,34.311 ; J17.1@149.2,34.011 J17.1@149.2,34.311
CAN1L: J18.1 L5.1 R103.1 R105.1 U9.1 | length 19.3
  Top Layer w0.5: R105.1@133.551,29.997 133.651,29.997 134.801,31.147 134.801,31.165 135.001,31.365 L5.1@135.226,31.365 R103.1@136.876,31.365 ; R103.1@136.876,31.515 136.926,31.515 136.926,31.201 137.312,30.815 138.975,30.815 140.197,32.037 U9.1@142.933,32.037 146.679,32.037 147.2,32.558 147.2,33.73 146.907,34.023 J18.1@145.7,34.023
  Bottom Layer w0.5: J18.1@145.7,34.311 145.7,34.011 J18.1@146.25,33.461
CAN2H: J19.1 L6.2 R109.1 R110.2 U11.1 | length 31.6
  Top Layer w0.5: R109.1@136.492,44.84 135.577,44.84 135.284,44.547 135.284,43.211 L6.2@135.301,43.193 134.285,43.193 133.992,42.901 133.992,42.167 134.392,41.767 U11.1@134.742,41.767 140.188,41.767 140.841,42.421 142.375,42.421 142.668,42.128 142.668,41.684 142.718,41.634 R110.2@142.818,41.634 142.868,41.684 143.253,41.684 143.475,41.906 143.475,50.199 143.924,50.648 147.381,50.648 147.875,50.153 147.875,49.043 148.168,48.75 148.65,48.75 149.2,48.2 J19.1@149.2,47.9
CAN2L: J20.1 L6.1 R113.1 R115.1 U11.2 | length 31.3
  Top Layer w0.5: R115.1@131.455,44.892 132.291,44.892 132.801,44.382 L6.1@132.801,43.193 132.919,43.076 132.919,42.034 133.936,41.017 134.449,41.017 134.742,40.724 U11.2@134.742,39.867 140.858,39.867 141.039,39.686 142.211,39.686 142.675,40.15 142.675,40.386 142.725,40.436 R113.1@142.825,40.436 142.875,40.486 143.525,40.486 144.175,41.136 144.175,49.439 144.486,49.75 146.777,49.75 147.071,49.457 147.071,49.043 146.778,48.75 146.3,48.75 145.75,48.2 J20.1@145.75,47.9
CLK_DRV3263: R143.1 U5.19 | length 35.9
  Top Layer w0.2: U5.19@46.143,28.765 56.949,28.765 60.323,25.391 v1(62.676,25.391) ; v1(63.495,15.392) 64.352,15.392 65.785,13.958 R143.1@70.549,13.958
  Sig4 w0.2: v1(62.676,25.391) 62.676,25.347 63.495,24.528 v1(63.495,15.392)
CLK_PMIC: R142.2 U3.33 | length 42.1
  Top Layer w0.2: v1(69.173,51.502) 69.512,51.84 71.854,51.84 72.208,51.485 U3.33@73.324,51.485 ; R142.2@87.882,30.797 87.882,36.194 v1@87.902,36.214
  Sig4 w0.2: v1(69.173,51.502) 68.884,51.212 68.884,40.014 72.683,36.214 v1@87.902,36.214
  other v1: 87.902,36.114
CLKEPB: R135.1 U6.11 U7.13 | length 87.4
  Top Layer w0.2: U7.13@53.71,12.17 53.71,13.465 53.876,13.631 60.268,13.631 60.777,13.122 66.636,13.122 66.914,13.399 v1(68.08,13.399) ; R135.1@97.35,24.782 98.338,24.782 v1(98.355,24.765) ; v1(115.521,37.029) 116.076,37.029 117.306,38.259 U6.11@122.791,38.259
  Sig4 w0.2: v1(68.08,13.399) 91.571,13.399 91.952,13.781 91.952,22.273 94.445,24.765 v1(98.355,24.765) 103.9,24.765 115.521,36.386 v1(115.521,37.029)
COS_P1: J21.2 R121.1 U12.1 | length 90
  Top Layer w0.2: v1(86.899,4.365) 86.917,4.383 87.34,4.383 87.457,4.5 R121.1@87.457,5.2
  Top Layer w0.4: U12.1@29.2,46.775 29.465,46.775 29.49,46.75 v1(29.49,44.369) 29.49,44.342 30.01,43.822 J21.2@30.01,40.043
  Sig4 w0.2: v1(29.49,44.369) 42.095,44.369 58.92,27.544 58.92,14.703 69.258,4.365 v1(86.899,4.365)
COS_P2: J22.2 R125.1 U13.1 | length 85.3
  Top Layer w0.2: v1(77.301,6.654) 77.301,5.828 77.984,5.145 R125.1@84.456,5.145
  Top Layer w0.5: J22.2@45.272,45.963 45.272,43.771 v1(45.441,43.603)
  Sig4 w0.2: v1(45.441,43.603) 60.892,28.152 60.892,15.196 69.406,6.682 77.273,6.682 v1(77.301,6.654)
  Bottom Layer w0.2: U13.1@29.189,48.727 32.17,48.727 33.977,46.919 44.664,46.919 45.441,46.143 v1(45.441,43.603)
CUTOFF_ASCIN: Q6.2 R53.1 U14.84 | length 47.7
  Top Layer w0.2: Q6.2@41.175,40.216 40.611,40.216 40.45,40.377 40.45,41.316 41.054,41.92 43.212,41.92 44.494,40.638 R53.1@44.494,40.538 50.465,40.538 61.328,29.675 63.495,29.675 69.288,23.882 75,23.882 76.965,21.917 U14.84@77.827,21.917
Cutoff_EPB: Q6.3 R57.1 R85.1 | length 30.7
  Top Layer w0.3: Q6.3@41.175,40.866 R57.1@42.34,40.866
  Top Layer w0.5: R57.1@42.34,40.866 42.34,40.766 42.39,40.716 42.772,40.716 v1(43.329,40.159) ; R85.1@46.018,13.122 46.018,22.02 v1(46.077,22.079)
  Sig4 w0.2: v1(43.329,40.159) 46.077,37.412 v1(46.077,22.079)
DRVOFF_DRV3263: U5.9 U14.87 | length 36.3
  Top Layer w0.2: U5.9@43.993,25.115 43.993,24.023 v1(44.794,23.222) ; v1(54.429,23.267) 55.223,22.473 74.621,22.473 76.377,20.717 U14.87@77.827,20.717
  Bottom Layer w0.2: v1(44.794,23.222) 44.817,23.245 54.406,23.245 v1(54.429,23.267)
DRVOFF_EPB: R90.1 U14.2 | length 10
  Top Layer w0.2: R90.1@73.919,9.354 73.919,9.454 74.119,9.654 74.219,9.654 74.736,10.171 v1(76.052,10.171) ; v1(79.762,10.08) 79.762,11.48 80.102,11.82 U14.2@80.102,13.642
  Bottom Layer w0.2: v1(76.052,10.171) 76.103,10.12 79.722,10.12 v1(79.762,10.08)
EN_CAN1: R107.1 U14.13 | length 54.2
  Top Layer w0.2: v1(83.701,9.751) 84.262,10.312 84.502,10.552 U14.13@84.502,13.642 ; v1(115.827,22.706) 115.827,24.779 115.727,24.879 115.727,28.428 116.207,28.908 R107.1@118.393,28.908
  Sig4 w0.2: v1(83.701,9.751) 84.77,8.682 105.824,8.682 111.276,14.135 111.276,19.208 114.727,22.658 115.779,22.658 v1(115.827,22.706)
EN_CAN2: R117.1 U14.41 | length 43.2
  Top Layer w0.2: U14.41@91.177,21.517 93.938,21.517 94.975,22.554 v1(95.441,22.554)
  Top Layer w0.5: v1(119.637,44.506) 119.768,44.637 R117.1@120.936,44.637
  Sig4 w0.2: v1(95.441,22.554) 104.216,22.554 117.3,35.638 117.3,42.169 v1(119.637,44.506)
F29H85x_25MHZ_CLK: R137.2 U14.70 | length 2.9
  Top Layer w0.2: U14.70@81.702,26.992 81.702,28.005 82.316,28.62 R137.2@82.316,29.558 ; R137.2@82.458,29.558 R137.2@82.458,29.602
FB: C30.1 R33.2 R35.2 U2.3 | length 7.8
  Top Layer w0.25: C30.1@105.232,36.114 105.232,37.171 R33.2@105.377,37.316 R35.2@106.758,37.316 ; U2.3@106.002,42.181 106.002,41.154 106.227,40.929 106.227,37.747 R35.2@106.658,37.316
FORCE_SENSOR_SENT: C1.2 R1.1 R3.2 R128.2 R145.2 | length 36.6
  Top Layer w0.2: v1@80.798,6.155 v1(80.798,6.255) 80.798,7.99 R145.2@80.902,8.095 ; C1.2@101.681,11.6 C1.2@101.681,11.7
  Top Layer w0.6: R128.2@97.208,14.163 99.218,14.163 C1.2@101.681,11.7
  Top Layer w0.8: C1.2@101.681,11.6 102.281,11.6 R3.2@104.342,11.6
  Sig4 w0.2: v1(80.798,6.255) 84.652,6.255 84.727,6.18 v1(100.994,6.18)
  Bottom Layer w0.2: v1(100.994,6.18) 100.994,6.261 101.162,6.428 v1(101.162,12.219)
GHA: R50.2 TP10.1 U5.38 | length 45.1
  Top Layer w0.2: R50.2@37.556,70.011 37.556,69.365 37.834,69.087 37.834,65.573 39.893,63.515 39.893,52.289 ; v1(39.109,32.661) 39.109,32.664 38.177,33.596 38.177,49.577 39.893,51.293 39.893,52.289 ; TP10.1@42.847,52.26 39.922,52.26 39.893,52.289
  Top Layer w0.25: v1(38.512,31.543) 38.56,31.495 38.56,31.193 38.988,30.765 U5.38@39.343,30.765
  Bottom Layer w0.2: v1(38.512,31.543) 39.109,32.14 v1(39.109,32.661)
GHB: R66.2 TP12.1 U5.43 | length 62.3
  Top Layer w0.25: v1(36.094,28.967) 36.796,28.265 U5.43@39.343,28.265
  Top Layer w0.4: R66.2@18.997,71.338 20.598,71.338 20.693,71.243 v1(20.721,71.243)
  Top Layer w0.5: TP12.1@33.288,27.765 34.113,27.765 35.315,28.967 v1(36.094,28.967)
  Sig4 w0.2: v1(20.721,71.243) 21.345,71.243 23.73,68.858 23.73,63.676 23.847,63.559 26.173,63.559 27.64,62.092 27.64,53.552 23.6,49.513 23.6,42.443 36.05,29.993 36.05,29.011 v1(36.094,28.967)
GHC: R67.2 TP13.1 U5.48 | length 57.2
  Top Layer w0.25: v1(36.41,24.343) 36.447,24.343 37.869,25.765 U5.48@39.343,25.765
  Top Layer w0.3: R67.2@13.4,56.594 14.698,56.594 15.491,55.802 15.491,52.808 17.552,50.746 v1(18.295,50.746)
  Top Layer w0.5: TP13.1@29.137,24.965 31.762,24.965 33.227,23.5 35.794,23.5 36.41,24.117 v1(36.41,24.343)
  Sig4 w0.2: v1(18.295,50.746) 19.128,49.913 19.128,37.777 32.098,24.806 36.028,24.806 36.41,24.424 v1(36.41,24.343)
GLA: R55.2 TP11.1 U5.39 | length 35.2
  Top Layer w0.2: R55.2@38.299,57.684 38.299,56.97 38.399,56.87 v1(38.399,56.789) 38.399,56.78 38.141,56.522 38.141,51.778 36.361,49.999 36.361,33.322 37.111,32.572 37.111,31.494 38.34,30.265 U5.39@39.343,30.265 ; v1(40.862,55.465) 42.688,55.465 TP11.1@42.843,55.31
  Bottom Layer w0.2: v1(38.399,56.789) 39.273,56.789 40.27,55.792 40.453,55.792 40.78,55.465 v1(40.862,55.465)
GLB: R72.2 TP14.1 U5.42 | length 49.5
  Top Layer w0.2: R72.2@24.942,61.081 R72.2@24.942,61.181
  Top Layer w0.25: v1(32.281,29.496) 32.327,29.542 36.332,29.542 37.109,28.765 U5.42@39.343,28.765
  Top Layer w0.5: R72.2@24.942,61.181 25.759,61.181 v1(25.776,61.199) ; TP14.1@28.996,29.384 32.17,29.384 v1(32.281,29.496)
  Sig4 w0.2: v1(25.776,61.199) 25.776,60.568 25.984,60.36 25.984,54.033 21.988,50.037 21.988,40.48 31.728,30.74 31.925,30.74 32.318,30.348 32.318,29.532 v1(32.281,29.496)
GLC: R73.2 TP15.1 U5.1 | length 41
  Top Layer w0.25: v1(37.219,23.226) 39.108,25.115 U5.1@39.993,25.115
  Top Layer w0.5: v1(17.33,42.481) 17.33,42.86 17.939,43.469 R73.2@17.939,43.569 ; TP15.1@33.288,22.1 36.097,22.1 37.219,23.222 v1(37.219,23.226)
  Sig4 w0.2: v1(17.33,42.481) 17.33,42.417 16.971,42.058 16.971,37.092 17.332,36.732 31.038,23.026 36.788,23.026 36.793,23.031 36.943,23.031 37.138,23.226 v1(37.219,23.226)
GND: C1.1 C2.2 C3.1 C4.2 C5.2 C6.2 C7.1 C8.2 C9.1 C10.1 C12.1 C15.2 C16.2 C17.2 C18.2 C19.2 C21.2 C22.2 C23.1 C24.1 C25.2 C26.1 C27.2 C28.2 C29.1 C31.2 C32.2 C33.2 C34.2 C35.2 C36.2 C37.1 C40.2 C41.2 C42.2 C43.1 C44.1 C45.1 C46.1 C47.1 C48.2 C49.2 C50.2 C51.2 C52.2 C53.1 C54.1 C55.2 C56.2 C57.2 C58.1 C59.1 C60.2 C61.2 C62.2 C64.1 C68.2 C70.2 C71.2 C73.2 C74.2 C75.2 C76.2 C78.2 C79.2 C80.2 C83.2 C84.2 C85.2 C86.2 C87.2 C88.1 C89.1 C90.1 C91.1 C92.1 C93.1 C94.1 C95.2 C96.1 C97.2 C98.1 C99.1 C100.1 C101.2 C102.2 C103.2 C104.1 C105.2 C106.2 C107.2 C108.1 C109.2 C110.2 C111.2 C112.2 C113.2 C114.2 C116.2 C117.2 C118.1 C120.2 C121.2 C122.2 C123.2 C124.2 C125.2 C126.2 C127.2 C128.2 C129.2 C130.2 C131.2 C132.2 C133.2 C134.2 C135.2 C136.2 C137.2 C138.1 C139.2 C140.2 C141.2 C142.2 C143.2 C144.2 C145.2 C146.2 C147.2 C148.1 D1.1 D4.2 D5.3 D10.2 J4.1 J10.4 J13.1 J16.1 J21.4 J22.4 J23.4 Q6.1 Q12.2 R1.2 R2.1 R14.1 R17.1 R18.1 R20.1 R21.1 R29.1 R30.2 R34.1 R35.1 R47.1 R48.2 R49.1 R61.1 R80.1 R81.1 R95.1 R104.2 R114.2 R131.1 R136.2 R146.2 R149.1 R150.1 R155.2 R156.2 TP2.1 U1.7 U1.13 U2.9 U2.19 U2.21 U3.1 U3.2 U3.10 U3.12 U3.14 U3.19 U3.47 U3.48 U4.4 U5.10 U5.27 U5.49 U6.4 U6.13 U7.6 U8.2 U8.15 U9.3 U10.2 U10.15 U11.3 U12.2 U13.2 U14.15 U14.18 U14.32 U14.36 U14.69 U14.101 Y1.2 | length 100.9
  Top Layer w0.2: U5.10@44.493,25.115 44.493,26.765 v2(44.003,27.255) v2(42.743,28.515) v2(44.003,29.775) 44.493,30.265 U5.27@44.493,31.915 ; U14.69@82.102,26.992 82.102,22.717 v2(82.477,22.342) v2(83.827,20.992) U14.101@84.502,20.317 v2(85.177,19.642) U14.101@85.302,19.517 ; U14.15@85.302,13.642 85.302,14.412 85.452,14.563 U14.101@85.452,19.367 ; U14.18@86.502,13.642 86.502,14.49 86.352,14.64 86.352,18.467 U14.101@85.452,19.367 ; v2(86.527,18.292) 87.003,17.816 90.306,17.816 90.407,17.917 U14.32@91.177,17.917 ; U14.36@91.177,19.517 U14.101@85.302,19.517 ; U2.19@104.802,43.331 105.706,43.331 105.906,43.531 v1(105.987,43.531) ; v1(106.537,43.531) U2.21@106.788,43.28 ; U2.21@106.812,43.28 107.015,43.28 ; v1(107.087,43.531) 107.168,43.531 107.368,43.331 U2.9@108.202,43.331 ; U14.101@85.302,19.517 U14.101@85.452,19.367
  Top Layer w0.25: U1.13@109.586,69.689 109.586,70.686 110.105,71.206 v1(110.105,71.227) ; v2(124.181,39.009) 124.431,39.259 U6.4@125.571,39.259
  Top Layer w0.3: U3.48@73.324,43.985 74.668,43.985 75.168,44.485 ; U3.47@73.324,44.485 75.168,44.485 ; 79.064,49.377 79.173,49.485 U3.12@80.824,49.485 ; 79.064,50.433 79.117,50.485 U3.14@80.824,50.485 ; 79.064,52.985 U3.19@80.824,52.985 ; v1(79.274,48.535) 79.328,48.535 79.378,48.485 U3.10@80.824,48.485 ; U3.1@80.824,43.985 79.623,43.985 79.123,44.485 ; U3.2@80.824,44.485 79.123,44.485 ; U10.2@125.089,47.59 125.839,47.59 126.489,46.94 U10.15@126.489,46.29 ; 75.168,44.485 79.123,44.485
  Top Layer w0.4: v1@24.26,58.319 v1(24.295,58.284) ; R146.2@83.771,30.802 83.871,30.902 83.871,31.717 83.936,31.782 v1(83.936,31.809) ; R34.1@104.177,39.807 104.186,39.816 104.186,40.585 v1(104.195,40.593)
  Top Layer w0.5: C64.1@46.293,36.053 C64.1@46.368,36.128 ; v1(72.45,24.928) 72.523,24.928 72.969,24.482 R150.1@73.069,24.482 ; J10.4@74.149,27.835 74.535,27.835 J10.4@74.785,28.085 ; C121.2@81.735,34.57 C121.2@81.74,34.575 ; v1@94.89,40.927 v1(94.925,40.961) ; C148.1@97.263,20.67 C148.1@97.279,20.655 ; R131.1@97.279,19.516 R131.1@97.295,19.501 ; v1@98.17,19.501 98.179,19.491 v1(98.179,19.465) ; v1@98.219,17.8 v1(98.251,17.767) ; C25.2@99.125,42.274 C25.2@99.18,42.22 ; v1(100.361,30.767) 102.687,30.767 J23.4@102.694,30.76 ; C118.1@100.719,19.35 C118.1@100.766,19.396 ; C7.1@105.553,71.658 C7.1@105.581,71.63 ; C10.1@109.659,74.515 109.659,73.365 109.96,73.063 v1(109.96,73.051) ; v1@114.15,72.122 v1(114.169,72.102) ; v1@114.335,67.631 114.352,67.614 v1(114.357,67.614) ; v1@114.699,69.877 v1(114.718,69.858) ; v1@130.797,39.337 v1(130.893,39.433) ; v1@151.884,57.302 v1(151.919,57.337)
  Top Layer w0.8: v1(134.285,50.844) 135.572,50.844 C16.2@135.636,50.781
  Top Layer w1: C56.2@62.49,42.896 C56.2@62.561,42.967
  Top Layer w2: D1.1@154.229,79.61 154.309,79.53 156.823,79.53 v1(156.853,79.5)
  GND w1: 156.223,58.621 157.533,59.93 157.533,78.821 v1(156.853,79.5)
  other v1: 86.899,0.997 99.326,1.392 47.079,2.121 61.966,3.379 90.811,3.454 46.968,4.021 88.037,4.137 47.36,5.03 70.857,6.041 46.799,7.519 90.847,7.762 92.883,7.762 81.838,7.929 85.077,7.96 97.931,7.99 87.953,8.068 71.271,8.795 80.043,8.876 58.614,9.338 111.61,9.467 71.021,10.26 100.593,10.29 86.683,10.639 77.104,10.815 94.991,11.6 47.472,11.694 55.729,12.23 103.036,12.651 51.894,13.342 77.052,14.117 112.763,14.515 38.549,14.586 90.552,14.684 83.698,14.776 62.561,16.023 72.822,16.426 65.49,16.448 68.346,16.472 59.501,16.518 58.282,16.789 95.625,16.816 104.606,16.949 87.992,17.816 42.743,18.222 100.719,18.595 95.946,18.661 123.587,18.771 48.446,19.095 121.454,19.797 33.355,19.882 101.568,20.465 103.324,20.465 41.392,21.405 44.835,22.273 86.951,22.941 64.117,23.073 62.843,23.139 109.678,23.575 101.696,24.102 125.536,24.16 86.899,24.923 59.514,25.209 54.557,25.784 51.909,25.957 71.312,26.008 58.273,26.467 25.985,26.572 128.95,26.824 27.507,27.488 52.754,27.692 91.952,27.767 66.821,28.187 121.451,28.251 124.736,28.458 74.785,28.752 130.83,29.575 97.263,29.597 124.186,29.618 125.286,29.618 121.486,29.637 21.588,30.84 124.186,30.998 125.286,30.998 36.097,31.023 52.813,31.375 26.511,31.551 29.13,31.63 81.552,31.639 156.065,31.977 110.151,32.117 124.736,32.158 80.848,32.294 127.439,32.586 30.919,32.87 80.678,32.99 142.225,33.015 16.664,33.353 49.761,33.458 63.62,33.713 33.6,33.792 8.101,33.92 8.671,33.92 9.206,33.92 9.758,33.92 10.323,33.92 10.843,33.92 11.401,33.92 18.47,33.966 7.558,34.558 8.101,34.558 8.671,34.558 9.206,34.558 9.758,34.558 10.323,34.558 10.843,34.558 11.401,34.558 80.731,34.57 101.724,34.578 105.602,34.829 13.847,34.954 7.001,35.157 7.558,35.157 8.101,35.157 8.671,35.157 9.206,35.157 9.758,35.157 10.323,35.157 10.843,35.157 11.401,35.157 19.487,35.495 6.409,35.761 6.99,35.753 7.547,35.753 8.09,35.753 8.66,35.753 9.195,35.753 9.747,35.753 10.312,35.753 10.832,35.753 11.39,35.753 88.766,35.805 93.03,35.859 130.857,36.015 47.168,36.128 6.409,36.391 6.99,36.391 7.547,36.391 8.09,36.391 8.66,36.391 9.195,36.391 9.747,36.391 10.312,36.391 10.832,36.391 11.39,36.391 121.838,36.444 119.575,36.487 21.501,36.642 5.771,36.737 5.189,36.99 6.99,36.99 7.547,36.99 8.09,36.99 8.66,36.99 9.195,36.99 9.747,36.99 10.312,36.99 10.832,36.99 11.39,36.99 110.84,37.233 114.499,37.283 31.637,37.317 60.982,37.317 5.147,37.574 108.928,37.585 7.083,37.635 36.943,37.693 138.468,37.732 98.843,37.859 26.02,37.909 15.928,37.937 72.056,38.142 5.136,38.17 7.08,38.209 69.249,38.657 88.619,38.671 5.136,38.808 7.08,38.808 41.132,39.116 21.671,39.156 94.585,39.202 33.528,39.344 5.136,39.407 110.757,39.434 66.891,39.525 72.718,39.733 84.897,39.733 60.671,39.817 17.776,40.198 130.893,40.393 114.679,40.59 5.107,40.65 67.593,40.763 86.018,40.762 135.716,40.817 99.419,40.941 102.226,41.094 61.523,41.111 15.944,41.157 5.096,41.246 22.687,41.385 130.738,41.656 5.096,41.884 5.096,42.483 39.137,42.52 60.982,42.896 131.159,42.941 120.565,42.977 48.365,42.985 105.712,43.081 106.262,43.081 106.812,43.081 24.616,43.451 114.29,43.462 74.874,43.735 75.974,43.735 77.074,43.735 78.174,43.735 79.274,43.735 39.109,43.765 52.77,44.072 127.129,44.419 74.874,44.935 75.974,44.935 77.074,44.935 78.174,44.935 79.274,44.935 89.056,44.985 33.161,45.214 36.966,45.214 39.137,45.312 120.911,45.477 125.939,45.6 127.039,45.6 24.35,46.022 149.1,46.066 74.874,46.135 75.974,46.135 77.074,46.135 78.174,46.135 79.274,46.135 145.06,46.391 125.939,46.98 127.039,46.98 27.639,47.061 114.945,47.125 74.874,47.335 75.974,47.335 77.074,47.335 78.174,47.335 79.274,47.335 31.882,47.817 65.526,47.896 126.489,48.14 27.995,48.174 64.444,48.417 74.874,48.535 75.974,48.535 77.074,48.535 78.174,48.535 17.33,49.103 136.926,49.351 39.329,49.577 115,49.632 75.974,49.735 77.074,49.735 78.174,49.735 79.274,49.735 85.827,50.085 98.855,50.485 74.874,50.935 75.974,50.935 77.074,50.935 78.174,50.935 79.274,50.935 90.082,51.155 96.121,51.247 91.404,51.517 18.041,51.74 18.575,51.74 19.128,51.74 19.692,51.74 64.291,51.86 22.583,52.051 74.874,52.135 75.974,52.135 77.074,52.135 78.174,52.135 79.274,52.135 17.47,52.378 18.041,52.378 18.575,52.378 19.128,52.378 19.692,52.378 20.213,52.378 37.067,52.365 28.512,52.627 29.069,52.627 29.612,52.627 30.182,52.627 30.717,52.627 31.269,52.627 31.834,52.627 32.354,52.627 32.912,52.627 16.927,52.977 17.47,52.977 18.041,52.977 18.575,52.977 19.128,52.977 19.692,52.977 20.213,52.977 20.77,52.977 28.512,53.265 29.069,53.265 29.612,53.265 30.182,53.265 30.717,53.265 31.269,53.265 31.834,53.265 32.354,53.265 32.912,53.265 74.874,53.335 75.974,53.335 77.074,53.335 78.174,53.335 79.274,53.335 16.37,53.484 16.927,53.484 17.47,53.484 18.041,53.484 18.575,53.484 19.128,53.484 19.692,53.484 20.213,53.484 20.77,53.484 28.512,53.864 29.069,53.864 29.612,53.864 30.182,53.864 30.717,53.864 31.269,53.864 31.834,53.864 32.354,53.864 32.912,53.864 38.718,53.894 124.248,53.929 125.22,53.929 126.257,53.929 127.292,53.929 128.292,53.929 129.348,53.929 130.32,53.929 131.357,53.929 132.392,53.929 133.392,53.929 16.37,54.122 16.927,54.122 17.47,54.122 18.041,54.122 18.575,54.122 19.128,54.122 19.692,54.122 20.213,54.122 20.77,54.122 34.418,54.29 28.526,54.458 29.084,54.458 29.626,54.458 30.197,54.458 30.731,54.458 31.284,54.458 31.848,54.458 32.369,54.458 32.926,54.458 74.874,54.535 75.974,54.535 77.074,54.535 78.174,54.535 79.274,54.535 16.37,54.721 16.927,54.721 17.47,54.721 18.041,54.721 18.575,54.721 19.128,54.721 19.692,54.721 20.213,54.721 20.77,54.721 67.118,54.81 133.392,54.929 28.526,55.096 29.084,55.096 29.626,55.096 30.197,55.096 30.731,55.096 31.284,55.096 31.848,55.096 32.369,55.096 32.926,55.096 16.403,55.257 28.526,55.695 29.084,55.695 29.626,55.695 30.197,55.695 30.731,55.695 31.284,55.695 31.848,55.695 32.369,55.695 32.926,55.695 74.874,55.735 75.974,55.735 77.074,55.735 78.174,55.735 79.274,55.735 16.403,55.8 124.232,55.929 133.392,55.929 89.777,56.01 24.879,56.073 67.767,56.225 28.51,56.292 16.403,56.371 28.524,56.887 124.232,56.964 133.392,56.964 135.957,57.345 147.109,57.345 136.957,57.361 137.957,57.361 138.992,57.361 140.029,57.361 141.001,57.361 142.057,57.361 143.057,57.361 144.092,57.361 145.129,57.361 146.101,57.361 28.524,57.525 82.228,57.647 83.2,57.647 84.238,57.647 85.273,57.647 86.273,57.647 87.328,57.647 88.3,57.647 89.338,57.647 90.373,57.647 91.373,57.647 81.22,57.663 91.953,57.663 43.355,57.755 44.327,57.755 45.365,57.755 46.4,57.755 47.4,57.755 48.455,57.755 49.427,57.755 50.465,57.755 51.5,57.755 52.5,57.755 62.616,57.755 63.588,57.755 64.626,57.755 65.661,57.755 66.661,57.755 67.716,57.755 68.688,57.755 69.726,57.755 70.761,57.755 71.761,57.755 42.347,57.771 53.5,57.771 61.608,57.771 72.761,57.771 124.232,58.001 133.392,58.001 135.929,58.186 147.081,58.186 81.22,58.635 91.953,58.635 42.347,58.743 53.5,58.743 61.608,58.743 72.761,58.743 107.48,58.842 108.842,58.842 124.232,58.973 133.392,58.973 36.57,59.073 135.929,59.186 147.081,59.186 99.653,59.496 81.22,59.673 91.953,59.673 42.347,59.781 53.5,59.781 61.608,59.781 72.761,59.781 104.918,59.922 105.778,59.922 23.889,59.978 124.232,60.029 133.392,60.029 135.929,60.221 147.081,60.221 99.653,60.467 101.768,60.551 102.523,60.551 81.22,60.708 91.953,60.708 42.347,60.816 53.5,60.816 61.608,60.816 72.761,60.816 124.232,61.029 133.392,61.029 135.929,61.258 147.081,61.258 99.653,61.523 101.768,61.523 102.523,61.523 81.22,61.708 91.953,61.708 42.347,61.816 53.5,61.816 61.608,61.816 72.761,61.816 25.722,62.008 124.232,62.064 133.392,62.064 135.929,62.23 147.081,62.23 99.653,62.523 101.784,62.531 102.539,62.531 81.22,62.763 91.953,62.763 42.347,62.871 53.5,62.871 61.608,62.871 72.761,62.871 38.498,62.959 124.232,63.101 133.392,63.101 135.929,63.286 147.081,63.286 99.653,63.558 81.22,63.735 91.953,63.735 42.347,63.843 53.5,63.843 61.608,63.843 72.761,63.843 124.232,64.073 133.392,64.073 135.929,64.286 147.081,64.286 99.653,64.596 81.22,64.773 91.953,64.773 111.917,64.851 42.347,64.881 53.5,64.881 61.608,64.881 72.761,64.881 124.248,65.081 125.22,65.081 126.257,65.081 127.292,65.081 128.292,65.081 129.348,65.081 130.32,65.081 131.357,65.081 132.392,65.081 133.392,65.081 135.929,65.321 147.081,65.321 99.653,65.567 81.22,65.808 91.953,65.808 42.347,65.916 53.5,65.916 61.608,65.916 72.761,65.916 135.929,66.358 147.081,66.358 81.22,66.808 91.953,66.808 42.347,66.916 53.5,66.916 61.608,66.916 72.761,66.916 135.929,67.33 147.081,67.33 136.929,67.346 137.929,67.346 138.964,67.346 140.001,67.346 140.973,67.346 142.029,67.346 143.029,67.346 144.064,67.346 145.101,67.346 146.073,67.346 105.581,70.77 35.656,71.117 36.373,71.117 37.135,71.117 37.768,71.117
  other v2: 51.96,6.295 52.71,6.295 53.71,6.295 54.71,6.295 55.46,6.295 51.96,6.945 55.46,6.945 52.71,7.145 53.71,7.145 54.71,7.145 79.777,16.942 81.127,16.942 82.477,16.942 83.827,16.942 85.177,16.942 86.527,16.942 79.777,18.292 81.127,18.292 82.477,18.292 83.827,18.292 85.177,18.292 79.777,19.642 81.127,19.642 82.477,19.642 83.827,19.642 86.527,19.642 87.877,19.642 79.777,20.992 81.127,20.992 82.477,20.992 85.177,20.992 86.527,20.992 87.877,20.992 79.777,22.342 81.127,22.342 83.827,22.342 85.177,22.342 86.527,22.342 87.877,22.342 79.777,23.692 81.127,23.692 82.477,23.692 83.827,23.692 85.177,23.692 86.527,23.692 41.483,26.19 42.743,26.19 44.003,26.19 40.418,27.255 41.483,27.255 42.743,27.255 45.068,27.255 40.418,28.515 41.483,28.515 44.003,28.515 45.068,28.515 40.418,29.775 41.483,29.775 42.743,29.775 45.068,29.775 41.483,30.84 42.743,30.84 44.003,30.84 124.181,38.009 124.181,40.009
IMON_LM74930: C148.2 R18.2 U1.10 U14.35 | length 66.1
  Top Layer w0.2: U14.35@91.177,19.117 94.585,19.117 95.338,19.87 95.338,20.045 95.963,20.67 96.163,20.67 96.563,21.07 96.563,21.095 96.739,21.27 96.763,21.27 97.811,22.317 98.521,22.317 99.062,22.858 99.062,25.517 v1(98.686,25.892)
  Top Layer w0.25: v1(98.312,28.752) v1(98.312,35.681) ; U1.10@110.236,68.039 111.813,68.039 112.327,68.553 113.1,68.553 R18.2@113.135,68.589
  Sig4 w0.25: v1(98.312,35.681) 98.312,36.747 96.363,38.695 96.363,49.522 111.066,64.225 111.066,64.813 112.292,66.039 v1(112.292,68.518)
  Bottom Layer w0.2: v1(98.312,28.752) 98.312,26.296 98.686,25.921 v1(98.686,25.892)
IN1_EPB: R94.1 U14.98 | length 23.6
  Top Layer w0.2: R94.1@58.92,10.947 73.052,10.947 73.152,10.847 73.67,10.847 v1(73.702,10.815) ; v1(74.501,15.647) 75.171,16.317 U14.98@77.827,16.317
  Bottom Layer w0.2: v1(73.702,10.815) 74.501,11.614 v1(74.501,15.647)
IN2_EPB: R93.1 U14.11 | length 25.7
  Top Layer w0.2: R93.1@61.49,10.093 v1(67.671,10.093) ; v1(83.467,10.815) 83.467,10.896 83.702,11.131 U14.11@83.702,13.642
  Sig4 w0.2: v1(67.671,10.093) 68.234,9.53 80.682,9.53 81.967,10.815 v1(83.467,10.815)
INH_CAN: D6.1 D7.1 R19.1 R26.1 R36.1 R156.1 TP19.1 | length 87.5
  Top Layer w0.3: v1(110.919,62.15) R19.1@110.919,63.312 ; v1(114.613,28.275) 114.613,28.221 114.666,28.167 114.666,27.65 D6.1@114.816,27.5
  Top Layer w0.5: R36.1@84.709,46.441 86.412,46.441 v1(86.425,46.428)
  Top Layer w0.6: R156.1@109.767,25.78 110.931,25.78 111.283,25.429 111.283,25.354 111.872,24.765 TP19.1@112.697,24.765 112.56,24.903 112.56,26.962 113.098,27.5 D6.1@114.816,27.5 ; R26.1@110.661,41.634 111.614,41.634 v1(111.636,41.656) 114.851,41.656 116.116,42.922 D7.1@119.254,42.922 119.254,42.851 v1(120.515,41.591)
  Sig4 w0.3: v1(86.425,46.428) 88.009,46.428 v1(94.318,52.736) ; v1(108.945,52.816) 110.196,52.816 ; v1(110.919,62.15) 110.196,61.427 110.196,52.816 ; v1(111.636,41.656) 110.974,42.318 110.819,42.318 110.196,42.941 110.196,52.816 ; v1(114.613,28.275) 114.613,28.292 120.515,34.194 v1(120.515,41.591)
  Bottom Layer w0.3: v1(94.318,52.736) 95.59,54.008 107.822,54.008 108.379,53.452 108.379,53.382 v1(108.945,52.816)
Isense_EPB: C100.2 D12.2 R95.2 U7.2 U14.10 | length 45.5
  Top Layer w0.2: R95.2@49.669,11.694 v1(50.857,11.694) 51.381,11.17 U7.2@52.085,11.17 ; v1(59.653,7.359) 75.355,7.359 76.249,8.253 v1(77.202,8.253) ; D12.2@82.94,6.255 83.297,6.612 83.297,7.465 83.303,7.471 83.303,8.519 83.127,8.695 83.103,8.695 82.703,9.095 C100.2@82.703,9.195 82.708,9.201 v1(82.708,10.114) 82.708,10.902 83.302,11.496 U14.10@83.302,13.642
  Sig4 w0.2: v1(50.857,11.694) 55.318,11.694 v1(59.653,7.359) ; v1(77.202,8.253) 80.848,8.253 v1(82.708,10.114)
LED1: R152.2 U14.72 | length 3.7
  Top Layer w0.2: R152.2@79.123,29.593 79.667,29.593 80.902,28.357 U14.72@80.902,26.992
LED2: R151.2 U14.74 | length 4.4
  Top Layer w0.2: R151.2@77.631,29.573 77.631,29.473 78.15,28.953 78.152,28.953 78.212,28.893 79.561,28.893 80.102,28.352 U14.74@80.102,26.992
MCU_ERRORSTS: R134.1 R136.1 U3.18 | length 31.6
  Top Layer w0.2: U3.18@80.824,52.485 80.857,52.518 81.686,52.518 82.154,52.985 v1(84.058,52.985) ; v1(90.856,36.828) 90.847,36.819 90.847,32.257 91.186,31.918 91.186,30.839 R134.1@91.144,30.797 R136.1@92.357,30.797
  Sig4 w0.2: v1(84.058,52.985) 84.058,52.917 84.257,52.718 84.257,41.595 86.212,39.64 89.183,39.64 90.856,37.967 v1(90.856,36.828)
MCU_TCK: R139.1 U14.48 | length 11
  Top Layer w0.2: U14.48@91.177,24.317 92.863,24.317 94.274,25.729 94.274,27.168 94.827,27.721 98.686,27.721 99.479,28.513 R139.1@99.579,28.513
MCU_TMS: R138.1 U14.47 | length 7
  Top Layer w0.2: U14.47@91.177,23.917 93.106,23.917 94.836,25.647 94.827,25.657 94.827,26.687 95.178,27.039 R138.1@96.15,27.039 ; R138.1@96.069,26.914 R138.1@96.146,26.837
MOS_LM68645: R154.2 U14.64 | length 15
  Top Layer w0.2: U14.64@84.102,26.992 84.102,28.384 84.497,28.779 84.497,34.65 85.969,36.122 85.969,38.44 87.484,39.955 R154.2@88.103,39.955
nCS_DRV3263: U5.20 U14.99 | length 43.2
  Top Layer w0.2: U5.20@46.143,29.265 57.87,29.265 60.57,26.565 63.053,26.565 66.013,23.605 v1(66.013,23.532) ; v1(66.23,14.811) 75.013,14.811 76.119,15.917 U14.99@77.827,15.917
  Sig4 w0.2: v1(66.013,23.532) 66.013,23.451 66.23,23.234 v1(66.23,14.811)
NetC7_2: C7.2 D2.2 Q1.1 Q1.2 Q1.3 Q2.1 Q2.2 Q2.3 U1.2 U1.15 | length 20.2
  Top Layer w0.25: D2.2@106.371,64.098 106.892,64.62 v1(106.892,64.648) 106.892,64.716 107.293,65.117 107.293,65.123 107.586,65.416 U1.2@107.586,65.889 ; C7.2@107.157,71.658 v1(108.094,71.658) ; v1@108.097,71.61 108.586,71.121 U1.15@108.586,69.689
  Top Layer w0.5: v1(102.591,74.135) 102.591,73.536 102.884,73.243 105.863,73.243 106.903,72.202 106.903,71.883 107.128,71.658 C7.2@107.153,71.658 C7.2@107.157,71.658
  Sig4 w0.25: v1(106.892,64.648) 106.345,65.214 106.275,65.287 106.275,65.39 106.38,71.227 106.811,71.658 v1(108.094,71.658)
  other v1: 102.559,74.785 103.072,75.036 102.591,75.412 104.711,75.464 102.625,76.78 103.367,76.799 104.091,76.819 104.741,76.819 104.739,77.521 102.592,78.041 103.112,78.041 103.67,78.041 104.316,78.041 104.739,78.676 102.591,79.219 103.601,79.383 104.122,79.383 104.679,79.383 104.711,79.959 103.633,80.696 104.154,80.696 104.711,80.696 103.562,81.355 104.083,81.355 104.64,81.355 103.562,81.942 104.083,81.942 104.64,81.942
NetC11_1: C11.1 U1.23 | length 3.1
  Top Layer w0.2: C11.1@103.723,66.135 C11.1@103.823,66.135
  Top Layer w0.25: C11.1@103.823,66.135 104.663,66.135 105.568,67.039 U1.23@106.436,67.039
NetC11_2: C11.2 C12.2 D2.1 D10.1 R153.2 U1.22 | length 22.4
  Top Layer w0.25: C11.2@102.523,66.135 102.634,66.246 102.634,66.685 102.931,66.981 104.796,66.981 105.422,67.608 v1(105.422,67.614) 105.49,67.614 105.565,67.539 U1.22@106.436,67.539
  Top Layer w0.5: C11.2@102.523,66.135 102.523,63.925 103.213,63.235 103.829,63.235 104.122,62.942 C12.2@104.122,61.991 ; C12.2@104.122,61.741 C12.2@104.122,61.991 ; D2.1@104.171,64.098 104.894,64.098 105.435,63.558 105.435,62.558 D10.1@105.642,62.351 ; D10.1@105.704,62.291 104.422,62.291 C12.2@104.122,61.991
  Bottom Layer w0.5: v1(105.422,67.614) 105.551,67.614 106.371,68.434 106.371,72.963 106.866,73.459 R153.2@108.013,73.459
NetC13_1: C13.1 R10.1 U1.18 | length 4.8
  Top Layer w0.25: C13.1@103.849,70.633 104.558,70.633 105.501,69.689 U1.18@107.086,69.689
  Top Layer w0.6: C13.1@103.849,70.633 R10.1@103.849,71.845
NetC13_2: C13.2 C14.2 R7.3 U1.19 | length 11.1
  Top Layer w0.2: R7.3@100.462,70.413 100.464,70.415 v1(101.187,70.415) 101.187,70.368 101.407,70.148 101.407,68.669 101.767,68.309 102.04,68.309 102.56,67.789 C14.2@102.66,67.789 ; v1(102.487,69.895) 102.487,70.433 102.687,70.633 102.749,70.633 102.949,70.433 102.949,70.086 103.066,69.969 104.512,69.969 105.443,69.039 U1.19@106.436,69.039
  Sig4 w0.2: v1(101.187,70.415) 101.967,70.415 v1(102.487,69.895)
NetC14_1: C14.1 R11.1 U1.20 | length 4.1
  Top Layer w0.25: C14.1@103.849,67.789 C14.1@103.86,67.789 104.035,67.964 104.624,67.964 105.199,68.539 U1.20@106.436,68.539
  Top Layer w0.6: C14.1@103.849,67.789 R11.1@103.849,69.039
NetC15_1: C15.1 R12.1 R14.2 U1.4 | length 8.2
  Top Layer w0.25: R12.1@107.48,62.536 R14.2@107.48,61.004 108.292,61.004 C15.1@108.842,61.004 108.842,61.104 108.205,61.741 108.205,64.384 108.586,64.765 108.586,65.364 U1.4@108.586,65.889
NetC18_1: C18.1 R16.1 | length 1.5
  Top Layer w0.5: R16.1@110.596,72.122 C18.1@112.056,72.122
NetC19_1: C19.1 R21.2 U1.9 | length 2.9
  Top Layer w0.25: U1.9@110.236,67.539 110.886,67.539 111.251,67.174 111.736,67.174 R21.2@111.771,67.139 112.943,67.139 C19.1@112.947,67.135
NetC20_1: C20.1 U2.15 | length 1.2
  Top Layer w0.25: C20.1@105.815,45.711 105.827,45.711 106.002,45.536 U2.15@106.002,44.581
NetC29_2: C29.2 U2.4 | length 2.4
  Top Layer w0.25: U2.4@106.502,42.181 106.502,41.463 107.102,40.863 C29.2@107.102,40.002
NetC38_1: C38.1 L3.2 U3.3 U3.4 | length 6
  Top Layer w0.3: U3.3@80.824,44.985 81.802,44.985 82.282,44.985 82.316,44.952 ; U3.4@80.824,45.485 82.158,45.485 82.196,45.447 ; 82.274,44.203 82.356,44.121 84.525,44.121 84.702,44.298 C38.1@84.702,44.895
NetC38_2: C38.2 U3.5 | length 3
  Top Layer w0.3: U3.5@80.824,45.985 82.564,45.985 83.358,45.191 C38.2@83.458,45.191
NetC39_1: C39.1 L3.1 U3.45 U3.46 | length 4.7
  Top Layer w0.3: C39.1@71.536,45.191 C39.1@71.636,45.191 ; U3.46@73.324,44.985 71.841,44.985 C39.1@71.636,45.191 ; U3.45@73.324,45.485 71.931,45.485 C39.1@71.636,45.191
  Top Layer w0.6: 71.536,44.206 C39.1@71.536,45.191
NetC39_2: C39.2 U3.44 | length 3.4
  Top Layer w0.3: C39.2@70.336,45.191 70.436,45.191 70.586,45.341 70.586,45.441 71.131,45.985 U3.44@73.324,45.985
NetC53_2: C53.2 U3.39 | length 3.8
  Top Layer w0.3: v1(71.8,48.584) 71.854,48.584 71.953,48.485 U3.39@73.324,48.485
  Bottom Layer w0.5: C53.2@69.743,48.243 71.488,48.243 71.8,48.554 v1(71.8,48.584)
NetC54_2: C54.2 U3.40 | length 3.3
  Top Layer w0.3: C54.2@70.03,47.956 70.058,47.984 71.882,47.984 71.883,47.985 72.08,47.985 U3.40@73.324,47.985
NetC59_2: C59.2 U4.8 | length 1.7
  Top Layer w0.25: C59.2@62.957,38.549 63.057,38.549 63.241,38.365 U4.8@64.586,38.365
NetC62_1: C62.1 R51.1 U5.30 | length 57.9
  Top Layer w0.25: U5.30@42.993,31.915 42.993,33.168 43.218,33.393 43.218,35.263 43.32,35.365 43.32,36.076 v1(43.36,36.115) ; v1(59.085,37.517) 60.311,36.291 61.692,36.291 62.08,35.903 62.08,33.707 64.358,31.428 68.753,31.428 70.561,33.236 71.021,33.236 72.414,34.63 74.169,34.63 77.783,38.244 80.246,38.244 85.707,43.706 R51.1@86.852,43.706
  Bottom Layer w0.25: C62.1@44.569,36.218 44.569,37.202 44.884,37.517 v1(59.085,37.517)
  Bottom Layer w0.5: v1(43.36,36.115) 44.466,36.115 C62.1@44.569,36.218
NetC63_1: C63.1 R53.2 U5.29 | length 7.8
  Top Layer w0.2: U5.29@43.493,31.915 43.493,32.714 43.694,32.915 43.694,35.138 43.874,35.318 43.874,35.523 C63.1@44.494,36.143
  Top Layer w0.5: C63.1@44.494,36.143 R53.2@44.494,39.338
NetC63_2: C63.2 C64.2 R54.2 U5.28 | length 6.3
  Top Layer w0.2: U5.28@43.993,31.915 43.993,32.515 44.494,33.016 C63.2@44.494,34.543
  Top Layer w0.6: C63.2@44.494,34.543 44.539,34.498 46.248,34.498 C64.2@46.293,34.453 46.393,34.553 R54.2@47.888,34.553
NetC65_1: C65.1 U5.33 | length 2.7
  Top Layer w0.25: C65.1@41.443,34.57 41.493,34.52 U5.33@41.493,31.915
NetC65_2: C65.2 U5.32 | length 4.7
  Top Layer w0.25: C65.2@41.443,36.17 42.268,35.345 42.268,33.965 41.993,33.69 U5.32@41.993,31.915
NetC67_1: C67.1 Q6.4 U5.34 | length 11.5
  Top Layer w0.25: Q6.4@39.575,40.866 38.9,40.866 38.741,40.708 38.741,37.857 40.108,36.49 v1(40.108,35.268) 40.568,34.808 40.568,34.005 40.993,33.58 U5.34@40.993,31.915
  Bottom Layer w0.25: C67.1@40.033,36.143 40.108,36.068 v1(40.108,35.268)
NetC69_2: C69.2 R64.2 | length 1.7
  Bottom Layer w1: C69.2@35.619,32.186 R64.2@35.619,33.839
NetC72_2: C72.2 R65.2 | length 1.8
  Bottom Layer w0.2: R65.2@33.288,27.491 R65.2@33.352,27.427
  Bottom Layer w0.5: R65.2@33.288,27.491 33.32,27.523 33.32,29.113 C72.2@33.288,29.145
NetC77_2: C77.2 R68.2 | length 1.6
  Bottom Layer w0.5: R68.2@33.338,25.765 33.355,25.748 33.355,24.242 C77.2@33.372,24.225
NetC93_2: C93.2 R88.1 U6.3 | length 3.6
  Top Layer w0.25: U6.3@125.571,38.759 126.421,38.759 126.995,39.333 C93.2@127.655,39.333
  Top Layer w0.5: R88.1@127.659,38.105 C93.2@127.659,39.337
NetC95_1: C95.1 U6.7 | length 1.5
  Top Layer w0.25: U6.7@122.791,40.259 122.791,41.724 C95.1@122.816,41.749
NetC104_2: C104.2 R100.1 R103.2 | length 2.9
  Top Layer w0.5: R100.1@137.947,34.18 137.947,33.098 137.643,32.794 137.826,32.61 137.826,31.615 137.876,31.565 R103.2@137.976,31.565
NetC108_2: C108.2 R110.1 R113.2 | length 2.8
  Top Layer w0.5: C108.2@140.064,40.817 141.452,40.817 141.621,40.986 ; R110.1@141.618,41.634 141.621,41.63 141.621,40.986 ; R113.2@141.625,40.436 141.621,40.44 141.621,40.986
NetC116_1: C116.1 L7.2 U14.19 | length 5
  Top Layer w0.2: U14.19@86.902,13.642 v1(86.902,14.867)
  Bottom Layer w0.5: v1(86.902,14.867) 86.356,14.867 85.957,15.266 85.957,15.876 C116.1@85.843,15.989 87.309,15.989 L7.2@87.618,15.681
NetC117_1: C117.1 L8.2 U14.33 | length 3.4
  Top Layer w0.2: v1(90.057,18.595) 90.057,18.573 90.313,18.317 U14.33@91.177,18.317
  Bottom Layer w0.5: C117.1@88.989,18.723 89.116,18.595 v1(90.057,18.595) 90.18,18.473 L8.2@91.003,18.473
NetD3_1: D3.1 D11.3 | length 2
  Bottom Layer w0.5: D3.1@125.729,50.999 125.737,51.007 127.674,51.007 D11.3@127.681,51.014
NetD4_1: D4.1 R24.1 | length 2.1
  Top Layer w0.5: R24.1@91.665,41.317 91.684,41.298 91.684,39.221 D4.1@91.703,39.202
NetD6_2: D6.2 R102.2 | length 1.4
  Top Layer w0.5: D6.2@117.016,27.5 R102.2@118.393,27.5
NetD7_2: D7.2 R112.2 | length 1.4
  Top Layer w0.5: D7.2@121.454,42.922 121.66,43.127 R112.2@122.803,43.127
NetD8_2: D8.2 R151.1 | length 1.9
  Top Layer w0.6: D8.2@77.348,32.6 77.631,32.317 R151.1@77.631,30.773
NetD9_2: D9.2 R152.1 | length 1.9
  Top Layer w0.6: R152.1@79.123,30.793 D9.2@79.123,32.668
NetD13_1: D13.1 Q3.1 R28.1 | length 3
  Top Layer w0.5: v1(94.584,45.677) 94.584,46.241 94.634,46.291 Q3.1@94.699,46.291 ; Q3.1@95.026,46.255 95.076,46.305 R28.1@95.076,47.591
  Bottom Layer w0.5: v1(94.584,45.677) 94.589,45.681 D13.1@94.589,46.649
NetD13_2: D13.2 Q3.2 R23.2 | length 4
  Top Layer w0.5: Q3.2@94.875,44.366 94.949,44.441 95.53,44.441 v1(95.538,44.449) 95.949,44.449 96.5,43.898 R23.2@96.5,42.73
  Bottom Layer w0.5: D13.2@94.589,44.449 v1(95.538,44.449)
NetJ23_2: J23.2 R138.2 | length 5.9
  Top Layer w0.2: J23.2@101.927,25.68 J23.2@102.694,25.68
  Top Layer w0.6: R138.2@97.35,27.039 100.335,27.039 101.694,25.68 J23.2@101.927,25.68
NetJ23_3: J23.3 R139.2 | length 5
  Top Layer w0.6: R139.2@100.779,28.513 102.446,28.513 102.739,28.22 J23.3@105.694,28.22
NetL4_1: L4.1 U4.2 | length 3.5
  Top Layer w0.25: L4.1@65.176,34.394 65.176,35.604 65.786,36.214 U4.2@65.786,37.603
NetL5_3: L5.3 R98.2 U8.13 | length 8.2
  Top Layer w0.3: U8.13@126.136,31.608 127.677,31.608 128.877,32.808 130.472,32.808 130.676,33.012 L5.3@130.676,33.865
  Top Layer w0.5: L5.3@130.676,33.865 130.876,34.065 131.147,34.065 132.251,35.17 R98.2@132.351,35.17
NetL5_4: L5.4 R105.2 U8.12 | length 8.1
  Top Layer w0.3: U8.12@126.136,30.958 127.734,30.958 129.084,32.308 130.408,32.308 130.676,32.04 L5.4@130.676,31.365
  Top Layer w0.5: L5.4@130.676,31.365 130.901,31.365 132.201,30.065 132.201,30.047 132.251,29.997 R105.2@132.351,29.997
NetL6_3: L6.3 R109.2 U10.13 | length 11.9
  Top Layer w0.3: U10.13@127.889,47.59 129.959,47.59 131.598,49.228 134.051,49.228 134.3,48.98 134.3,48.071 134.627,47.743 L6.3@135.301,47.743
  Top Layer w0.5: L6.3@135.301,47.743 135.301,46.49 135.751,46.04 R109.2@136.492,46.04
NetL6_4: L6.4 R115.2 U10.12 | length 11.4
  Top Layer w0.3: U10.12@127.889,46.94 130.54,46.94 131.343,47.743 131.343,48.217 131.854,48.728 133.624,48.728 133.8,48.553 133.8,47.967 133.576,47.743 L6.4@132.801,47.743
  Top Layer w0.5: R115.2@131.455,46.092 132.275,46.092 132.793,46.611 132.793,47.736 L6.4@132.801,47.743
NetQ1_4: Q1.4 R9.2 | length 1.7
  Top Layer w0.5: Q1.4@103.849,76.136 103.865,76.136 103.91,76.091 R9.2@103.91,74.515
NetQ2_4: Q2.4 R8.2 | length 1.4
  Top Layer w0.4: R8.2@102.422,81.3 102.422,79.951 102.427,79.946 Q2.4@102.451,79.946
NetQ2_5: Q2.5 R7.2 U1.24 | length 11.8
  Top Layer w0.25: v1(104.95,65.566) 104.95,65.592 105.562,66.205 105.927,66.205 106.261,66.539 U1.24@106.436,66.539
  Sig4 w0.2: v1(101.078,73.875) 103.359,71.594 103.359,67.157 v1(104.95,65.566)
  other v1: 96.135,72.552 95.508,72.98 96.091,73.166 94.956,73.875 95.508,73.875 96.073,73.875 96.594,73.875 97.151,73.875 97.734,73.875 98.291,73.875 98.811,73.875 99.376,73.875 99.928,73.875 100.463,73.875 94.956,74.515 95.508,74.515 96.073,74.515 96.594,74.515 97.151,74.515 97.734,74.515 98.291,74.515 98.811,74.515 99.376,74.515 99.928,74.515 100.463,74.515 101.078,74.515 96.549,75.055 97.079,75.058 97.602,75.055 98.206,75.055 98.737,75.055 99.312,75.055 99.881,75.055 100.421,75.055 94.956,75.096 101.078,75.091 95.44,75.359 96.14,75.359 101.078,75.612 97.556,75.621 98.336,75.621 98.967,75.621 100.275,75.687 94.907,75.738 95.44,75.938 96.14,75.938 101.078,76.169 96.861,76.314 97.939,76.314 99.056,76.314 100.161,76.314 95.44,76.478 96.14,76.478 101.078,76.753 97.385,76.954 98.529,76.954 99.642,76.954 95.44,77.047 96.14,77.047 101.078,77.31 96.861,77.551 97.939,77.551 99.056,77.551 100.161,77.551 95.44,77.622 96.14,77.622 101.078,77.83 97.403,78.022 99.608,78.022 98.529,78.041 95.44,78.153 96.14,78.153 101.078,78.395 96.861,78.535 97.939,78.535 99.056,78.535 100.161,78.535 95.44,78.757 96.14,78.757 101.078,78.948 97.35,79.15 98.503,79.188 99.608,79.188 95.442,79.28 96.142,79.28 101.078,79.482 96.861,79.771 97.939,79.771 99.056,79.771 100.161,79.771 95.44,79.809 96.14,79.809 95.44,80.336 96.14,80.336 97.556,80.397 98.206,80.406 98.825,80.397 100.275,80.397 95.442,81.024 96.148,81.027 96.688,81.027 97.256,81.027 97.832,81.027 98.363,81.027 98.967,81.027 99.49,81.024 100.019,81.027 95.508,81.626 96.029,81.626 96.586,81.626 97.316,81.626 97.85,81.626 98.403,81.626 98.967,81.626 99.488,81.626 100.045,81.626 95.508,82.158 96.148,82.158 96.963,82.181 97.498,82.181 98.05,82.181 98.615,82.181 99.135,82.181 99.693,82.181
NetQ4_4: Q4.4 R50.1 R52.2 | length 3.8
  Top Layer w0.4: Q4.4@33.362,71.273 34.074,71.273 34.73,70.617 34.73,70.111 34.83,70.011 R52.2@34.93,70.011
  Top Layer w0.5: R52.2@34.93,70.011 R50.1@36.356,70.011
NetQ5_4: Q5.4 R55.1 R56.2 | length 5.6
  Top Layer w0.2: R56.2@37.441,62.627 37.441,62.527 37.641,62.327 37.665,62.327 38.299,61.694 R55.1@38.299,58.884
  Top Layer w0.5: Q5.4@36.092,62.777 37.391,62.777 37.441,62.727 R56.2@37.441,62.627
NetQ6_5: Q6.5 Q6.6 | length 0.7
  Top Layer w0.2: Q6.6@39.575,39.566 Q6.5@39.575,40.216
NetQ7_4: Q7.4 R66.1 R69.2 | length 2.8
  Top Layer w0.2: R66.1@17.776,71.317 R66.1@17.797,71.338
  Top Layer w0.4: Q7.4@15.308,70.763 15.603,70.763 15.956,71.117 16.466,71.117 16.566,71.217 R69.2@16.566,71.317
  Top Layer w0.5: R69.2@16.566,71.317 16.576,71.327 17.766,71.327 R66.1@17.776,71.317
NetQ8_4: Q8.4 R67.1 R70.2 | length 2.9
  Top Layer w0.5: Q8.4@9.511,56.952 9.535,56.976 10.676,56.976 R70.2@10.7,57 11.75,57 12.05,56.7 12.05,56.644 12.1,56.594 R67.1@12.2,56.594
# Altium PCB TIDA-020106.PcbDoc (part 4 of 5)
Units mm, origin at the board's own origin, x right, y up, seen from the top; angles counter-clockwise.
Board outline 158.53 x 83.25 mm, 6 copper layers (Top Layer, GND, Power, Sig4, GND (Mid4), Bottom Layer), stack 1.59 mm thick; 407 components, 254 nets, 1274 pads, 2396 vias.
Unrouted connection lines stored in the file: 294.

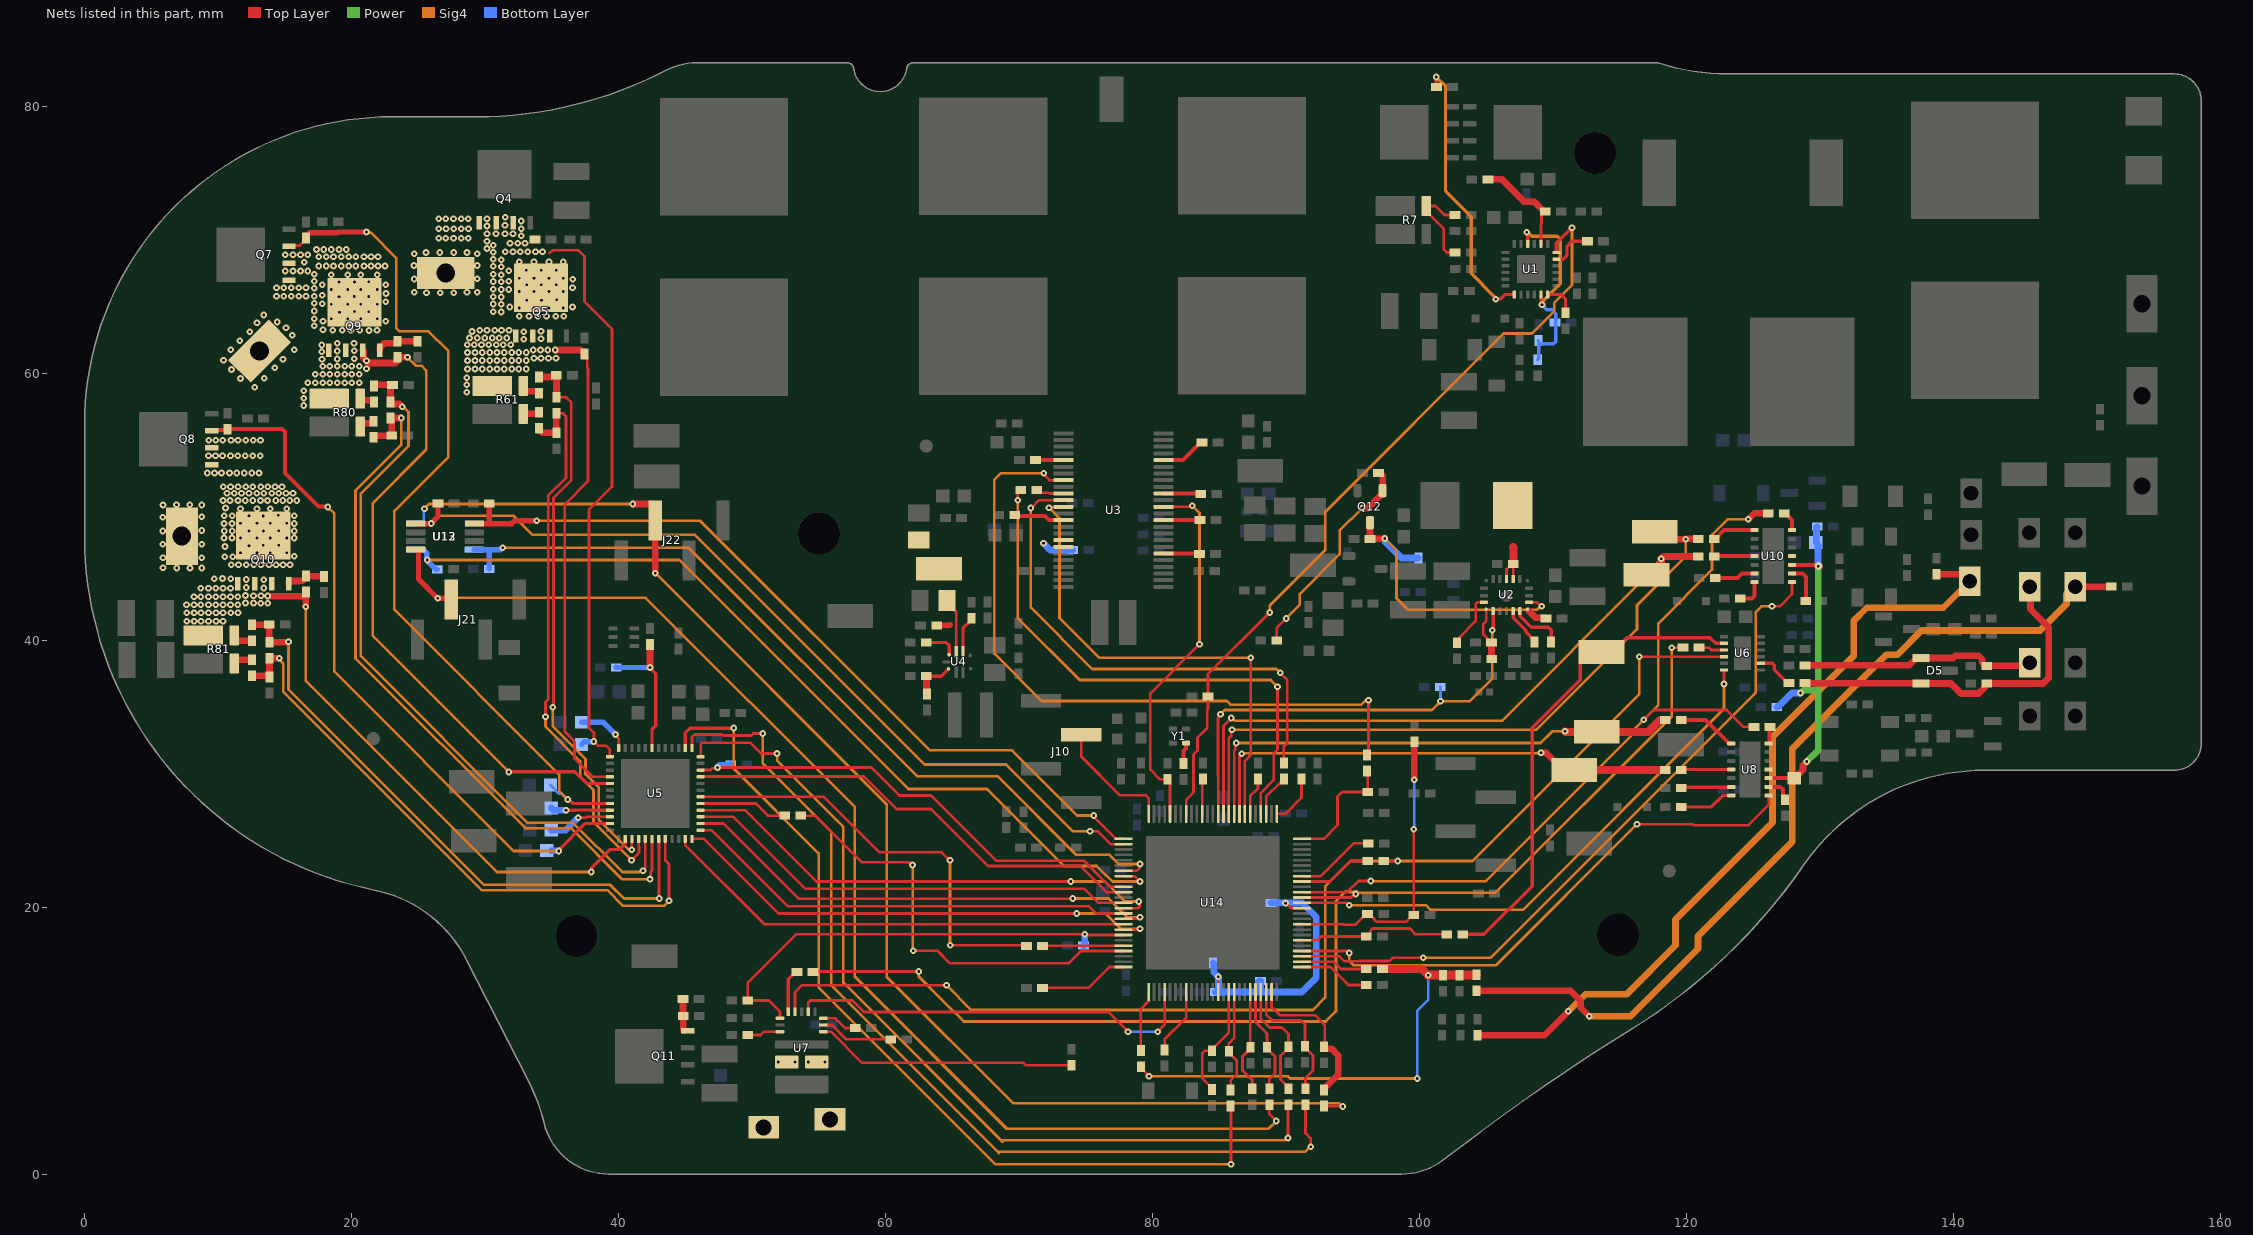
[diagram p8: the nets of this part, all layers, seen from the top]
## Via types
v1: diameter 0.5, hole 0.2, Top Layer to Bottom Layer, 2306 vias
v2: diameter 0.5, hole 0.2, Top Layer to Bottom Layer, tented both sides, 87 vias
v3: diameter 0.6, hole 0.2, Top Layer to Bottom Layer, 3 vias

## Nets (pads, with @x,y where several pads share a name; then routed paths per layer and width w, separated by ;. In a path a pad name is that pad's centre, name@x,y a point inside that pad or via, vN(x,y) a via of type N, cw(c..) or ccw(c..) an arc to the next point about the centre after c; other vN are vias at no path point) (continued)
NetQ9_4: Q9.4 R72.1 R74.2 | length 3.3
  Top Layer w0.2: R72.1@24.941,62.38 R72.1@24.942,62.381
  Top Layer w0.5: Q9.4@22.109,61.713 22.109,61.918 22.421,62.23 23.383,62.23 23.433,62.28 R74.2@23.433,62.38 ; R74.2@23.433,62.38 R72.1@24.941,62.381
NetQ10_4: Q10.4 R73.1 R75.2 | length 3.1
  Top Layer w0.5: Q10.4@15.286,44.226 15.286,44.386 15.331,44.431 16.053,44.431 16.08,44.458 16.316,44.458 16.566,44.708 R75.2@16.566,44.808 16.585,44.788 17.92,44.788 R73.1@17.939,44.769
NetQ11_4: Q11.4 R85.2 R87.2 | length 2.8
  Top Layer w0.2: R87.2@44.791,11.884 R87.2@44.826,11.849 ; R85.2@44.791,13.122 R85.2@44.791,13.222 ; Q11.4@44.931,10.735 Q11.4@45.163,10.735
  Top Layer w0.5: R87.2@44.791,11.884 44.803,11.884 44.818,11.899 R85.2@44.818,13.122 ; R87.2@44.826,11.849 44.826,10.866 44.931,10.761 Q11.4@44.931,10.735
NetQ12_1: Q12.1 R154.1 R155.1 | length 16.3
  Top Layer w0.2: R154.1@89.303,39.955 89.303,40.93 v1(89.992,41.619)
  Top Layer w0.5: v1(95.711,49.901) 96.127,49.901 97.225,50.998 97.225,52.317 97.011,52.531 R155.1@96.911,52.531
  Sig4 w0.2: v1(89.992,41.619) 91.027,42.654 91.027,43.471 94.007,46.451 94.007,48.196 v1(95.711,49.901)
NetQ12_3: Q12.3 R27.2 R28.2 U2.8 | length 22.8
  Top Layer w0.2: U2.8@108.202,42.831 108.802,42.831 109.106,42.527 v1(109.136,42.527)
  Top Layer w0.5: R28.2@96.276,47.591 Q12.3@96.275,48.798 ; R28.2@96.276,47.591 97.354,47.591 v1(97.376,47.614)
  Sig4 w0.2: v1(97.376,47.614) 98.262,46.727 98.262,43.137 99.125,42.274 108.802,42.274 109.055,42.527 v1(109.136,42.527)
  Bottom Layer w0.5: v1(97.376,47.614) 97.376,47.413 98.633,46.155 R27.2@99.9,46.155
NetR7_4: R7.4 R10.2 R11.2 | length 7.2
  Top Layer w0.2: R11.2@102.649,69.039 102.03,69.039 101.807,69.261 101.807,70.809 100.501,72.115 R7.4@100.501,72.515 101.181,72.515 101.851,71.845 R10.2@102.649,71.845
NetR8_1: R8.1 U1.1 | length 20.8
  Top Layer w0.25: v1(101.246,82.179) 101.246,81.428 R8.1@101.253,81.421 ; v1(105.703,65.532) 105.749,65.577 106.086,65.577 106.398,65.889 U1.1@107.086,65.889
  Sig4 w0.25: v1(101.246,82.179) 101.936,81.489 101.936,73.638 103.849,71.725 103.849,67.597 103.849,67.493 105.525,65.804 v1(105.703,65.532)
NetR9_1: R9.1 R16.2 U1.14 | length 7.7
  Top Layer w0.25: U1.14@109.086,69.689 109.086,71.183 109.121,71.218 109.121,71.947 R16.2@109.296,72.122
  Top Layer w0.5: R9.1@105.11,74.515 106.163,74.515 107.85,72.829 108.589,72.829 R16.2@109.296,72.122
NetR19_2: R19.2 U1.6 | length 2.5
  Top Layer w0.25: U1.6@109.586,65.889 110.596,65.889 110.919,65.566 R19.2@110.919,64.512
NetR20_2: R20.2 U1.11 | length 3.3
  Top Layer w0.25: U1.11@110.236,68.539 110.746,68.539 111.036,68.829 111.036,69.514 111.4,69.877 R20.2@112.571,69.877
NetR25_1: R25.1 U2.20 | length 4.1
  Top Layer w0.2: R25.1@102.802,39.807 103.002,40.007 103.002,40.235 104.195,41.428 104.195,42.714 104.312,42.831 U2.20@104.802,42.831
NetR26_2: R26.2 U2.7 | length 1.6
  Top Layer w0.2: U2.7@108.071,42.312 U2.7@108.171,42.312
  Top Layer w0.5: 108.171,42.189 108.677,41.684 109.411,41.684 R26.2@109.461,41.634
NetR29_2: R29.2 U2.6 | length 4
  Top Layer w0.25: U2.6@107.502,42.181 107.502,41.826 108.367,40.961 109.642,40.961 109.842,40.762 R29.2@109.842,39.859
NetR30_1: R30.1 U2.5 | length 3
  Top Layer w0.25: U2.5@107.002,42.181 107.002,41.689 107.939,40.752 107.939,40.618 108.598,39.959 R30.1@108.598,39.859
NetR36_2: R36.2 U3.6 | length 2.7
  Top Layer w0.3: U3.6@80.824,46.485 83.465,46.485 R36.2@83.509,46.441
NetR37_2: R37.2 U3.38 | length 3.8
  Top Layer w0.3: R37.2@69.652,49.363 69.717,49.298 71.935,49.298 72.247,48.985 U3.38@73.324,48.985
NetR38_2: R38.2 U3.11 | length 2.7
  Top Layer w0.3: U3.11@80.824,48.985 83.527,48.985 R38.2@83.546,49.005
NetR39_2: R39.2 U3.15 | length 2.8
  Top Layer w0.3: U3.15@80.824,50.985 83.543,50.985 R39.2@83.593,50.935
NetR40_2: R40.2 U3.20 | length 3.4
  Top Layer w0.3: U3.20@80.824,53.485 82.259,53.485 83.592,54.818 R40.2@83.692,54.818
NetR41_2: R41.2 U3.29 | length 2.1
  Top Layer w0.3: R41.2@71.217,53.485 U3.29@73.324,53.485
NetR42_2: R42.2 U3.34 | length 2.1
  Top Layer w0.2: R42.2@71.312,51.24 71.512,51.04 72.212,51.04 72.267,50.985 U3.34@73.324,50.985
NetR43_1: R43.1 U3.32 | length 52.6
  Top Layer w0.2: v1(71.841,52.505) 71.899,52.448 71.899,52.36 72.274,51.985 U3.32@73.324,51.985 ; R43.1@96.069,31.393 96.163,31.488 v1(96.163,35.502)
  Sig4 w0.2: v1(71.841,52.505) 68.632,52.505 68.143,52.016 68.143,38.985 71.686,35.442 85.557,35.442 85.83,35.169 95.623,35.169 95.899,35.445 96.106,35.445 v1(96.163,35.502)
NetR45_1: R45.1 U4.5 | length 2.8
  Top Layer w0.25: U4.5@65.786,39.128 65.786,40.883 66.439,41.536 R45.1@66.439,41.636
NetR46_1: R46.1 R48.1 U4.9 | length 3.2
  Top Layer w0.25: R48.1@63.042,37.294 64.146,37.294 U4.9@64.707,37.856
  Top Layer w0.5: R48.1@63.042,37.294 63.06,37.277 63.06,35.977 R46.1@63.077,35.959
NetR49_2: R49.2 U4.7 | length 2.5
  Top Layer w0.25: R49.2@62.992,39.817 64.534,39.817 64.748,39.603 U4.7@64.748,38.903
NetR57_2: R57.2 R58.1 U5.31 | length 10.6
  Top Layer w0.25: v1(42.347,37.949) 42.347,37.906 42.768,37.486 42.768,33.58 42.493,33.305 U5.31@42.493,31.915
  Top Layer w0.5: R57.2@42.34,39.666 42.34,37.956 v1(42.347,37.949)
  Bottom Layer w0.4: R58.1@39.812,37.959 39.817,37.954 42.342,37.954 v1(42.347,37.949)
NetR59_2: R59.2 U5.17 | length 6.7
  Top Layer w0.2: U5.17@46.143,27.765 50.274,27.765 51.184,26.855 R59.2@52.435,26.855
NetR60_2: R60.2 R61.4 | length 1.7
  Top Layer w0.3: R61.4@32.911,59.052 R61.4@32.911,59.057
  Top Layer w0.5: R61.4@32.863,59.052 32.863,58.752 32.963,58.652 33.999,58.652 34.049,58.602 R60.2@34.049,58.502
NetR61_3: R61.3 R63.2 | length 1.3
  Top Layer w0.5: R61.3@32.863,56.952 33.985,56.952 34.035,57.002 R63.2@34.035,57.078
NetR64_1: R64.1 U5.36 | length 4
  Top Layer w0.2: v1(39.768,32.924) 39.768,32.843 39.993,32.617 U5.36@39.993,31.915
  Bottom Layer w0.4: R64.1@37.219,33.839 38.853,33.839 v1(39.768,32.924)
NetR65_1: R65.1 U5.45 | length 4.5
  Top Layer w0.25: v1(36.05,27.265) 36.724,27.265 36.734,27.275 37.985,27.275 37.995,27.265 U5.45@39.343,27.265
  Bottom Layer w0.5: R65.1@34.952,27.427 35.114,27.265 v1(36.05,27.265)
NetR68_1: R68.1 U5.46 | length 4.8
  Top Layer w0.2: v1(36.972,26.7) 37.557,26.7 37.622,26.765 U5.46@39.343,26.765
  Bottom Layer w0.5: R68.1@34.938,25.765 36.038,25.765 v1(36.972,26.7)
NetR71_2: R71.2 U5.26 | length 67.7
  Top Layer w0.2: R71.2@85.843,5.102 85.862,5.083 v1(85.862,0.75)
  Top Layer w0.25: U5.26@44.993,31.915 44.993,33.054 45.349,33.411 v1(48.618,33.411)
  Sig4 w0.2: v1(48.618,33.411) 48.618,30.39 54.979,24.029 54.979,13.972 68.201,0.75 v1(85.862,0.75)
NetR76_2: R76.2 U5.25 | length 71.9
  Top Layer w0.2: U5.25@45.493,31.915 45.493,32.732 45.696,32.935 47.743,32.935 47.817,32.861 49.941,32.861 50.085,33.004 v1(50.799,33.004) ; R76.2@91.445,5.191 91.445,3.065 91.827,2.683 v1(91.827,2.045)
  Sig4 w0.2: v1(50.799,33.004) 50.799,30.759 55.929,25.629 55.929,14.117 68.472,1.574 ; 68.472,1.674 91.42,1.674 91.791,2.045 v1(91.827,2.045)
NetR77_2: R77.2 U5.24 | length 67
  Top Layer w0.2: U5.24@46.143,31.265 46.143,32.165 46.293,32.315 49.844,32.315 50.654,31.504 v1(51.856,31.504) ; v1(90.14,2.7) 90.14,5.156 R77.2@90.175,5.191
  Sig4 w0.2: v1(51.856,31.504) 51.889,31.471 51.889,30.954 56.828,26.016 56.828,14.357 68.758,2.427 ; 68.758,2.527 89.885,2.527 90.059,2.7 v1(90.14,2.7)
NetR78_2: R78.2 R80.4 | length 1.3
  Top Layer w0.3: R80.4@20.483,58.053 20.483,58.038 R80.4@20.54,57.981
  Top Layer w0.5: R80.4@20.645,58.085 20.645,58.062 20.745,57.962 21.61,57.962 21.66,57.912 R78.2@21.66,57.838
NetR79_2: R79.2 R81.4 | length 1.7
  Top Layer w0.3: R81.4@11.26,40.36 R81.4@11.26,40.413
  Top Layer w0.5: R81.4@11.195,40.36 11.195,40.057 11.295,39.957 R79.2@12.522,39.957
NetR80_3: R80.3 R82.2 | length 1.3
  Top Layer w0.5: R80.3@20.645,55.985 20.645,56.148 20.745,56.248 21.579,56.248 21.629,56.298 R82.2@21.629,56.398
NetR81_3: R81.3 R83.2 | length 1.6
  Top Layer w0.5: R81.3@11.195,38.26 11.195,38.437 11.295,38.537 R83.2@12.534,38.537
NetR84_1: R84.1 TP16.1 U6.8 | length 36.7
  Top Layer w0.25: R84.1@103.227,17.963 104.811,17.963 108.427,21.579 108.427,33.428 112.028,37.029 112.028,38.345 112.792,39.109 TP16.1@113.617,39.109 114.443,39.109 115.521,40.187 121.738,40.187 122.166,39.759 U6.8@122.791,39.759
NetR86_1: R86.1 U6.2 | length 2.9
  Top Layer w0.25: U6.2@125.571,38.259 126.41,38.259 126.556,38.112 126.556,37.79 127.559,36.787 R86.1@127.659,36.787
NetR89_2: R89.2 U6.9 | length 1.9
  Top Layer w0.2: R89.2@120.916,39.433 121.664,39.433 121.838,39.259 U6.9@122.791,39.259
Netr90_2: R90.2 U7.8 | length 19.6
  Top Layer w0.2: U7.8@55.335,10.67 55.901,10.67 58.238,8.333 70.331,8.333 70.51,8.154 R90.2@73.919,8.154
NetR91_1: R91.1 U7.3 | length 2.5
  Top Layer w0.2: R91.1@49.669,10.425 50.635,10.425 50.88,10.67 U7.3@52.085,10.67
NetR93_2: R93.2 U7.9 | length 5.4
  Top Layer w0.2: U7.9@55.335,11.17 55.967,11.17 57.044,10.093 R93.2@60.29,10.093
NetR94_2: R94.2 U7.10 | length 2.7
  Top Layer w0.2: U7.10@55.335,11.67 56.239,11.67 56.962,10.947 R94.2@57.72,10.947
NetR96_2: R96.2 U7.15 | length 3.3
  Top Layer w0.25: U7.15@52.71,12.17 52.71,14.591 53.26,15.141 R96.2@53.36,15.141
NetR101_2: R101.2 U8.1 | length 4.5
  Top Layer w0.3: R101.2@119.593,34.029 121.416,34.029 123.186,32.258 U8.1@123.336,32.258
NetR102_1: R102.1 U8.7 | length 4.1
  Top Layer w0.25: R102.1@119.593,27.5 121.841,27.5 122.699,28.358 U8.7@123.336,28.358
NetR104_1: R104.1 U8.9 | length 2
  Top Layer w0.3: U8.9@126.136,29.008 127.006,29.008 127.206,28.808 127.206,28.189 R104.1@127.356,28.039
NetR106_2: R106.2 U8.14 | length 1.3
  Top Layer w0.3: U8.14@126.136,32.258 126.186,32.258 126.186,33.458 R106.2@126.237,33.508
NetR107_2: R107.2 U8.6 | length 3.8
  Top Layer w0.25: R107.2@119.593,28.908 119.668,28.983 123.311,28.983 U8.6@123.336,29.008
NetR108_2: R108.2 U8.4 | length 3.8
  Top Layer w0.25: R108.2@119.593,30.264 119.637,30.308 U8.4@123.336,30.308
NetR111_2: R111.2 U10.1 | length 3.4
  Top Layer w0.3: R111.2@122.054,47.591 122.154,47.591 122.803,48.24 U10.1@125.034,48.24 ; U10.1@125.084,48.24 U10.1@125.034,48.24 ; U10.1@125.089,48.24 U10.1@125.034,48.24
NetR112_1: R112.1 U10.7 | length 2.2
  Top Layer w0.3: R112.1@124.003,43.127 124.905,43.127 125.089,43.311 U10.7@125.089,44.34
NetR114_1: R114.1 U10.9 | length 2.9
  Top Layer w0.3: U10.9@127.884,44.99 U10.9@127.889,44.99 128.663,44.99 128.919,44.734 R114.1@128.919,42.941
NetR116_2: R116.2 U10.14 | length 1.6
  Top Layer w0.3: R116.2@127.302,49.501 127.402,49.501 127.889,49.014 U10.14@127.889,48.24
NetR117_2: R117.2 U10.6 | length 3.1
  Top Layer w0.3: R117.2@122.136,44.637 123.794,44.637 124.148,44.99 U10.6@125.089,44.99
NetR118_2: R118.2 U10.4 | length 3
  Top Layer w0.3: R118.2@122.073,46.264 122.099,46.29 U10.4@125.084,46.29
NetR128_1: R128.1 U14.26 | length 5.4
  Top Layer w0.2: U14.26@91.177,15.517 93.301,15.517 94.655,14.163 R128.1@96.008,14.163
NetR129_1: R129.1 U14.27 | length 5.1
  Top Layer w0.2: U14.27@91.177,15.917 93.542,15.917 94.092,15.367 R129.1@96.008,15.367
NetR133_2: R133.2 U14.42 | length 5.6
  Top Layer w0.2: U14.42@91.177,21.917 93.293,21.917 94.828,23.452 R133.2@96.115,23.452
NetR134_2: R134.2 U14.51 | length 3.7
  Top Layer w0.2: U14.51@89.302,26.992 89.937,26.992 91.144,28.199 R134.2@91.144,29.597
NetR135_2: R135.2 U14.43 | length 6
  Top Layer w0.2: U14.43@91.177,22.317 92.589,22.317 95.054,24.782 R135.2@96.15,24.782
NetR137_1: R137.1 Y1.3 | length 1.6
  Top Layer w0.3: R137.1@82.316,30.758 82.316,31.701 82.48,31.864 82.48,32.267 Y1.3@82.502,32.289
NetR140_1: R140.1 U14.53 | length 3.2
  Top Layer w0.2: U14.53@88.502,26.992 88.502,28.272 89.527,29.297 89.627,29.297 89.827,29.497 R140.1@89.827,29.597
NetR141_2: R141.2 U14.96 | length 6.1
  Top Layer w0.2: R141.2@71.749,16.988 71.878,17.117 U14.96@77.827,17.117
NetR142_1: R142.1 U14.56 | length 2.8
  Top Layer w0.2: U14.56@87.302,26.992 87.302,28.317 87.882,28.897 R142.1@87.882,29.597
NetR143_2: R143.2 U14.100 | length 6.7
  Top Layer w0.2: R143.2@71.749,13.958 75.197,13.958 76.756,15.517 U14.100@77.827,15.517
NetR144_1: R144.1 U14.1 | length 4.6
  Top Layer w0.2: R144.1@79.11,9.254 79.11,12.357 79.702,12.949 U14.1@79.702,13.642
NetR145_1: R145.1 U14.8 | length 5
  Top Layer w0.2: R145.1@80.902,9.295 80.902,10.105 82.502,11.705 U14.8@82.502,13.642
NetR146_1: R146.1 U14.65 | length 2.6
  Top Layer w0.2: U14.65@83.702,26.992 83.702,29.533 R146.1@83.771,29.602
NetU8_11: U8.11
NetU10_11: U10.11
nFAULT_CAN1: U8.8 U14.29 | length 41.5
  Top Layer w0.2: U14.29@91.177,16.717 94.522,16.717 94.672,16.567 v1(94.732,16.567) ; v1(116.277,26.217) 120.45,26.217 120.53,26.136 124.622,26.136 126.136,27.65 U8.8@126.136,28.358
  Sig4 w0.2: v1(94.732,16.567) 94.732,15.967 95.052,15.647 105.707,15.647 v1(116.277,26.217)
nFAULT_CAN2: U10.8 U14.28 | length 52.7
  Top Layer w0.2: U14.28@91.177,16.317 94.001,16.317 94.375,15.943 95.459,15.943 95.483,15.967 97.726,15.967 97.955,16.197 v1(100.254,16.197) ; v1(126.386,42.527) 126.973,42.527 127.889,43.442 U10.8@127.889,44.34
  Sig4 w0.2: v1(100.254,16.197) 105.297,16.197 125.181,36.081 125.181,42.122 125.586,42.527 v1(126.386,42.527)
nFAULT_EPB: C99.2 R92.2 U7.1 U14.94 | length 35.2
  Top Layer w0.2: U7.1@52.085,11.67 52.085,12.17 51.249,13.005 R92.2@49.669,13.005 49.669,14.362 53.27,17.963 v1(74.9,17.963) 74.946,17.917 U14.94@77.827,17.917
  Bottom Layer w0.5: C99.2@74.821,17.117 74.85,17.117 74.9,17.167 v1(74.9,17.963)
nFLT_DRV3263: R62.1 U5.22 U14.85 | length 36.9
  Top Layer w0.2: U5.22@46.143,30.265 46.885,30.265 47.026,30.406 47.258,30.406 47.336,30.485 v1@47.336,30.524 ; v1@47.299,30.562 v1@47.336,30.524 ; v1(47.396,30.464) v1@47.336,30.524 ; U14.85@77.827,21.517 76.799,21.517 74.834,23.482 68.272,23.482 63.389,28.365 61.024,28.365 58.925,30.464 47.472,30.464 47.394,30.542 47.336,30.599 v1@47.336,30.524
  Bottom Layer w0.5: v1(47.396,30.464) 47.564,30.632 48.354,30.632 R62.1@48.404,30.682
nFLT_LM74930: R15.1 U1.12 U14.68 | length 59.5
  Top Layer w0.2: U14.68@82.502,26.992 82.502,28.036 83.058,28.593 83.058,31.421 83.356,31.718 83.356,32.693 84.097,33.435 84.097,34.815 84.146,34.865 R15.1@84.146,35.77 84.146,37.449 v1(88.767,42.069)
  Top Layer w0.25: U1.12@110.236,69.039 110.236,69.729 v1(111.406,70.898)
  Sig4 w0.2: v1(88.767,42.069) 88.767,42.6 92.924,46.757 92.924,49.599 106.287,62.962 108.4,62.962 110.086,64.648 110.086,65.283 111.406,66.602 v1(111.406,70.898)
nSCS_EPB: U7.12 U14.4 | length 31.1
  Top Layer w0.2: U7.12@54.21,12.17 54.21,12.857 54.352,12.999 57.519,12.999 58.38,12.139 76.679,12.139 v1(78.148,10.67) ; v1(80.381,10.67) 80.902,11.191 U14.4@80.902,13.642
  Bottom Layer w0.2: v1(78.148,10.67) v1(80.381,10.67)
nSCS_PMIC: U3.36 U14.57 | length 37.1
  Top Layer w0.2: v1(72.227,49.918) 72.26,49.952 73.29,49.952 U3.36@73.324,49.985 ; U14.57@86.902,26.992 86.902,30.947 87.216,31.26 87.216,31.269 87.352,31.406 v1(87.352,38.671)
  Sig4 w0.2: v1(72.227,49.918) 73.024,49.12 73.024,41.665 76.019,38.671 v1(87.352,38.671)
nSCS_WSS: U6.12 U14.38 | length 41
  Top Layer w0.2: U14.38@91.177,20.317 94.481,20.317 94.651,20.148 v1(94.732,20.148) ; v1(122.791,36.718) U6.12@122.791,37.759
  Sig4 w0.2: v1(94.732,20.148) 100.474,20.148 100.825,19.797 107.729,19.797 122.791,34.859 v1(122.791,36.718)
nSLEEP_DRV3263: U5.21 U14.86 | length 35.3
  Top Layer w0.2: U5.21@46.143,29.765 46.166,29.789 58.367,29.789 60.801,27.355 63.398,27.355 67.671,23.082 74.586,23.082 76.551,21.117 U14.86@77.827,21.117
nSTB_CAN: R106.1 R116.1 U14.40 | length 61.1
  Top Layer w0.2: U14.40@91.177,21.117 94.57,21.117 95.412,21.96 v1(96.339,21.96) ; v1(116.778,34.029) 117.519,34.77 122.995,34.77 124.257,33.508 R106.1@125.037,33.508
  Top Layer w0.5: v1(124.61,49.043) 125.068,49.501 R116.1@126.102,49.501
  Sig4 w0.2: v1(96.339,21.96) 96.364,21.934 104.933,21.934 116.127,33.129 116.127,33.378 v1(116.778,34.029) 117.876,35.127 117.876,41.262 121.888,45.274 121.888,47.89 123.041,49.043 v1(124.61,49.043)
nXRS_DSP: C120.1 U3.13 U14.71 | length 27.9
  Top Layer w0.2: U3.13@80.824,49.985 82.82,49.985 82.893,50.059 v1(82.974,50.059) ; U14.71@81.302,26.992 81.302,29.265 81.1,29.467 C120.1@81.1,29.567 80.561,29.567 79.823,30.305 79.823,36.018 v1(83.502,39.698)
  Sig4 w0.2: v1(82.974,50.059) 83.502,49.531 v1(83.502,39.698)
OUTA_EPB: J5.1 U7.7
  other v2: 54.21,8.395 55.46,8.395
OUTB_EPB: J6.1 U7.5 | length 0.6
  Top Layer w0.2: v2(51.96,8.395) U7.5@52.585,8.395
  other v2: 53.21,8.395
OV: C17.1 R13.1 R17.2 U1.5 U1.16 | length 16.4
  Top Layer w0.25: v1(108.011,70.558) 108.011,70.49 108.086,70.415 U1.16@108.086,69.689 ; U1.5@109.086,65.889 109.086,65.254 109.161,65.179 v1(109.161,65.111)
  Sig4 w0.25: v1(108.011,70.558) 108.078,70.558 108.384,70.253 110.32,70.253 110.524,70.049 110.524,66.695 109.218,65.388 109.218,65.345 109.209,65.336 109.209,65.159 v1(109.161,65.111)
  Bottom Layer w0.25: C17.1@108.842,61.004 108.921,61.083 108.921,62.406 R13.1@108.886,62.441 108.886,62.371 109.061,62.196 110.048,62.196 110.197,62.345 110.197,63.719 R17.2@110.14,63.775 110.197,63.832 110.197,64.451 109.913,64.735 109.516,64.735 109.161,65.089 v1(109.161,65.111)
PEDAL_SENSOR_SENT: C2.1 R2.2 R4.2 R129.2 R144.2 | length 36.5
  Top Layer w0.2: R144.2@79.11,8.054 79.11,7.954 79.722,7.342 v1(79.722,7.334)
  Top Layer w0.6: R129.2@97.208,15.367 100.166,15.367 v1(100.63,14.903)
  Top Layer w0.7: v1(100.63,14.903) 100.646,14.919 104.24,14.919 R4.2@104.256,14.935
  Sig4 w0.2: v1(79.722,7.334) 90.115,7.334 90.286,7.163 v1(99.82,7.163)
  Bottom Layer w0.2: v1(99.82,7.163) 99.82,12.244 100.63,13.055 v1(100.63,14.903)
PFS: J12.1 R3.1 R5.2 | length 60.1
  Top Layer w0.5: R3.1@104.342,10.4 109.335,10.4 v1(111.138,12.203) ; R5.2@138.715,44.94 140.66,44.94 J12.1@141.2,44.4
  Sig4 w0.5: v1(111.138,12.203) 112.404,13.469 115.486,13.469 119.162,17.144 119.162,19.066 126.429,26.333 126.429,32.738 132.5,38.809 132.5,41.431 133.49,42.421 139.221,42.421 J12.1@141.2,44.4
PG_LM68645: R31.2 U2.2 U14.62 | length 35.2
  Top Layer w0.2: U14.62@84.902,26.992 84.902,29.883 84.897,29.888 84.897,34.191 85.075,34.368 v1(85.075,34.45)
  Top Layer w0.25: v1(105.422,40.728) 105.422,40.796 105.502,40.876 U2.2@105.502,42.181
  Sig4 w0.2: v1(85.075,34.45) 85.395,34.769 100.913,34.769 v1(101.555,35.412) 103.73,35.412 105.422,37.104 v1(105.422,40.728) v1@105.433,40.717
  Bottom Layer w0.2: R31.2@101.533,36.505 101.555,36.483 v1(101.555,35.412)
PMIC_DIAG_OUT: C55.1 R43.2 U14.50 | length 9
  Top Layer w0.2: U14.50@91.177,25.117 92.825,25.117 93.843,26.136 93.843,28.273 94.191,28.621 C55.1@96.104,28.621 96.108,28.625 R43.2@96.108,30.021
PTS: J14.1 R4.1 R6.1 | length 67
  Top Layer w0.5: R4.1@104.256,13.735 111.289,13.735 112.062,12.962 112.062,12.461 v1(112.695,11.828) ; J14.1@149,44 R6.1@151.8,44
  Sig4 w0.5: v1(112.695,11.828) 115.783,11.828 120.839,16.884 120.839,17.832 127.898,24.89 127.898,31.856 134.937,38.895 135.769,38.895 137.599,40.724 146.472,40.724 148.45,42.703 148.45,43.45 J14.1@149,44
PWMAH: U5.11 U14.92 | length 35.8
  Top Layer w0.2: U5.11@44.993,25.115 44.993,24.632 50.907,18.717 U14.92@77.827,18.717
PWMAL: U5.12 U14.93 | length 37.6
  Top Layer w0.2: U5.12@45.493,25.115 46.391,25.115 51.988,19.517 v1(74.301,19.517) ; U14.93@77.827,18.317 78.896,18.317 78.971,18.392 v1(79.052,18.392)
  Sig4 w0.2: v1(74.301,19.517) 76.474,19.517 77.599,18.392 v1(79.052,18.392)
PWMBH: U5.13 U14.90 | length 34.3
  Top Layer w0.2: U5.13@46.143,25.765 46.958,25.765 52.656,20.067 75.203,20.067 75.753,19.517 U14.90@77.827,19.517
PWMBL: U5.14 U14.91 | length 37.1
  Top Layer w0.2: U5.14@46.143,26.265 47.839,26.265 53.469,20.635 74.009,20.635 v1(74.014,20.641) ; U14.91@77.827,19.117 78.935,19.117 79.063,19.246 v1(79.043,19.246)
  Sig4 w0.2: v1(74.014,20.641) 76.683,20.641 78.079,19.246 v1(79.043,19.246)
PWMCH: U5.15 U14.88 | length 34.4
  Top Layer w0.2: U5.15@46.143,26.765 48.587,26.765 53.985,21.367 74.879,21.367 75.929,20.317 U14.88@77.827,20.317
PWMCL: U5.16 U14.89 | length 37.3
  Top Layer w0.2: U5.16@46.143,27.265 49.457,27.265 54.805,21.917 v1(73.868,21.917) ; U14.89@77.827,19.917 78.902,19.917 79.027,20.042 79.027,20.207 79.006,20.228 79.006,20.369 v1(78.949,20.426)
  Sig4 w0.2: v1(73.868,21.917) 76.431,21.917 77.921,20.426 v1(78.949,20.426)
RX_CAN1: R108.1 TP22.1 U14.58 | length 36.9
  Top Layer w0.2: U14.58@86.502,26.992 86.502,31.324 v1(86.666,31.488) ; TP22.1@111.582,30.264 TP22.1@111.926,30.264
  Top Layer w0.5: v1(109.086,31.565) 109.456,31.565 110.757,30.264 TP22.1@111.582,30.264
  Top Layer w0.6: TP22.1@111.926,30.264 R108.1@118.393,30.264
  Sig4 w0.2: v1(86.666,31.488) 86.704,31.527 109.047,31.527 v1(109.086,31.565)
RX_CAN2: R118.1 TP23.1 U14.61 | length 49.7
  Top Layer w0.2: U14.61@85.302,26.992 85.302,30.049 85.297,30.054 85.297,33.578 v1(85.887,34.168)
  Top Layer w0.5: v1(118.092,46.092) 118.264,46.264 R118.1@120.873,46.264
  Top Layer w0.6: TP23.1@116.995,44.895 117.503,44.895 118.092,45.484 v1(118.092,46.092)
  Sig4 w0.2: v1(85.887,34.168) 85.936,34.168 86.154,33.95 106.155,33.95 116.778,44.573 116.778,44.778 v1(118.092,46.092)
SDI_DRV3263: R141.1 U5.18 | length 32.8
  Top Layer w0.2: U5.18@46.143,28.265 55.372,28.265 59.533,24.103 64.185,24.103 64.769,23.519 v1(64.821,23.519) ; v1(64.825,17.133) 70.51,17.133 R141.1@70.549,17.094
  Sig4 w0.2: v1(64.821,23.519) 64.823,23.517 64.823,17.135 v1(64.825,17.133)
SDI_PMIC: R140.2 U3.35 | length 37.9
  Top Layer w0.2: v1(70.873,49.901) 70.912,49.901 71.497,50.485 U3.35@73.324,50.485 ; v1(89.551,37.552) 90.082,37.021 90.082,32.294 89.827,32.04 R140.2@89.827,30.797
  Sig4 w0.2: v1(70.873,49.901) 70.873,42.43 75.467,37.836 89.267,37.836 v1(89.551,37.552)
SDIEPB: R133.1 U6.10 U7.14 | length 90.6
  Top Layer w0.2: U7.14@53.21,12.17 53.21,13.619 53.743,14.152 v1(64.549,14.152) ; R133.1@97.315,23.452 v1(98.361,23.452) ; v1(116.449,38.759) U6.10@122.791,38.759
  Sig4 w0.2: v1(64.549,14.152) 66.405,12.297 91.992,12.297 92.923,13.227 92.923,21.547 94.828,23.452 v1(98.361,23.452) 103.95,23.452 116.455,35.957 116.455,38.752 v1(116.449,38.759)
SDO_DRV3263: R59.1 U14.97 | length 32.9
  Top Layer w0.2: R59.1@53.635,26.855 54.713,26.855 58.211,23.356 61.741,23.356 61.942,23.155 v1(62.008,23.155) ; v1(62.054,16.725) 63.899,16.725 64.832,15.792 73.702,15.792 74.627,16.717 U14.97@77.827,16.717
  Sig4 w0.2: v1(62.008,23.155) 62.031,23.132 62.031,16.748 v1(62.054,16.725)
SDO_PMIC: R42.1 U14.54 | length 41.3
  Top Layer w0.2: v1(69.882,50.485) 69.882,51.04 70.082,51.24 R42.1@70.112,51.24 ; U14.54@88.102,26.992 88.102,28.551 89.056,29.505 89.056,31.514 89.349,31.806 v1(89.349,36.505)
  Sig4 w0.2: v1(69.882,50.485) 69.882,41.672 74.537,37.017 88.836,37.017 v1(89.349,36.505)
SDOEPB: R89.1 R96.1 U14.39 | length 90.9
  Top Layer w0.2: R96.1@54.56,15.141 54.599,15.181 v1(62.467,15.181) ; U14.39@91.177,20.717 94.866,20.717 95.132,20.984 v1(95.214,20.984) ; v1(118.879,39.433) R89.1@119.716,39.433
  Sig4 w0.2: v1(62.467,15.181) 62.476,15.172 62.476,14.811 64.191,13.097 65.857,11.431 92.959,11.431 93.736,12.208 93.736,20.453 94.474,21.191 94.674,21.191 94.738,21.127 95.225,21.127 95.289,21.191 95.289,21.144 95.363,21.07 105.656,21.07 118.879,34.293 v1(118.879,39.433) ; v1(95.214,20.984) 95.225,20.995 v1@95.225,21.127
SHA: C69.1 J7.1 Q4.1 Q4.2 Q4.3 Q5.5 R52.1 U5.37 | length 44.3
  Top Layer w0.2: R52.1@33.531,70.21 R52.1@33.68,70.061 ; R52.1@33.63,70.011 R52.1@33.73,70.011 ; 34.822,68.996 35.025,69.2 36.982,69.2 37.434,68.748 37.434,65.361 39.493,63.302 39.493,51.492 37.777,49.776 37.777,33.43 38.153,33.054 38.153,32.416 v1(38.141,32.404) 38.452,32.093 39.045,32.093 39.343,31.795 U5.37@39.343,31.265
  Bottom Layer w0.4: C69.1@37.219,32.186 37.418,32.385 38.122,32.385 v1(38.141,32.404)
  other v1: 32.558,64.266 33.28,64.266 33.93,64.266 34.593,64.266 35.286,64.254 35.881,64.266 31.208,64.581 30.61,64.604 32.557,64.878 33.662,64.878 34.779,64.878 35.857,64.878 31.833,64.953 36.543,64.953 31.208,65.159 30.61,65.182 33.11,65.461 34.214,65.461 35.367,65.5 31.208,65.7 30.61,65.723 25.603,66.03 26.638,66.03 27.638,66.03 24.694,66.046 28.638,66.046 29.396,66.046 32.557,66.115 33.662,66.115 34.779,66.115 35.857,66.115 31.208,66.268 31.768,66.26 30.61,66.291 36.543,66.403 33.11,66.627 34.189,66.608 35.315,66.627 31.208,66.844 30.61,66.866 31.768,66.892 36.552,67.021 24.685,67.054 29.412,67.063 32.557,67.098 33.662,67.098 34.779,67.098 35.857,67.098 31.208,67.375 30.61,67.397 31.768,67.672 33.076,67.695 34.189,67.695 35.333,67.695 31.208,67.979 30.61,68.002 24.669,68.054 29.412,68.063 32.557,68.335 33.662,68.335 34.779,68.335 35.857,68.335 31.211,68.502 30.613,68.525 24.694,68.94 29.412,68.94 25.565,69.04 26.603,69.04 27.638,69.04 28.638,69.04 30.61,69.054 31.505,69.088 32.084,69.088 32.624,69.088 33.193,69.088 33.768,69.088 34.299,69.088 30.141,69.339 30.61,69.581 31.864,69.729 32.443,69.729 32.983,69.729 30.141,69.87 26.517,70.097 27.058,70.097 27.626,70.097 28.201,70.097 28.732,70.097 32.696,70.293 30.815,70.429 32.086,70.429 30.141,70.445 31.482,70.445 26.53,70.824 27.071,70.824 27.639,70.824 28.214,70.824 28.745,70.824 32.696,70.824 30.141,71.014 31.482,71.084 32.696,71.4 26.517,71.554 27.058,71.554 27.626,71.554 28.201,71.554 28.732,71.554 30.141,71.554 31.505,71.687
SHB: C72.1 J8.1 Q7.1 Q7.2 Q7.3 Q9.5 R69.1 U5.44 | length 64.9
  Top Layer w0.2: Q7.3@15.308,69.493 15.373,69.559 16.108,69.559 16.566,70.017 R69.1@16.566,70.117
  Top Layer w0.25: v1(36.182,28.065) 36.25,28.065 36.55,27.765 U5.44@39.343,27.765
  Top Layer w0.4: R69.1@16.566,70.117 16.566,70.217 16.866,70.517 18.945,70.517 19.002,70.573 v1(21.108,70.573)
  Sig4 w0.2: v1(21.108,70.573) 21.161,70.52 21.433,70.52 23.33,68.624 23.33,63.393 23.596,63.127 25.771,63.127 27.24,61.658 27.24,53.718 23.199,49.677 23.199,42.279 35.544,29.934 35.544,28.706 36.182,28.068 v1(36.182,28.065)
  Bottom Layer w0.2: C72.1@34.888,29.145 35.544,28.489 35.762,28.489 36.182,28.068 v1(36.182,28.065)
  other v1: 12.746,58.935 11.673,59.601 13.461,59.619 10.997,60.265 14.244,60.399 10.398,60.961 14.858,61.039 10.936,61.751 15.695,61.751 11.611,62.427 15.541,62.834 12.364,63.102 21.303,63.191 18.575,63.202 19.297,63.202 19.947,63.202 20.61,63.202 21.899,63.202 17.85,63.253 15.076,63.392 17.194,63.538 12.91,63.777 14.414,63.834 17.85,63.889 22.561,63.889 17.194,64.078 18.463,64.071 19.7,64.071 20.684,64.071 21.921,64.071 13.42,64.359 19.085,64.56 21.28,64.595 20.212,64.613 17.194,64.647 18.463,65.149 19.7,65.149 20.684,65.149 21.921,65.149 17.785,65.197 17.194,65.222 22.561,65.339 19.047,65.714 20.194,65.739 21.28,65.739 14.369,65.753 14.9,65.753 15.476,65.753 16.044,65.753 16.584,65.753 17.194,65.753 17.785,65.828 22.569,65.958 18.463,66.266 19.7,66.266 20.684,66.266 21.921,66.266 17.194,66.357 14.369,66.403 14.9,66.403 15.476,66.403 16.044,66.403 16.584,66.403 17.785,66.608 22.561,66.608 19.047,66.818 20.212,66.818 21.28,66.852 17.197,66.88 18.463,67.371 19.7,67.371 20.684,67.371 21.921,67.371 17.194,67.41 15.027,67.643 15.603,67.643 16.171,67.643 16.711,67.643 17.523,68.024 18.101,68.024 18.641,68.024 19.21,68.024 19.785,68.024 20.316,68.024 20.921,68.024 21.443,68.021 21.973,68.024 22.5,68.024 16.446,68.311 17.523,68.724 18.101,68.724 18.641,68.724 19.21,68.724 19.785,68.724 20.316,68.724 20.921,68.724 21.443,68.721 21.973,68.724 15.025,68.872 15.6,68.872 16.169,68.872 16.709,68.872 17.371,69.264 17.902,69.264 18.478,69.264 19.046,69.264 19.586,69.264
SHC: C77.1 J9.1 Q8.1 Q8.2 Q8.3 Q10.5 R70.1 U5.47 | length 53.1
  Top Layer w0.25: v1(35.504,24.2) 35.504,24.258 37.51,26.265 U5.47@39.343,26.265
  Top Layer w0.3: Q8.3@9.511,55.682 9.566,55.737 10.637,55.737 R70.1@10.7,55.8 14.785,55.8 14.991,55.595 14.991,52.526 17.503,50.013 18.159,50.013 v1(18.197,49.975)
  Sig4 w0.2: v1(18.197,49.975) 18.697,49.476 18.697,37.642 32.138,24.2 v1(35.504,24.2)
  Bottom Layer w0.5: C77.1@34.972,24.225 35.479,24.225 v1(35.504,24.2)
  other v1: 6.888,45.406 7.888,45.406 8.765,45.406 5.871,45.422 10.986,45.656 11.527,45.656 12.095,45.656 12.671,45.656 13.202,45.656 13.806,45.656 14.329,45.653 14.858,45.656 15.385,45.656 5.871,46.179 8.765,46.179 10.492,46.253 11.091,46.253 15.695,46.291 11.673,46.542 12.91,46.542 13.894,46.542 15.131,46.542 10.515,47.009 12.313,47.061 13.381,47.095 14.547,47.095 5.855,47.179 8.765,47.179 10.442,47.645 11.042,47.645 11.673,47.647 12.91,47.647 13.894,47.647 15.131,47.647 15.695,47.645 5.855,48.179 10.447,48.174 11.046,48.174 12.313,48.174 13.4,48.174 15.695,48.174 14.547,48.2 8.765,48.214 10.442,48.732 11.042,48.732 15.695,48.732 11.673,48.764 12.91,48.764 13.894,48.764 15.131,48.764 5.855,49.214 8.765,49.252 13.381,49.3 10.453,49.326 11.052,49.326 12.313,49.318 15.695,49.326 14.509,49.353 11.673,49.842 12.91,49.842 13.894,49.842 15.131,49.842 10.553,49.9 5.871,50.124 6.879,50.133 8.765,50.124 7.879,50.149 10.364,50.461 10.886,50.458 11.485,50.461 12.025,50.461 12.594,50.461 13.169,50.461 13.7,50.461 14.305,50.461 14.827,50.458 15.357,50.461 15.884,50.461 10.665,51.006 14.547,51.006 11.205,51.009 11.745,51.009 12.313,51.009 12.889,51.009 13.42,51.009 14.024,51.009 15.076,51.009 15.603,51.009 10.379,51.481 10.919,51.481 11.488,51.481 12.063,51.481 12.594,51.481 13.198,51.481 13.721,51.478 14.25,51.481 14.777,51.481 9.192,52.514 9.721,52.517 10.244,52.514 10.848,52.514 11.379,52.514 11.955,52.514 12.523,52.514 13.063,52.514 9.27,53.817 9.799,53.82 10.322,53.817 10.926,53.817 11.457,53.817 12.033,53.817 12.601,53.817 13.142,53.817 9.299,54.971 9.829,54.973 10.352,54.971 10.956,54.971 11.487,54.971 12.062,54.971 12.631,54.971 13.171,54.971
SIN_P1: J21.3 R119.1 U12.8 | length 93.9
  Top Layer w0.2: R119.1@88.74,5.2 88.74,4.504 v1(89.261,3.984)
  Top Layer w0.4: U12.8@24.8,46.775 24.975,46.775 25,46.75 25,44.577 v1(26.439,43.138) 27.375,43.138 J21.3@27.47,43.043
  Sig4 w0.2: v1(26.439,43.138) 26.469,43.169 42.02,43.169 57.685,27.504 57.685,14.783 69.068,3.4 88.677,3.4 v1(89.261,3.984)
SIN_P2: J22.3 R123.1 U13.8 | length 101.1
  Top Layer w0.2: R123.1@92.847,5.102 94.202,5.102 v1(94.237,5.067)
  Top Layer w0.5: v1(41.054,50.191) 42.482,50.191 42.732,49.941 J22.3@42.732,48.963 42.743,48.952 v1(42.743,45.019)
  Sig4 w0.2: v1(25.451,49.848) 25.794,50.191 v1(41.054,50.191) ; v1(42.743,45.019) 60.079,27.682 60.079,14.777 69.559,5.297 93.97,5.297 94.2,5.067 v1(94.237,5.067)
  Bottom Layer w0.2: U13.8@24.789,48.727 25.283,48.727 25.408,48.852 25.408,49.805 v1(25.451,49.848)
SLA: Q5.1 Q5.2 Q5.3 R56.1 R61.2 U5.40 | length 37.2
  Top Layer w0.2: R56.1@37.441,61.427 37.641,61.227 37.641,60.437 37.699,60.379 37.699,51.902 35.961,50.165 35.961,33.137 36.694,32.404 36.694,31.116 38.045,29.765 U5.40@39.343,29.765
  Top Layer w0.5: v1(35.256,61.735) 37.133,61.735 37.291,61.577 37.391,61.577 37.441,61.527 R56.1@37.441,61.427 37.441,61.346 R56.1@37.391,61.296
  other v1: 28.631,58.562 28.631,59.119 28.631,59.662 28.678,60.304 29.235,60.304 29.778,60.304 30.348,60.304 30.883,60.304 31.435,60.304 32,60.304 32.521,60.304 33.078,60.304 28.678,60.942 29.235,60.942 29.778,60.942 30.348,60.942 30.883,60.942 31.435,60.942 32,60.942 32.521,60.942 33.078,60.942 33.653,61.113 34.187,61.113 34.739,61.113 35.304,61.113 28.678,61.541 29.235,61.541 29.778,61.541 30.348,61.541 30.883,61.541 31.435,61.541 32,61.541 32.521,61.541 33.078,61.541 33.604,61.735 34.138,61.735 34.691,61.735 28.663,62.136 29.184,62.136 29.718,62.136 30.271,62.136 30.835,62.136 31.356,62.136 31.913,62.136 32.88,62.527 34.187,62.572 28.82,62.627 29.412,62.627 29.965,62.627 30.529,62.627 31.05,62.627 31.607,62.627 32.88,63.088 29.018,63.115 34.187,63.132 29.589,63.203 30.141,63.203 30.706,63.203 31.226,63.203 31.784,63.203
SLB: Q9.1 Q9.2 Q9.3 R74.1 R80.2 U5.41 | length 49.9
  Top Layer w0.25: v1(31.76,30.127) 31.768,30.135 36.724,30.135 37.594,29.265 U5.41@39.343,29.265
  Top Layer w0.5: Q9.3@20.839,61.713 20.884,61.668 20.884,61.138 21.259,60.763 23.266,60.763 R74.1@23.516,61.013 ; R74.1@23.433,61.18 v1(24.182,61.18)
  Sig4 w0.2: v1(24.182,61.18) 24.8,60.562 25.216,60.562 25.584,60.194 25.584,54.259 21.588,50.263 21.588,40.315 31.76,30.142 v1(31.76,30.127)
  other v1: 16.403,57.569 16.403,58.112 16.403,58.683 16.719,59.287 17.262,59.287 17.833,59.287 18.367,59.287 18.92,59.287 19.484,59.287 20.005,59.287 20.562,59.287 17.262,59.925 17.833,59.925 18.367,59.925 18.92,59.925 19.484,59.925 20.005,59.925 20.562,59.925 21.108,60.321 17.833,60.524 18.367,60.524 18.92,60.524 19.484,60.524 20.005,60.524 20.562,60.524 21.105,60.923 17.776,61.039 18.927,61.056 20.204,61.081 17.761,61.594 18.927,61.651 20.204,61.668 17.761,62.11 18.927,62.23 20.177,62.23
SLC: Q10.1 Q10.2 Q10.3 R75.1 R81.2 U5.2 | length 40.7
  Top Layer w0.25: v1(37.943,22.626) 37.99,22.674 37.99,22.962 39.343,24.315 40.048,24.315 40.493,24.76 U5.2@40.493,25.115
  Top Layer w0.5: v1(13.708,43.303) 13.735,43.276 16.334,43.276 16.566,43.508 R75.1@16.566,43.608 ; v1(16.56,42.489) 16.566,42.495 R75.1@16.566,43.276
  Sig4 w0.2: v1(16.56,42.489) 16.571,42.477 16.571,36.927 30.872,22.626 v1(37.943,22.626)
  other v1: 7.638,41.42 8.196,41.42 8.716,41.42 9.281,41.42 9.833,41.42 10.368,41.42 7.638,42.058 8.196,42.058 8.716,42.058 9.281,42.058 9.833,42.058 10.368,42.058 10.938,42.058 11.481,42.058 7.627,42.654 8.185,42.654 8.705,42.654 9.27,42.654 9.822,42.654 10.357,42.654 10.927,42.654 11.47,42.654 12.048,42.777 12.646,42.777 13.19,42.769 13.708,42.769 8.185,43.253 8.705,43.253 9.27,43.253 9.822,43.253 10.357,43.253 10.927,43.253 11.47,43.253 12.646,43.314 13.202,43.312 12.048,43.343 8.705,43.891 9.27,43.891 9.822,43.891 10.357,43.891 10.927,43.891 13.407,43.901 12.095,43.935 13.415,44.526 12.095,44.535 9.715,44.6 10.936,44.6 10.322,44.61
SNA: C66.2 C71.1 R63.1 U5.4 | length 42.1
  Top Layer w0.2: v1(34.513,34.263) 34.513,35.345 34.714,35.546 34.714,50.824 36.05,52.16 36.05,56.762 35.827,56.984 C66.2@35.342,56.984 ; v1(40.959,23.522) 40.988,23.522 41.523,24.058 41.523,24.513 41.493,24.544 U5.4@41.493,25.115
  Top Layer w0.5: R63.1@34.049,55.817 34.049,55.765 34.289,55.525 C71.1@35.327,55.525 35.335,55.532 35.335,56.977 C66.2@35.342,56.984
  Sig4 w0.2: v1(34.513,34.263) 34.513,33.526 37.117,30.923 37.117,29.764 38.116,28.765 38.116,26.365 v1(40.959,23.522)
SNB: C81.2 C85.1 R82.1 U5.6 | length 55
  Top Layer w0.2: v1(42.34,22.1) 42.393,22.152 42.393,22.65 42.493,22.75 U5.6@42.493,25.115
  Top Layer w0.5: R82.1@21.629,55.198 21.629,55.26 21.679,55.31 C85.1@22.996,55.31 22.996,56.454 22.912,56.538 C81.2@22.912,56.638 v1(23.701,56.638)
  Sig4 w0.2: v1(23.701,56.638) 23.701,54.614 20.288,51.2 20.288,38.64 33.013,25.914 36.414,25.914 40.229,22.1 v1(42.34,22.1)
SNC: C82.2 C87.1 R83.1 U5.8 | length 46.5
  Top Layer w0.2: U5.8@43.493,25.115 43.493,23.494 43.773,23.214 v1(43.773,20.475)
  Top Layer w0.5: R83.1@12.534,37.337 13.797,37.337 C87.1@13.847,37.287 ; C87.1@13.847,37.242 C87.1@13.847,37.287 ; v1(14.577,38.633) C82.2@13.847,38.633 C87.1@13.847,37.287
  Sig4 w0.2: v1(14.577,38.633) 14.577,38.552 14.863,38.266 14.863,36.141 29.731,21.273 39.15,21.273 40.33,20.093 43.377,20.093 43.76,20.475 v1(43.773,20.475)
SOA_DRV3263: C78.1 R71.1 U14.17 | length 8
  Top Layer w0.2: R71.1@85.843,6.302 85.843,7.002 86.302,7.461 86.302,8.519 86.126,8.695 86.102,8.695 85.702,9.095 C78.1@85.702,9.195 85.702,9.797 86.102,10.197 U14.17@86.102,13.642
SOB_DRV3263: C79.1 R76.1 U14.23 | length 10.2
  Top Layer w0.2: U14.23@88.502,13.642 88.502,11.962 88.956,11.509 91.109,11.509 91.41,11.207 C79.1@91.41,9.571 91.41,9.471 91.81,9.071 91.834,9.071 92.01,8.895 92.01,7.771 91.445,7.206 R76.1@91.445,6.391
SOC_DRV3263: C80.1 R77.1 U14.22 | length 9.2
  Top Layer w0.2: U14.22@88.102,13.642 88.102,11.635 88.748,10.989 89.678,10.989 90.175,10.493 C80.1@90.175,9.552 90.175,9.452 89.775,9.052 89.751,9.052 89.575,8.876 89.575,7.091 90.175,6.491 R77.1@90.175,6.391
SPA: C66.1 C70.1 R60.1 U5.3 | length 42
  Top Layer w0.2: v1(35.063,34.961) 35.114,35.012 35.114,50.658 36.45,51.995 36.45,57.787 36.052,58.184 C66.1@35.342,58.184 35.342,58.223 C66.1@35.142,58.423 ; C70.1@35.193,59.697 C70.1@35.342,59.549 ; C66.1@35.342,58.284 35.342,58.689 ; v1(40.973,24.285) 40.983,24.295 40.983,25.105 U5.3@40.993,25.115
  Top Layer w0.5: R60.1@34.049,59.702 C70.1@35.098,59.702 ; C70.1@35.235,59.839 35.292,59.839 35.342,59.789 35.342,59.549 35.342,58.689
  Sig4 w0.2: v1(35.063,34.961) 35.063,33.542 37.517,31.088 37.517,29.958 38.516,28.958 38.516,26.533 40.706,24.343 40.916,24.343 v1(40.973,24.285)
SPB: C81.1 C84.1 R78.1 U5.5 | length 54.5
  Top Layer w0.2: v1(41.82,22.715) 41.82,22.797 41.993,22.97 U5.5@41.993,25.115
  Top Layer w0.5: R78.1@21.66,59.038 21.66,59.069 21.71,59.119 C84.1@22.912,59.119 ; C84.1@23.06,59.119 22.962,59.119 22.912,59.069 C81.1@22.912,57.838 22.912,57.738 22.962,57.688 23.578,57.688 v1(23.791,57.476)
  Sig4 w0.2: v1(23.791,57.476) 23.872,57.476 24.251,57.096 24.251,54.546 20.688,50.982 20.688,38.805 33.179,26.314 36.58,26.314 40.268,22.626 41.553,22.626 41.585,22.658 41.762,22.658 v1(41.82,22.715)
SPC: C82.1 C86.1 R79.1 U5.7 | length 46.4
  Top Layer w0.2: U5.7@42.993,25.115 43.017,25.091 43.017,20.667 v1(43.041,20.643)
  Top Layer w0.5: R79.1@12.522,41.157 C86.1@13.814,41.157 13.83,41.14 13.83,39.849 C82.1@13.847,39.833 15.216,39.833 v1(15.263,39.88)
  Sig4 w0.2: v1(15.263,39.88) 15.263,36.307 29.897,21.673 39.368,21.673 40.398,20.643 v1(43.041,20.643)
SW_U4: C20.2 L2.1 U2.13 U2.14 | length 3.8
  Top Layer w0.2: U2.14@106.502,44.581 106.502,45.298 106.915,45.711 C20.2@107.015,45.711 107.002,45.698 U2.13@107.002,44.581
  Top Layer w0.6: 107.002,46.969 107.015,46.956 C20.2@107.015,45.711
TMAG_COSP1: C111.1 R121.2 U14.20 | length 7.7
  Top Layer w0.2: C111.1@87.302,9.601 U14.20@87.302,13.642 ; C111.1@87.332,9.495 87.332,9.395 86.932,8.995 86.899,8.995 86.732,8.828 86.732,7.771 87.457,7.046 R121.2@87.457,6.4
TMAG_COSP2: C114.1 R125.2 U14.16 | length 8.7
  Top Layer w0.2: R125.2@84.456,6.345 84.456,6.445 83.703,7.199 83.703,9.027 83.925,9.249 C114.1@84.456,9.249 84.456,9.349 85.702,10.595 U14.16@85.702,13.642
TMAG_Q01: R120.2 U12.4 U14.76 | length 60.2
  Top Layer w0.2: 30.3,48.774 30.349,48.725 ; v1(75.594,26.858) 75.651,26.8 75.651,26.719 77.252,25.117 U14.76@77.827,25.117
  Top Layer w0.4: U12.4@29.2,48.725 30.349,48.725 31.979,48.725 32.195,48.941 v1(33.852,48.941) ; 30.3,48.774 R120.2@30.3,50.229
  Sig4 w0.2: v1(33.852,48.941) 46.104,48.941 63.305,31.741 69.459,31.741 74.342,26.858 v1(75.594,26.858)
TMAG_Q02: R124.2 U13.4 U14.82 | length 62.8
  Top Layer w0.2: U14.82@77.827,22.717 78.802,22.717 78.995,22.91 78.995,23.167 v1(79.052,23.224)
  Sig4 w0.2: v1(31.307,46.919) 45.246,46.919 62.367,29.798 68.395,29.798 74.275,23.919 76.76,23.919 77.455,23.224 v1(79.052,23.224)
  Bottom Layer w0.4: U13.4@29.189,46.777 30.36,46.777 ; R124.2@30.3,45.327 30.3,46.717 30.36,46.777 ; v1(31.307,46.919) 31.28,46.919 31.137,46.777 30.36,46.777
TMAG_Q11: R122.2 U12.5 U14.77 | length 65.2
  Top Layer w0.2: v1(75.308,25.671) 75.898,25.671 76.852,24.717 U14.77@77.827,24.717
  Top Layer w0.4: U12.5@24.8,48.725 24.803,48.728 25.961,48.728 v1(25.964,48.732) 25.964,48.759 26.471,49.265 R122.2@26.471,50.246
  Sig4 w0.2: v1(25.964,48.732) 26.554,49.323 32.102,49.323 33.523,47.902 45.696,47.902 62.917,30.682 69.02,30.682 74.03,25.671 v1(75.308,25.671)
TMAG_Q12: R126.2 U13.5 U14.83 | length 67.3
  Top Layer w0.2: U14.83@77.827,22.317 78.64,22.317 79.04,21.917 v1(79.052,21.917)
  Sig4 w0.2: v1(25.65,45.995) 44.54,45.995 61.693,28.842 67.596,28.842 73.356,23.082 75.801,23.082 76.508,22.374 76.54,22.374 76.996,21.917 v1(79.052,21.917)
  Bottom Layer w0.4: U13.5@24.789,46.777 24.814,46.752 25.388,46.752 25.623,46.518 25.623,46.049 25.65,46.022 v1(25.65,45.995) 25.669,45.976 25.669,45.939 26.315,45.293 R126.2@26.415,45.293
TMAG_SINP1: C110.1 R119.2 U14.21 | length 8
  Top Layer w0.2: U14.21@87.702,13.642 87.702,11.387 88.565,10.524 C110.1@88.565,9.495 88.565,9.395 88.965,8.995 88.989,8.995 89.165,8.819 89.165,7.546 88.74,7.122 R119.2@88.74,6.4
TMAG_SINP2: C113.1 R123.2 U14.24 | length 11.7
  Top Layer w0.2: U14.24@88.902,13.642 88.902,12.522 89.516,11.909 92.152,11.909 92.883,11.178 92.883,9.588 C113.1@92.847,9.552
  Top Layer w0.5: R123.2@92.847,6.302 92.847,6.402 93.894,7.449 93.894,8.89 93.382,9.402 92.897,9.402 92.847,9.452 C113.1@92.847,9.552
TX_CAN1: R101.1 TP17.1 U14.59 | length 38.3
  Top Layer w0.2: U14.59@86.102,26.992 86.102,30.38 86.097,30.385 86.097,31.706 86.19,31.799 86.19,32.237 v1(86.247,32.294)
  Top Layer w0.6: v1(110.888,33.162) 110.921,33.129 TP17.1@113.269,33.129 115.269,33.129 117.102,33.129 118.002,34.029 R101.1@118.393,34.029
  Sig4 w0.2: v1(86.247,32.294) 109.06,32.294 109.928,33.162 v1(110.888,33.162)
TX_CAN2: R111.1 TP18.1 U14.60 | length 51.6
  Top Layer w0.2: U14.60@85.702,26.992 85.702,30.214 85.697,30.219 85.697,32.638 85.881,32.822 85.881,33.23 v1(85.939,33.288)
  Top Layer w0.5: TP18.1@117.594,47.563 TP18.1@117.622,47.591 ; TP18.1@117.606,48.112 118.155,47.563 v1(119.918,47.563) 119.946,47.591 R111.1@120.854,47.591
  Sig4 w0.2: v1@85.953,33.288 108.74,33.288 116.277,40.824 116.277,42.613 119.918,46.254 v1(119.918,47.563)
UART_RX: J10.2 U14.75 | length 9.2
  Top Layer w0.2: J10.2@74.649,32.915 74.649,31.267 77.544,28.372 79.511,28.372 79.702,28.18 U14.75@79.702,26.992
VCC_6V0: C40.1 C41.1 C42.1 C56.1 TP4.1 U3.41 U3.42 U4.6 | length 7.7
  Top Layer w0.2: C56.1@64.593,42.967 64.593,42.802 65.286,42.109 U4.6@65.286,39.128
  Top Layer w0.4: C41.1@63.813,41.111 64.786,41.111 64.832,41.157
  Top Layer w0.5: C40.1@62.324,47.497 C40.1@62.49,47.497
  Bottom Layer w0.5: v1(71.815,47.255) 72.319,46.751 C42.1@74.021,46.751
VDDA_3V3: C133.1 C135.1 C136.1 L10.1 U14.14 U14.37 | length 22.3
  Top Layer w0.2: U14.14@84.902,13.642 v1(84.902,14.79) ; v1(89.952,20.302) 89.96,20.302 90.345,19.917 U14.37@91.177,19.917
  Bottom Layer w0.5: C135.1@84.525,15.83 84.575,15.78 84.575,15.118 v1(84.902,14.79) ; C133.1@84.702,13.642 C133.1@84.802,13.642 ; v1@84.924,14.77 84.924,13.864 84.852,13.792 84.852,13.692 C133.1@84.802,13.642 ; L10.1@87.927,14.415 87.977,14.465 L10.1@88.077,14.465 88.077,13.667 88.102,13.642 ; C136.1@88.864,20.317 89.937,20.317 v1(89.952,20.302) 91.202,20.302 92.26,19.244 92.26,14.731 91.172,13.642 88.102,13.642 ; C133.1@84.802,13.642 88.102,13.642
VMON: C118.2 R130.2 R131.2 U14.34 | length 22.1
  Top Layer w0.2: U14.34@91.177,18.717 94.3,18.717 94.332,18.686 95.178,18.686 95.888,19.396 R131.2@95.988,19.396 ; R131.2@96.095,19.501 96.195,19.501 96.595,19.101 96.595,19.076 96.771,18.901 98.971,18.901 99.466,19.396 C118.2@99.566,19.396 99.544,19.417 v1(99.544,25.83)
  Top Layer w0.5: v1(99.603,29.532) R130.2@99.603,32.387
  Bottom Layer w0.2: v1(99.544,25.83) 99.603,25.889 v1(99.603,29.532)
VSNS: R32.2 R34.2 U2.1 | length 4.1
  Top Layer w0.2: U2.1@104.983,42.312 104.983,41.441 104.767,41.224 104.767,40.417 105.077,40.107 105.077,40.007 105.277,39.807 R34.2@105.377,39.807
  Top Layer w0.5: R34.2@105.377,39.807 105.382,39.802 105.382,38.577 R32.2@105.387,38.572
VSUP: C102.1 C106.1 R97.1 R99.1 U8.10 U10.10 | length 27
  Top Layer w0.3: U8.10@126.136,29.658 C102.1@127.898,29.658 ; U10.10@127.884,45.64 129.678,45.64 129.777,45.54 v3(129.859,45.54)
  Top Layer w0.5: C102.1@127.898,29.658 128.078,29.658 128.709,30.289 128.709,30.624 v1(128.99,30.905)
  Power w0.5: v1(128.524,36.037) 128.731,36.244 129.859,36.244 ; v1(128.99,30.905) 129.859,31.773 129.859,36.244 ; v3(129.859,45.54) 129.859,36.244
  Bottom Layer w0.5: R97.1@126.736,34.982 126.836,34.982 127.891,36.037 v1(128.524,36.037) ; C106.1@129.703,47.35 129.721,47.368 129.721,48.451 129.771,48.501 R99.1@129.783,48.501 ; C106.1@129.839,47.126 129.839,45.559 v3(129.859,45.54)
WSN: C94.2 D5.1 J2.1 R88.2 | length 18.1
  Top Layer w0.5: R88.2@128.859,38.105 136.654,38.105 137.154,38.605 137.504,38.605 D5.1@137.554,38.655 139.957,38.655 140.128,38.826 141.869,38.826 142.133,38.562 142.133,38.326 142.383,38.076 C94.2@142.483,38.076 145.476,38.076 J2.1@145.7,38.3 J2.1@145.374,38.626
WSP: C90.2 D5.2 J1.1 R86.2 | length 26.2
  Top Layer w0.5: R86.2@128.859,36.787 128.875,36.771 137.539,36.771 D5.2@137.554,36.755 139.801,36.755 140.549,36.007 141.869,36.007 C90.2@142.332,36.471 ; C90.2@142.482,36.757 142.49,36.75 146.686,36.75 147.13,37.194 147.13,40.929 145.75,42.309 J1.1@145.75,44
WSSO: C88.2 R84.2 U14.31 | length 11.6
  Top Layer w0.2: U14.31@91.177,17.517 92.338,17.517 92.647,17.826 92.673,17.8 96.098,17.8 96.298,18 96.298,18.234 96.463,18.4 99.256,18.4 99.693,17.963 R84.2@102.027,17.963
pads on no net: D11.2 FID1.1 FID2.1 FID3.1 LBL1.0 MP1. MP2. MP3. MP4. U1.3 U1.8 U1.17 U1.21 U1.25 U2.10 U2.12 U2.16 U2.18 U3.21 U3.22 U3.23 U3.24 U3.25 U3.26 U3.27 U3.28 U3.30 U3.31 U3.43 U4.1 U8. U10. U12.3 U12.6 U13.3 U13.6 U14.9 U14.12 U14.25 U14.30 Y1.1
copper on no net:
  other v1: 123.972,33.015
  other v2: 108.336,66.989 107.536,67.789 108.336,67.789 109.136,67.789 108.336,68.589

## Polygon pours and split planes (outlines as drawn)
48V/12V_P on Top Layer "Top Layer-48V/12V_P" (solid, remove dead copper, pour order 224): 78 vertices, not listed, extent -0.3,0 121.664,83.4
48V/12V_P on Top Layer "TOP_LAYER_48V/12V_P_P015" (solid, pour order 15): 101.078,45.711 101.178,45.811 104.45,45.811 105.164,45.098 105.164,44.364 105.106,44.306 104.556,44.306 104.062,43.812 101.598,43.812 101.078,44.333
NetC7_2 on Top Layer "Top Layer-NetC7_2" (solid, remove dead copper, pour order 11): 101.936,82.362 101.936,73.958 102.091,73.803 104.741,73.803 105.041,74.102 105.041,82.509 104.837,82.713 102.287,82.713
GND on Top Layer "Top Layer-GND" (solid, remove dead copper, pour order 195): 72 vertices, not listed, extent 4.839,0.07 158.678,73.445
SLC on Top Layer "TOP_LAYER_SLC_P186" (solid, pour order 186): 19 vertices, not listed, extent 7.336,39.576 14.414,44.941
SLA on Top Layer "TOP_LAYER_SLA_P190" (solid, pour order 190): 28.348,62.783 29.018,63.453 35.188,63.453 35.549,63.092 35.549,60.729 35.242,60.421 33.628,60.421 33.352,60.145 33.352,58.291 33.281,58.22 28.629,58.22 28.348,58.502
SLB on Top Layer "TOP_LAYER_SLB_P189" (solid, pour order 189): 16.08,57.487 16.08,59.577 17.364,60.861 17.364,62.187 17.705,62.527 21.198,62.527 21.501,62.225 21.501,60.002 20.928,59.43 20.928,57.386 20.808,57.266 16.303,57.266
VCC_6V0 on Top Layer "Top Layer-VCC_6V0" (solid, pour order 185): 32 vertices, not listed, extent 61.697,39.603 74.068,48.165
GND on Top Layer "TOP_LAYER_GND_P180" (solid, pour order 180): 35.084,72.604 35.084,71.171 35.439,70.817 37.816,70.817 38.025,71.026 38.025,72.347 37.768,72.604 36.895,72.604
GND on Top Layer "TOP_LAYER_GND_P021" (solid, pour order 21): 74.385,55.858 74.385,43.621 74.755,43.251 79.359,43.251 79.777,43.669 79.777,55.816 79.49,56.103 74.63,56.103
GND on Top Layer "TOP_LAYER_GND_P009" (solid, remove dead copper, pour order 9): 17 vertices, not listed, extent 99.361,58.309 111.4,66.039
OUTB_EPB on Top Layer "TOP_LAYER_OUTB_EPB_P045" (solid, pour order 45): 17 vertices, not listed, extent 48.587,1.314 53.465,8.971
OUTA_EPB on Top Layer "TOP_LAYER_OUTA_EPB_P046" (solid, pour order 46): 53.955,8.776 53.955,7.945 55.77,7.945 56.239,7.476 56.239,5.834 56.048,5.644 54.228,5.644 53.535,4.951 53.535,2.052 54.535,1.051 58.182,1.051 59.226,2.095 59.226,5.946 56.327,8.845 54.023,8.845
48V/12V_BDC on Top Layer "TOP_LAYER_48V/12V_BDC_P043" (solid, pour order 43): 18 vertices, not listed, extent 44.633,6.594 55.841,10.076
SHC on Top Layer "TOP_LAYER_SHC_P034" (solid, pour order 34): 19 vertices, not listed, extent 4.311,44.438 16.193,56.144
SHB on Top Layer "TOP_LAYER_SHB_P033" (solid, pour order 33): 17 vertices, not listed, extent 8.735,57.787 22.844,70.011
SHA on Top Layer "TOP_LAYER_SHA_P030" (solid, pour order 30): 33.007,72.204 24.786,72.204 24.168,71.586 24.168,65.051 25.063,64.155 36.399,64.155 36.807,64.562 36.807,67.253 33.362,70.698 33.362,71.849
NetC38_1 on Top Layer "TOP_LAYER_NETC38_1_P025" (solid, pour order 25): 81.49,43.022 81.802,43.334 81.802,45.505 81.949,45.652 82.429,45.652 82.839,45.242 82.839,41.927 80.514,39.603 77.48,39.603 77.45,39.632 77.458,39.64 77.458,43.022
NetC39_1 on Top Layer "TOP_LAYER_NETC39_1_P024" (solid, pour order 24): 71.217,44.895 71.217,42.813 74.427,39.603 76.588,39.603 76.648,39.662 76.648,42.925 76.551,43.022 72.958,43.022 72.057,43.923 72.057,45.008 71.312,45.008
3.3V on Top Layer "TOP_LAYER_3.3V_P020" (solid, remove dead copper, pour order 20): 65.286,52.241 65.492,52.448 67.89,52.448 68.884,51.454 68.884,49.247 68.493,48.856 65.434,48.856 65.286,49.005
1.25V on Top Layer "TOP_LAYER_1.25V_P019" (solid, pour order 19): 66.201,32.935 66.891,32.244 68.435,32.244 68.884,32.693 68.884,36.117 69.399,36.632 70.496,36.632 70.873,37.008 70.873,37.648 70.571,37.95 69.178,37.95 68.884,38.244 66.405,38.244 66.201,38.04
NetL4_1 on Top Layer "TOP_LAYER_NETL4_1_P018" (solid, pour order 18): 64.211,36.399 64.677,36.865 65.496,36.865 65.6,36.969 65.6,38.02 65.71,38.129 65.918,38.129 65.971,38.076 65.971,32.429 65.786,32.244 64.584,32.244 64.211,32.617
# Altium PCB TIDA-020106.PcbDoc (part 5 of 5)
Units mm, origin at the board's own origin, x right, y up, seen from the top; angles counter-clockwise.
Board outline 158.53 x 83.25 mm, 6 copper layers (Top Layer, GND, Power, Sig4, GND (Mid4), Bottom Layer), stack 1.59 mm thick; 407 components, 254 nets, 1274 pads, 2396 vias.
Unrouted connection lines stored in the file: 294.

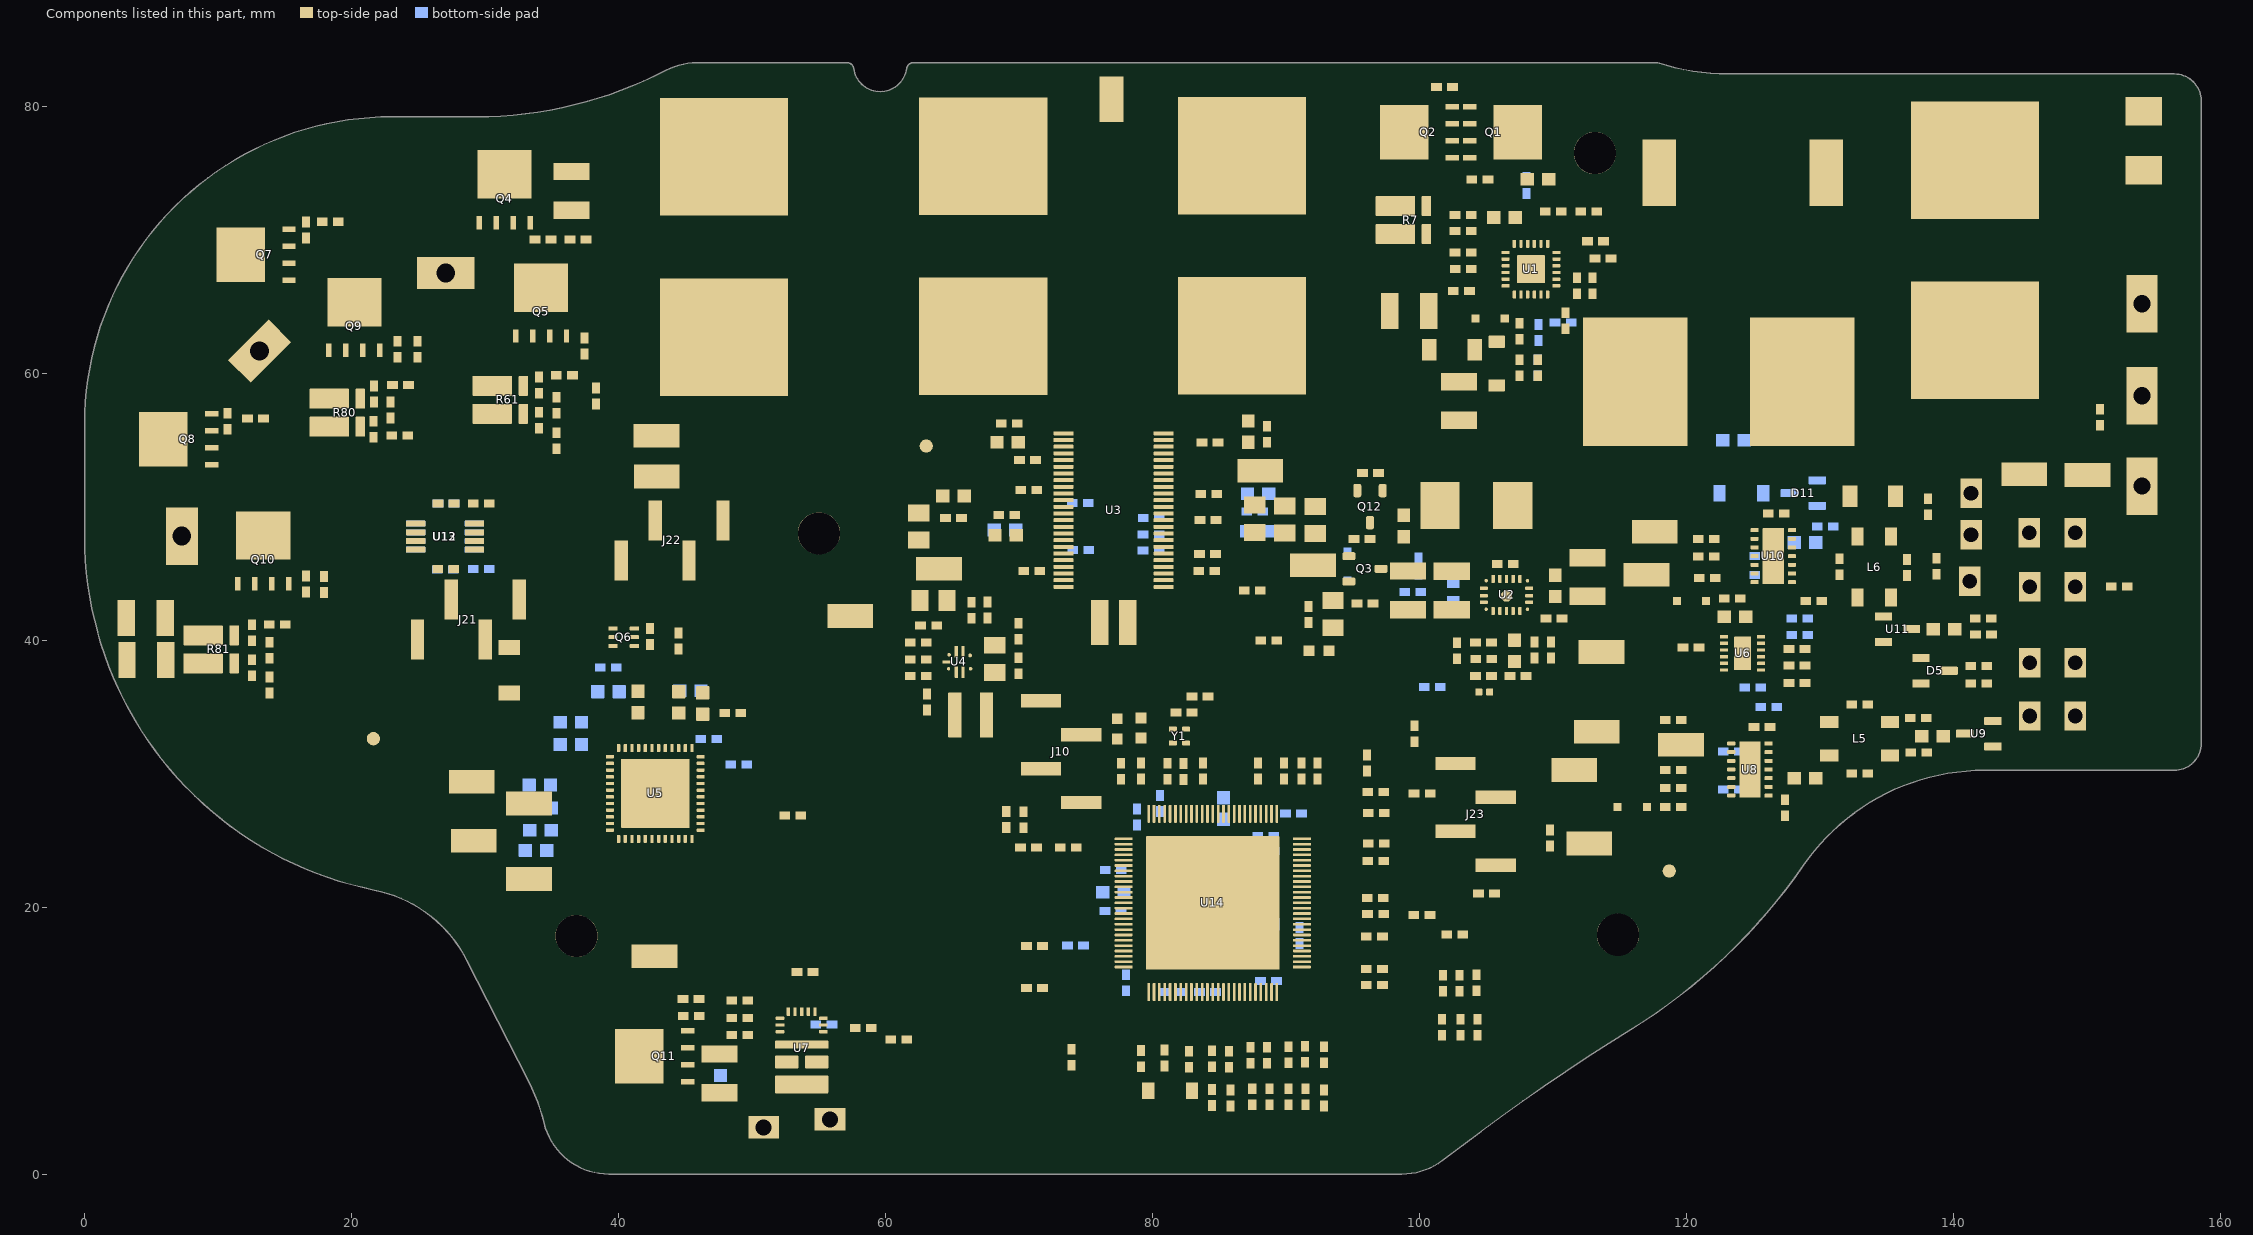
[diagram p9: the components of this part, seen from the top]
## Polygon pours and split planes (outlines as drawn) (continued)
12V on Top Layer "TOP_LAYER_12V_P016" (solid, remove dead copper, pour order 16): 22 vertices, not listed, extent 79.999,42.126 95.755,48.856
12V_Cobra on Top Layer "TOP_LAYER_12V_COBRA_P013" (solid, remove dead copper, pour order 13): 96.75,46.987 98.003,48.24 99.562,48.24 99.9,48.577 99.9,52.192 100.239,52.531 103.671,52.531 104.127,52.075 104.127,47.019 101.259,44.151 97.103,44.151 96.75,44.504
SW_U4 on Top Layer "TOP_LAYER_SW_U4_P012" (solid, remove dead copper, pour order 12): 105.621,45.596 105.621,46.392 105.002,47.011 105.002,52.088 105.509,52.594 108.177,52.594 109.086,51.686 109.086,46.864 107.629,45.407 105.81,45.407
NetQ2_5 on Top Layer "TOP_LAYER_NETQ2_5_P005" (solid, remove dead copper, pour order 5): 94.423,82.577 94.423,73.604 96.368,71.658 99.861,71.658 101.583,73.38 101.583,80.696 99.217,83.062 94.907,83.062
48V/12V_IN_FILTERED on Top Layer "TOP_LAYER_48V/12V_IN_FILTERED_P002" (solid, remove dead copper, pour order 2): 105.579,76.136 105.579,82.135 106.697,83.254 119.046,83.254 122,80.3 122,69.882 120.947,68.829 116.585,68.829 115.806,69.608 115.806,74.515 114.781,75.54 105.985,75.54 105.584,75.941
48V/12V_IN on Top Layer "TOP_LAYER_48V/12V_IN_P000" (solid, pour order 0): 126,74.68 126,80.3 128.11,82.41 147.39,82.41 152.953,76.847 156.853,76.847 157.6,76.1 157.6,63.266 156.334,62 150.455,62 149,63.455 149,68.55 147.668,69.882 127.791,69.882 126.015,71.658
GND on Bottom Layer "BOTTOM_LAYER_GND_P228" (solid, pour order 228): 34.889,72.026 34.889,70.953 37.215,68.628 37.215,66.046 38.858,66.046 40.31,67.498 41.32,67.498 41.32,67.787 38.299,70.809 38.299,71.809 37.768,72.339 35.066,72.339 34.93,72.204
NetC7_2 on Bottom Layer "Top Layer-NetC7_2" (solid, remove dead copper, pour order 221): 101.936,82.362 101.936,73.958 102.091,73.803 104.741,73.803 105.041,74.102 105.041,82.509 104.837,82.713 102.287,82.713
SLA on Bottom Layer "BOTTOM_LAYER_SLA_P216" (solid, pour order 216): 28.348,62.783 29.018,63.453 35.188,63.453 35.549,63.092 35.549,60.729 35.242,60.421 33.628,60.421 33.352,60.145 33.352,58.291 33.281,58.22 28.629,58.22 28.348,58.502
SLB on Bottom Layer "BOTTOM_LAYER_SLB_P215" (solid, pour order 215): 16.08,57.487 16.08,59.577 17.364,60.861 17.364,62.187 17.705,62.527 21.198,62.527 21.501,62.225 21.501,60.002 20.928,59.43 20.928,57.386 20.808,57.266 16.303,57.266
SLC on Bottom Layer "BOTTOM_LAYER_SLC_P214" (solid, pour order 214): 19 vertices, not listed, extent 7.336,39.576 14.414,44.941
GND on Bottom Layer "Bottom Layer-GND" (solid, remove dead copper, pour order 198): 72 vertices, not listed, extent 4.839,0.07 158.678,73.445
48V/12V_P on Bottom Layer "Bottom Layer-48V/12V_P" (solid, pour order 110): 52 vertices, not listed, extent -0.3,0 100.491,83.4
SHC on Bottom Layer "BOTTOM_LAYER_SHC_P109" (solid, pour order 109): 19 vertices, not listed, extent 4.311,44.438 16.193,56.144
SHB on Bottom Layer "BOTTOM_LAYER_SHB_P108" (solid, pour order 108): 17 vertices, not listed, extent 8.735,57.787 22.844,70.011
SHA on Bottom Layer "BOTTOM_LAYER_SHA_P107" (solid, pour order 107): 33.007,72.204 24.786,72.204 24.168,71.586 24.168,65.051 25.063,64.155 36.399,64.155 36.807,64.562 36.807,67.253 33.362,70.698 33.362,71.849
NetQ2_5 on Bottom Layer "BOTTOM_LAYER_NETQ2_5_P106" (solid, remove dead copper, pour order 106): 94.423,82.577 94.423,73.604 96.368,71.658 99.861,71.658 101.583,73.38 101.583,80.696 99.217,83.062 94.907,83.062
48V/12V_IN_FILTERED on Bottom Layer "BOTTOM_LAYER_48V/12V_IN_FILTERED_P105" (solid, remove dead copper, pour order 105): 105.579,76.136 105.579,82.135 106.697,83.254 119.046,83.254 122,80.3 122,69.882 120.947,68.829 116.585,68.829 115.806,69.608 115.806,74.515 114.781,75.54 105.985,75.54 105.584,75.941
48V/12V_IN on Bottom Layer "BOTTOM_LAYER_48V/12V_IN_P104" (solid, pour order 104): 126,74.68 126,80.3 128.11,82.41 147.39,82.41 152.953,76.847 156.853,76.847 157.6,76.1 157.6,63.266 156.334,62 150.455,62 149,63.455 149,68.55 147.668,69.882 127.791,69.882 126.015,71.658
48V/12V_BDC on Bottom Layer "BOTTOM_LAYER_48V/12V_BDC_P049" (solid, pour order 49): 19 vertices, not listed, extent 44.657,6.614 55.865,10.096
1.25V on Bottom Layer "BOTTOM_LAYER_1.25V_P041" (solid, pour order 41): 20 vertices, not listed, extent 75.368,14.563 79.286,27.499
12V on Bottom Layer "BOTTOM_LAYER_12V_P017" (solid, remove dead copper, pour order 17): 80.102,49.427 80.102,46.412 80.282,46.232 82.196,46.232 82.749,46.785 82.749,48.987 82.059,49.677 80.291,49.677 80.099,49.485
GND on Sig4 "SIG4_GND_P225" (solid, pour order 225): 34.889,72.026 34.889,70.953 37.215,68.628 37.215,66.046 38.858,66.046 40.31,67.498 41.32,67.498 41.32,67.787 38.299,70.809 38.299,71.809 37.768,72.339 35.066,72.339 34.93,72.204
NetC7_2 on Sig4 "Top Layer-NetC7_2" (solid, remove dead copper, pour order 219): 101.936,82.362 101.936,73.958 102.091,73.803 104.741,73.803 105.041,74.102 105.041,82.509 104.837,82.713 102.287,82.713
SLA on Sig4 "SIG4_SLA_P210" (solid, pour order 210): 28.348,62.783 29.018,63.453 35.188,63.453 35.549,63.092 35.549,60.729 35.242,60.421 33.628,60.421 33.352,60.145 33.352,58.291 33.281,58.22 28.629,58.22 28.348,58.502
SLB on Sig4 "SIG4_SLB_P209" (solid, pour order 209): 16.08,57.487 16.08,59.577 17.364,60.861 17.364,62.187 17.705,62.527 21.198,62.527 21.501,62.225 21.501,60.002 20.928,59.43 20.928,57.386 20.808,57.266 16.303,57.266
SLC on Sig4 "SIG4_SLC_P208" (solid, pour order 208): 19 vertices, not listed, extent 7.336,39.576 14.414,44.941
GND on Sig4 "Sig4-GND" (solid, remove dead copper, pour order 196): 72 vertices, not listed, extent 4.839,0.07 158.678,73.445
48V/12V_BDC on Sig4 "SIG4_48V/12V_BDC_P178" (solid, pour order 178): 19 vertices, not listed, extent 44.627,6.59 55.835,10.072
48V/12V_P on Sig4 "Sig4-48V/12V_P" (solid, pour order 96): 54 vertices, not listed, extent -0.3,0 100.491,83.4
OUTA_EPB on Sig4 "SIG4_OUTA_EPB_P118" (solid, pour order 118): 53.955,8.776 53.955,7.945 55.77,7.945 56.239,7.476 56.239,5.834 56.048,5.644 54.228,5.644 53.535,4.951 53.535,2.052 54.535,1.051 58.182,1.051 59.226,2.095 59.226,5.946 56.327,8.845 54.023,8.845
OUTB_EPB on Sig4 "SIG4_OUTB_EPB_P117" (solid, pour order 117): 17 vertices, not listed, extent 48.587,1.314 53.465,8.971
SHC on Sig4 "SIG4_SHC_P095" (solid, pour order 95): 19 vertices, not listed, extent 4.311,44.438 16.193,56.144
SHB on Sig4 "SIG4_SHB_P094" (solid, pour order 94): 17 vertices, not listed, extent 8.735,57.787 22.844,70.011
SHA on Sig4 "SIG4_SHA_P093" (solid, pour order 93): 33.007,72.204 24.786,72.204 24.168,71.586 24.168,65.051 25.063,64.155 36.399,64.155 36.807,64.562 36.807,67.253 33.362,70.698 33.362,71.849
NetQ2_5 on Sig4 "SIG4_NETQ2_5_P092" (solid, remove dead copper, pour order 92): 94.423,82.577 94.423,73.604 96.368,71.658 99.861,71.658 101.583,73.38 101.583,80.696 99.217,83.062 94.907,83.062
48V/12V_IN_FILTERED on Sig4 "SIG4_48V/12V_IN_FILTERED_P091" (solid, remove dead copper, pour order 91): 105.579,76.136 105.579,82.135 106.697,83.254 119.046,83.254 122,80.3 122,69.882 120.947,68.829 116.585,68.829 115.806,69.608 115.806,74.515 114.781,75.54 105.985,75.54 105.584,75.941
48V/12V_IN on Sig4 "SIG4_48V/12V_IN_P090" (solid, pour order 90): 126,74.68 126,80.3 128.11,82.41 147.39,82.41 152.953,76.847 156.853,76.847 157.6,76.1 157.6,63.266 156.334,62 150.455,62 149,63.455 149,68.55 147.668,69.882 127.791,69.882 126.015,71.658
1.25V on Sig4 "SIG4_1.25V_P042" (solid, pour order 42): 79.086,17.917 79.286,17.718 79.286,16.746 80.238,15.795 82.102,15.795 82.102,14.653 81.865,14.415 77.764,14.415 77.292,14.888 77.292,17.382 77.827,17.917
1.25V on Sig4 "SIG4_1.25V_P040" (solid, pour order 40): 21 vertices, not listed, extent 66.191,22.473 90.52,36.718
GND on GND "GND_GND_P226" (solid, pour order 226): 34.889,72.026 34.889,70.953 37.215,68.628 37.215,66.046 38.858,66.046 40.31,67.498 41.32,67.498 41.32,67.787 38.299,70.809 38.299,71.809 37.768,72.339 35.066,72.339 34.93,72.204
NetC7_2 on GND "Top Layer-NetC7_2" (solid, remove dead copper, pour order 218): 101.936,82.362 101.936,73.958 102.091,73.803 104.741,73.803 105.041,74.102 105.041,82.509 104.837,82.713 102.287,82.713
SLA on GND "GND_SLA_P204" (solid, pour order 204): 28.348,62.783 29.018,63.453 35.188,63.453 35.549,63.092 35.549,60.729 35.242,60.421 33.628,60.421 33.352,60.145 33.352,58.291 33.281,58.22 28.629,58.22 28.348,58.502
SLB on GND "GND_SLB_P203" (solid, pour order 203): 16.08,57.487 16.08,59.577 17.364,60.861 17.364,62.187 17.705,62.527 21.198,62.527 21.501,62.225 21.501,60.002 20.928,59.43 20.928,57.386 20.808,57.266 16.303,57.266
SLC on GND "GND_SLC_P202" (solid, pour order 202): 19 vertices, not listed, extent 7.336,39.576 14.414,44.941
GND on GND "GND-GND" (solid, remove dead copper, pour order 193): 72 vertices, not listed, extent 4.839,0.07 158.678,73.445
48V/12V_P on GND "GND-48V/12V_P" (solid, pour order 82): 53 vertices, not listed, extent -0.3,0 100.491,83.4
SHC on GND "GND_SHC_P081" (solid, pour order 81): 19 vertices, not listed, extent 4.311,44.438 16.193,56.144
SHB on GND "GND_SHB_P080" (solid, pour order 80): 18 vertices, not listed, extent 8.735,57.787 22.844,70.011
SHA on GND "GND_SHA_P079" (solid, pour order 79): 33.007,72.204 24.786,72.204 24.168,71.586 24.168,65.051 25.063,64.155 36.399,64.155 36.807,64.562 36.807,67.253 33.362,70.698 33.362,71.849
NetQ2_5 on GND "GND_NETQ2_5_P078" (solid, remove dead copper, pour order 78): 94.423,82.577 94.423,73.604 96.368,71.658 99.861,71.658 101.583,73.38 101.583,80.696 99.217,83.062 94.907,83.062
48V/12V_IN_FILTERED on GND "GND_48V/12V_IN_FILTERED_P077" (solid, remove dead copper, pour order 77): 105.579,76.136 105.579,82.135 106.697,83.254 119.046,83.254 122,80.3 122,69.882 120.947,68.829 116.585,68.829 115.806,69.608 115.806,74.515 114.781,75.54 105.985,75.54 105.584,75.941
48V/12V_IN on GND "GND_48V/12V_IN_P076" (solid, pour order 76): 126,74.68 126,80.3 128.11,82.41 147.39,82.41 152.953,76.847 156.853,76.847 157.6,76.1 157.6,63.266 156.334,62 150.455,62 149,63.455 149,68.55 147.668,69.882 127.791,69.882 126.015,71.658
NetC7_2 on Power "Top Layer-NetC7_2" (solid, remove dead copper, pour order 217): 101.936,82.362 101.936,73.958 102.091,73.803 104.741,73.803 105.041,74.102 105.041,82.509 104.837,82.713 102.287,82.713
SLA on Power "POWER_SLA_P207" (solid, pour order 207): 28.348,62.783 29.018,63.453 35.188,63.453 35.549,63.092 35.549,60.729 35.242,60.421 33.628,60.421 33.352,60.145 33.352,58.291 33.281,58.22 28.629,58.22 28.348,58.502
SLB on Power "POWER_SLB_P206" (solid, pour order 206): 16.08,57.487 16.08,59.577 17.364,60.861 17.364,62.187 17.705,62.527 21.198,62.527 21.501,62.225 21.501,60.002 20.928,59.43 20.928,57.386 20.808,57.266 16.303,57.266
SLC on Power "POWER_SLC_P205" (solid, pour order 205): 19 vertices, not listed, extent 7.336,39.576 14.414,44.941
3.3V on Power "Power-3.3V" (solid, remove dead copper, pour order 194): 72 vertices, not listed, extent 4.839,0.07 158.678,73.445
OUTA_EPB on Power "POWER_OUTA_EPB_P175" (solid, pour order 175): 53.955,8.776 53.955,7.945 55.77,7.945 56.239,7.476 56.239,5.834 56.048,5.644 54.228,5.644 53.535,4.951 53.535,2.052 54.535,1.051 58.182,1.051 59.226,2.095 59.226,5.946 56.327,8.845 54.023,8.845
OUTB_EPB on Power "POWER_OUTB_EPB_P174" (solid, pour order 174): 17 vertices, not listed, extent 48.587,1.314 53.465,8.971
48V/12V_BDC on Power "POWER_48V/12V_BDC_P173" (solid, pour order 173): 19 vertices, not listed, extent 44.627,6.59 55.835,10.072
3.3V on Power "POWER_3.3V_P172" (solid, pour order 172): 18 vertices, not listed, extent 35.281,0 62.446,15.181
48V/12V_P on Power "Power-48V/12V_P" (solid, pour order 89): 53 vertices, not listed, extent -0.3,0 100.491,83.4
OUTA_EPB on Power "POWER_OUTA_EPB_P120" (solid, pour order 120): 53.955,8.776 53.955,7.945 55.77,7.945 56.239,7.476 56.239,5.834 56.048,5.644 54.228,5.644 53.535,4.951 53.535,2.052 54.535,1.051 58.182,1.051 59.226,2.095 59.226,5.946 56.327,8.845 54.023,8.845
OUTB_EPB on Power "POWER_OUTB_EPB_P119" (solid, pour order 119): 17 vertices, not listed, extent 48.587,1.314 53.465,8.971
SHC on Power "POWER_SHC_P088" (solid, pour order 88): 19 vertices, not listed, extent 4.311,44.438 16.193,56.144
SHB on Power "POWER_SHB_P087" (solid, pour order 87): 17 vertices, not listed, extent 8.735,57.787 22.844,70.011
SHA on Power "POWER_SHA_P086" (solid, pour order 86): 33.007,72.204 24.786,72.204 24.168,71.586 24.168,65.051 25.063,64.155 36.399,64.155 36.807,64.562 36.807,67.253 33.362,70.698 33.362,71.849
NetQ2_5 on Power "POWER_NETQ2_5_P085" (solid, remove dead copper, pour order 85): 94.423,82.577 94.423,73.604 96.368,71.658 99.861,71.658 101.583,73.38 101.583,80.696 99.217,83.062 94.907,83.062
48V/12V_IN_FILTERED on Power "POWER_48V/12V_IN_FILTERED_P084" (solid, remove dead copper, pour order 84): 105.579,76.136 105.579,82.135 106.697,83.254 119.046,83.254 122,80.3 122,69.882 120.947,68.829 116.585,68.829 115.806,69.608 115.806,74.515 114.781,75.54 105.985,75.54 105.584,75.941
48V/12V_IN on Power "POWER_48V/12V_IN_P083" (solid, pour order 83): 126,74.68 126,80.3 128.11,82.41 147.39,82.41 152.953,76.847 156.853,76.847 157.6,76.1 157.6,63.266 156.334,62 150.455,62 149,63.455 149,68.55 147.668,69.882 127.791,69.882 126.015,71.658
GND on GND (Mid4) "GND_GND_P227" (solid, pour order 227): 34.889,72.026 34.889,70.953 37.215,68.628 37.215,66.046 38.858,66.046 40.31,67.498 41.32,67.498 41.32,67.787 38.299,70.809 38.299,71.809 37.768,72.339 35.066,72.339 34.93,72.204
NetC7_2 on GND (Mid4) "Top Layer-NetC7_2" (solid, remove dead copper, pour order 220): 101.936,82.362 101.936,73.958 102.091,73.803 104.741,73.803 105.041,74.102 105.041,82.509 104.837,82.713 102.287,82.713
SLA on GND (Mid4) "GND_SLA_P213" (solid, pour order 213): 28.348,62.783 29.018,63.453 35.188,63.453 35.549,63.092 35.549,60.729 35.242,60.421 33.628,60.421 33.352,60.145 33.352,58.291 33.281,58.22 28.629,58.22 28.348,58.502
SLB on GND (Mid4) "GND_SLB_P212" (solid, pour order 212): 16.08,57.487 16.08,59.577 17.364,60.861 17.364,62.187 17.705,62.527 21.198,62.527 21.501,62.225 21.501,60.002 20.928,59.43 20.928,57.386 20.808,57.266 16.303,57.266
SLC on GND (Mid4) "GND_SLC_P211" (solid, pour order 211): 19 vertices, not listed, extent 7.336,39.576 14.414,44.941
GND on GND (Mid4) "GND-GND 1" (solid, remove dead copper, pour order 197): 72 vertices, not listed, extent 4.839,0.07 158.678,73.445
48V/12V_P on GND (Mid4) "GND-48V/12V_P 1" (solid, pour order 103): 52 vertices, not listed, extent -0.3,0 100.491,83.4
SHC on GND (Mid4) "GND_SHC_P102" (solid, pour order 102): 19 vertices, not listed, extent 4.311,44.438 16.193,56.144
SHB on GND (Mid4) "GND_SHB_P101" (solid, pour order 101): 17 vertices, not listed, extent 8.735,57.787 22.844,70.011
SHA on GND (Mid4) "GND_SHA_P100" (solid, pour order 100): 33.007,72.204 24.786,72.204 24.168,71.586 24.168,65.051 25.063,64.155 36.399,64.155 36.807,64.562 36.807,67.253 33.362,70.698 33.362,71.849
NetQ2_5 on GND (Mid4) "GND_NETQ2_5_P099" (solid, remove dead copper, pour order 99): 94.423,82.577 94.423,73.604 96.368,71.658 99.861,71.658 101.583,73.38 101.583,80.696 99.217,83.062 94.907,83.062
48V/12V_IN_FILTERED on GND (Mid4) "GND_48V/12V_IN_FILTERED_P098" (solid, remove dead copper, pour order 98): 105.579,76.136 105.579,82.135 106.697,83.254 119.046,83.254 122,80.3 122,69.882 120.947,68.829 116.585,68.829 115.806,69.608 115.806,74.515 114.781,75.54 105.985,75.54 105.584,75.941
48V/12V_IN on GND (Mid4) "GND_48V/12V_IN_P097" (solid, pour order 97): 126,74.68 126,80.3 128.11,82.41 147.39,82.41 152.953,76.847 156.853,76.847 157.6,76.1 157.6,63.266 156.334,62 150.455,62 149,63.455 149,68.55 147.668,69.882 127.791,69.882 126.015,71.658

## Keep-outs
Keep-Out Layer:
  circle w0.1: c55,48 r3
  circle w0.1: c113.1,76.482 r3
  circle w0.1: c114.8,17.931 r3
  circle w0.1: c36.8,17.852 r3
  lines w0.006: 22.996,79.202 cw(c23,79.202) 23.003,79.202 ; 22.996,79.202 ccw(c23,79.202) 23.003,79.202 ; 22.996,79.202 cw(c23,79.202) 23.003,79.202 ; 22.996,79.202 ccw(c23,79.202) 23.003,79.202 ; 28.625,16.015 cw(c28.628,16.015) 28.631,16.015 ; 28.625,16.015 ccw(c28.628,16.015) 28.631,16.015 ; 28.625,16.015 cw(c28.628,16.015) 28.631,16.015 ; 28.625,16.015 ccw(c28.628,16.015) 28.631,16.015 ; 29.33,79.202 cw(c29.334,79.202) 29.337,79.202 ; 29.33,79.202 ccw(c29.334,79.202) 29.337,79.202 ; 29.33,79.202 cw(c29.334,79.202) 29.337,79.202 ; 29.33,79.202 ccw(c29.334,79.202) 29.337,79.202 ; 33.25,6.938 cw(c33.253,6.938) 33.256,6.938 ; 33.25,6.938 ccw(c33.253,6.938) 33.256,6.938 ; 33.25,6.938 cw(c33.253,6.938) 33.256,6.938 ; 33.25,6.938 ccw(c33.253,6.938) 33.256,6.938 ; 34.409,3.814 cw(c34.412,3.814) 34.415,3.814 ; 34.409,3.814 ccw(c34.412,3.814) 34.415,3.814 ; 34.409,3.814 cw(c34.412,3.814) 34.415,3.814 ; 34.409,3.814 ccw(c34.412,3.814) 34.415,3.814 ; 39.266,0 cw(c39.269,0) 39.272,0 ; 39.266,0 ccw(c39.269,0) 39.272,0 ; 39.266,0 cw(c39.269,0) 39.272,0 ; 39.266,0 ccw(c39.269,0) 39.272,0 ; 43.555,82.687 cw(c43.559,82.687) 43.562,82.687 ; 43.555,82.687 ccw(c43.559,82.687) 43.562,82.687 ; 43.555,82.687 cw(c43.559,82.687) 43.562,82.687 ; 43.555,82.687 ccw(c43.559,82.687) 43.562,82.687 ; 45.867,83.254 cw(c45.87,83.254) 45.873,83.254 ; 45.867,83.254 ccw(c45.87,83.254) 45.873,83.254 ; 45.867,83.254 cw(c45.87,83.254) 45.873,83.254 ; 45.867,83.254 ccw(c45.87,83.254) 45.873,83.254 ; 57.106,83.254 cw(c57.109,83.254) 57.113,83.254 ; 57.106,83.254 ccw(c57.109,83.254) 57.113,83.254 ; 57.106,83.254 cw(c57.109,83.254) 57.113,83.254 ; 57.106,83.254 ccw(c57.109,83.254) 57.113,83.254 ; 57.602,82.82 cw(c57.605,82.82) 57.608,82.82 ; 57.602,82.82 ccw(c57.605,82.82) 57.608,82.82 ; 57.602,82.82 cw(c57.605,82.82) 57.608,82.82 ; 57.602,82.82 ccw(c57.605,82.82) 57.608,82.82 ; 59.584,81.087 cw(c59.587,81.087) 59.59,81.087 ; 59.584,81.087 ccw(c59.587,81.087) 59.59,81.087 ; 59.584,81.087 cw(c59.587,81.087) 59.59,81.087 ; 59.584,81.087 ccw(c59.587,81.087) 59.59,81.087 ; 61.566,82.82 cw(c61.569,82.82) 61.572,82.82 ; 61.566,82.82 ccw(c61.569,82.82) 61.572,82.82 ; 61.566,82.82 cw(c61.569,82.82) 61.572,82.82 ; 61.566,82.82 ccw(c61.569,82.82) 61.572,82.82 ; 62.062,83.254 cw(c62.065,83.254) 62.068,83.254 ; 62.062,83.254 ccw(c62.065,83.254) 62.068,83.254 ; 62.062,83.254 cw(c62.065,83.254) 62.068,83.254 ; 62.062,83.254 ccw(c62.065,83.254) 62.068,83.254 ; 98.668,0 cw(c98.671,0) 98.675,0 ; 98.668,0 ccw(c98.671,0) 98.675,0 ; 98.668,0 cw(c98.671,0) 98.675,0 ; 98.668,0 ccw(c98.671,0) 98.675,0 ; 101.665,0.997 cw(c101.669,0.997) 101.672,0.997 ; 101.665,0.997 ccw(c101.669,0.997) 101.672,0.997 ; 101.665,0.997 cw(c101.669,0.997) 101.672,0.997 ; 101.665,0.997 ccw(c101.669,0.997) 101.672,0.997 ; 115.803,10.827 cw(c115.806,10.827) 115.809,10.827 ; 115.803,10.827 ccw(c115.806,10.827) 115.809,10.827 ; 115.803,10.827 cw(c115.806,10.827) 115.809,10.827 ; 115.803,10.827 ccw(c115.806,10.827) 115.809,10.827 ; 117.832,83.254 cw(c117.836,83.254) 117.839,83.254 ; 117.832,83.254 ccw(c117.836,83.254) 117.839,83.254 ; 117.832,83.254 cw(c117.836,83.254) 117.839,83.254 ; 117.832,83.254 ccw(c117.836,83.254) 117.839,83.254 ; 123.121,82.41 cw(c123.124,82.41) 123.127,82.41 ; 123.121,82.41 ccw(c123.124,82.41) 123.127,82.41 ; 123.121,82.41 cw(c123.125,82.41) 123.128,82.41 ; 123.121,82.41 ccw(c123.125,82.41) 123.128,82.41 ; 123.121,82.41 cw(c123.124,82.41) 123.127,82.41 ; 123.121,82.41 ccw(c123.124,82.41) 123.127,82.41 ; 123.121,82.41 cw(c123.125,82.41) 123.128,82.41 ; 123.121,82.41 ccw(c123.125,82.41) 123.128,82.41 ; 128.728,23.118 cw(c128.731,23.118) 128.734,23.118 ; 128.728,23.118 ccw(c128.731,23.118) 128.734,23.118 ; 128.728,23.118 cw(c128.731,23.118) 128.734,23.118 ; 128.728,23.118 ccw(c128.731,23.118) 128.734,23.118 ; 142.312,30.252 cw(c142.315,30.252) 142.318,30.252 ; 142.312,30.252 ccw(c142.315,30.252) 142.318,30.252 ; 142.312,30.252 cw(c142.315,30.252) 142.318,30.252 ; 142.312,30.252 ccw(c142.315,30.252) 142.318,30.252 ; 156.53,30.252 cw(c156.533,30.252) 156.536,30.252 ; 156.53,30.252 ccw(c156.533,30.252) 156.536,30.252 ; 156.53,30.252 cw(c156.533,30.252) 156.536,30.252 ; 156.53,30.252 ccw(c156.533,30.252) 156.536,30.252 ; 156.529,82.41 cw(c156.532,82.41) 156.536,82.41 ; 156.529,82.41 ccw(c156.532,82.41) 156.536,82.41 ; 156.53,82.41 cw(c156.533,82.41) 156.536,82.41 ; 156.53,82.41 ccw(c156.533,82.41) 156.536,82.41 ; 156.529,82.41 cw(c156.532,82.41) 156.536,82.41 ; 156.529,82.41 ccw(c156.532,82.41) 156.536,82.41 ; 156.53,82.41 cw(c156.533,82.41) 156.536,82.41 ; 156.53,82.41 ccw(c156.533,82.41) 156.536,82.41 ; 158.529,80.41 cw(c158.532,80.41) 158.536,80.41 ; 158.529,80.41 ccw(c158.532,80.41) 158.536,80.41 ; 158.529,80.41 cw(c158.532,80.41) 158.536,80.41 ; 158.529,80.41 ccw(c158.532,80.41) 158.536,80.41 ; 158.53,32.252 cw(c158.533,32.252) 158.536,32.252 ; 158.53,32.252 ccw(c158.533,32.252) 158.536,32.252 ; 158.53,32.252 cw(c158.533,32.252) 158.536,32.252 ; 158.53,32.252 ccw(c158.533,32.252) 158.536,32.252 ; 158.53,80.41 cw(c158.533,80.41) 158.536,80.41 ; 158.53,80.41 ccw(c158.533,80.41) 158.536,80.41 ; 158.53,80.41 cw(c158.533,80.41) 158.536,80.41 ; 158.53,80.41 ccw(c158.533,80.41) 158.536,80.41 ; -0.004,47.752 cw(c0,47.752) 0.003,47.752 cw(c0,47.752) -0.004,47.752 ; -0.004,56.202 cw(c0,56.202) 0.003,56.202 cw(c0,56.202) -0.004,56.202 ; -0.004,56.226 cw(c0,56.226) 0.003,56.226 cw(c0,56.226) -0.004,56.226 ; -0.003,47.752 cw(c0,47.752) 0.003,47.752 cw(c0,47.752) -0.003,47.752 ; -0.003,56.202 cw(c0,56.202) 0.003,56.202 cw(c0,56.202) -0.003,56.202 ; -0.003,56.226 cw(c0,56.226) 0.003,56.226 cw(c0,56.226) -0.003,56.226 ; 0.672,41.753 cw(c0.675,41.753) 0.678,41.753 cw(c0.675,41.753) 0.672,41.753 ; 6.722,72.453 cw(c6.725,72.453) 6.728,72.453 cw(c6.725,72.453) 6.722,72.453 ; 21.683,21.28 cw(c21.686,21.28) 21.689,21.28 cw(c21.686,21.28) 21.683,21.28 ; 21.683,21.28 cw(c21.686,21.28) 21.689,21.28 cw(c21.686,21.28) 21.683,21.28 ; 31.497,72.449 cw(c31.5,72.449) 31.503,72.449 cw(c31.5,72.449) 31.497,72.449 ; 31.497,72.453 cw(c31.5,72.453) 31.503,72.453 cw(c31.5,72.453) 31.497,72.453 ; 67.899,83.282 cw(c67.903,83.282) 67.906,83.282 cw(c67.903,83.282) 67.899,83.282 ; 68.736,83.254 cw(c68.739,83.254) 68.742,83.254 cw(c68.739,83.254) 68.736,83.254 ; 117.264,83.249 cw(c117.268,83.249) 117.271,83.249 cw(c117.268,83.249) 117.264,83.249 ; 118.344,83.103 cw(c118.348,83.103) 118.351,83.103 cw(c118.348,83.103) 118.344,83.103 ; 118.458,83.062 cw(c118.461,83.062) 118.464,83.062 cw(c118.461,83.062) 118.458,83.062 ; 135.997,29.103 cw(c136,29.103) 136.003,29.103 cw(c136,29.103) 135.997,29.103 ; 147.997,82.403 cw(c148,82.403) 148.003,82.403 cw(c148,82.403) 147.997,82.403 ; 158.529,35.352 cw(c158.532,35.352) 158.536,35.352 cw(c158.532,35.352) 158.529,35.352
  lines w0.013: 21.686,21.28 cw(c27,47.752) 0,47.752 0,56.202 0,56.226 cw(c23,56.202) 23,79.202 29.334,79.202 ccw(c29.334,109.974) 43.558,82.687 cw(c45.87,78.254) 45.87,83.254 57.109,83.254 cw(c57.109,82.754) 57.605,82.82 ccw(c59.587,83.087) 59.587,81.087 ccw(c59.587,83.087) 61.569,82.82 cw(c62.065,82.754) 62.065,83.254 117.836,83.254 ccw(c123.125,99.41) 123.125,82.41 156.533,82.41 ; 21.686,21.28 cw(c19.718,11.475) 28.628,16.015 33.253,6.938 cw(c20.408,0.395) 34.412,3.814 ccw(c39.269,5) 39.269,0 98.671,0 ccw(c98.671,5) 101.669,0.997 104.606,3.197 cw(c195.432,-118.089) 115.806,10.827 ccw(c93,47.752) 128.731,23.118 cw(c142.315,13.752) 142.315,30.252 156.533,30.252 ccw(c156.533,32.252) 158.533,32.252 158.533,80.41 ; 118.461,83.062 ccw(c123.124,99.41) 123.124,82.41 156.532,82.41 ; 158.532,35.352 158.532,80.41 ; 156.532,82.41 cw(c156.532,80.41) 158.532,80.41 ; 156.533,82.41 cw(c156.533,80.41) 158.533,80.41
  text ".Layer_Name" at -14.045,-36.597 h0.8

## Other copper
Top Layer:
  text ".Layer_Name" at -14.045,-36.597 h0.8
Power:
  pour cut-out: 101.272,66.783 101.272,58.496 97.947,55.171 66.057,55.171 61.403,50.517 28.399,50.517 25.893,48.012 25.893,23.68 25.82,23.608 16.652,32.776 8.804,32.776 4.854,36.727 4.854,42.928 5.337,43.412 6.3,43.412 6.894,42.817 6.894,39.94 7.678,39.156 11.603,39.156 11.909,39.463 11.909,41.684 12.364,42.139 13.88,42.139 14.577,42.836 14.577,44.761 15.9,44.761 16.923,45.784 15.928,56.604 16.531,56.789 20.617,56.789 21.121,57.293 21.121,59.347 21.751,59.978 21.751,62.17 22.228,62.647 22.825,62.647 23.631,63.453 27.183,63.453 28.003,62.633 28.003,58.558 28.79,57.771 33.176,57.771 33.528,58.123 33.528,60.019 33.654,60.145 35.134,60.145 35.935,60.947 35.935,63.01 37.215,64.289 37.215,66.524 38.818,68.127 91.623,68.127 91.623,67.899 93.716,65.806 99.751,65.806 100.728,66.783
  pour cut-out: 97.939,55.163 97.947,55.171 111.362,55.171 114.169,52.364 115.024,53.219 148.741,53.219 150.324,54.802 157.205,54.802 158.329,53.678 159,54.349 159,60.223 157.533,61.69 157.466,61.623 150.194,61.623 148.334,63.483 148.334,68.116 147.9,68.55 147.718,68.368 116.101,68.368 115.424,69.045 115.424,73.621 115.051,73.994 103.819,73.994 103.436,73.611 102.272,73.611 100.591,71.929 100.591,57.863 100.016,57.288
Bottom Layer:
  text ".Layer_Name" at -14.045,-36.597 h0.8

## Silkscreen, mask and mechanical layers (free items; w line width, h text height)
Top Overlay:
  text "A" at 25.396,64.673 h0.8
  text "+" at 151.539,64.49 h3
  text "VBAT" at 156.501,63.29 h0.8 r90
  text "B" at 14.166,59.23 h0.8
  text "3.3Vref" at 89.29,56.537 h0.8
  text "5Vp1" at 156.701,56.477 h0.8 r90
  text "5Vp2" at 143.72,54.133 h0.8
  text "5Vp1" at 147.918,53.973 h0.8
  text "GLA" at 45.242,53.685 h0.8
  text "TX_CAN2" at 108.977,51.307 h0.8
  text "GHA" at 45.101,50.85 h0.8
  text "GND" at 156.333,50.353 h0.8 r90
  text "RX_CAN2" at 109.128,50.114 h0.8
  text "-" at 151.884,49.621 h3
  text "5Vp2" at 140.016,49.525 h0.8 r90
  text "GND" at 140.1,46.8 h0.8 r90
  text "CAN2L" at 147.791,46.151 h0.8 r90
  text "CAN2H" at 151.27,46.124 h0.8 r90
  text "C" at 4.246,46.019 h0.8
  text "6V" at 59.843,45.009 h0.8
  text "12V" at 87.702,44.766 h0.8
  text "GND" at 41.64,43.773 h0.8 r90
  text "PFS" at 140.204,43.433 h0.8 r90
  text "SIN2" at 43.827,43.063 h0.8 r90
  text "3.3V" at 48.065,42.997 h0.8 r90
  text "COS2" at 46.723,42.926 h0.8 r90
  text "WSP" at 147.8,42.9 h0.8 r90
  text "PTS" at 150.981,42.903 h0.8 r90
  text "3.3V" at 55.26,39.281 h0.8
  text "3.3V" at 35.138,38.858 h0.8 r90
  text "WSSO" at 115.957,37.478 h0.8
  text "SIN1" at 27.9,37.342 h0.8 r90
  text "GND" at 24.21,37.294 h0.8 r90
  text "GND" at 151.232,37.283 h0.8 r90
  text "WSN" at 147.8,37.2 h0.8 r90
  text "3.3V" at 73.731,37.159 h0.8
  text "COS1" at 30.54,34.988 h0.8 r90
  text "5V" at 121.019,34.969 h0.8
  text "TX_CAN1" at 112.391,34.699 h0.8
  text "RX" at 74.821,33.778 h0.8
  text "CAN1L" at 147.675,32.611 h0.8 r90
  text "CAN1H" at 151.395,32.232 h0.8 r90
  text "Ver. B" at 51.682,31.93 h1.5
  text "TX" at 70.277,31.322 h0.8
  text "GND" at 105.664,30.96 h0.8
  text "GHB" at 32.905,29.52 h0.8
  text "TIDA-020106" at 47.97,28.515 h1.5
  text "GLB" at 24.301,28.337 h0.8
  text "RX_CAN1" at 108.393,28.06 h0.8
  text "GND" at 68.857,27.981 h0.8
  text "51" at 90.952,27.208 h0.8 r90
  text "TCK" at 105.802,26.714 h0.8
  text "75" at 79.368,26.567 h0.8 r90
  text "50" at 91.518,25.458 h0.8
  text "76" at 75.296,25.118 h0.8
  text "20260517" at 50.478,24.126 h1.5
  text "TMS" at 100.237,24.04 h0.8
  text "3.3V" at 105.916,23.892 h0.8
  text "GHC" at 24.204,23.461 h0.8
  text "INH" at 111.17,22.356 h0.8
  text "GLC" at 28.238,20.248 h0.8
  text "GND" at 43.495,17.9 h0.8
  text "26" at 92.86,15.17 h0.8
  text "100" at 74.119,14.562 h0.8
  text "25" at 90.593,13.067 h0.8
  text "1" at 79.608,11.631 h0.8
  text "-" at 49.862,4.652 h3
  text "+" at 57.516,4.383 h3
  text "EPB PIN" at 52.732,1.873 h0.8
  text ".Layer_Name" at -14.045,-36.597 h0.8
Bottom Overlay:
  lines w0.013: 0,47.752 ccw(c27,47.752) 21.686,21.28 ; 0,47.752 ccw(c27,47.752) 21.686,21.28 ; 0,47.753 0,47.628 0,47.753 ; 0,47.752 0,56.202 0,47.752 ; 21.501,47.871 ccw(c26.999,47.751) 32.498,47.632 ; 21.501,47.871 cw(c26.999,47.751) 32.498,47.632 ; 21.501,47.871 ccw(c26.999,47.751) 32.498,47.632 ; 21.501,47.871 cw(c26.999,47.751) 32.498,47.632 ; 21.501,47.871 ccw(c26.999,47.751) 32.498,47.632 ; 21.501,47.871 cw(c26.999,47.751) 32.498,47.632 ; 21.501,47.871 ccw(c26.999,47.751) 32.498,47.632 ; 21.501,47.871 cw(c26.999,47.751) 32.498,47.632 ; 21.686,21.28 cw(c19.717,11.475) 28.628,16.015 ; 21.686,21.28 cw(c19.717,11.475) 28.628,16.015 ; 23,79.202 ccw(c23,56.202) 0,56.226 cw(c23,56.202) 23,79.202 ; 23,79.202 29.334,79.202 23,79.202 ; 28.628,16.015 28.996,15.291 ; 28.628,16.015 28.996,15.291 ; 28.996,15.291 33.252,6.937 ; 28.996,15.291 33.252,6.937 ; 33.253,6.938 cw(c20.408,0.395) 34.412,3.814 ; 33.253,6.938 cw(c20.408,0.395) 34.412,3.814 ; 34.412,3.814 ccw(c39.269,5) 39.269,0 ; 34.412,3.814 ccw(c39.269,5) 39.269,0 ; 39.269,0 98.671,0 ; 39.269,0 98.671,0 ; 43.558,82.687 cw(c29.333,109.974) 29.333,79.202 ccw(c29.333,109.974) 43.558,82.687 ; 43.558,82.687 cw(c45.87,78.254) 45.87,83.254 ; 43.558,82.687 cw(c45.87,78.254) 45.87,83.254 ; 45.87,83.254 57.109,83.254 ; 45.87,83.254 57.109,83.254 ; 57.109,83.254 cw(c57.109,82.754) 57.605,82.82 ; 57.109,83.254 cw(c57.109,82.754) 57.605,82.82 ; 57.605,82.82 ccw(c59.587,83.087) 59.587,81.087 ; 57.605,82.82 ccw(c59.587,83.087) 59.587,81.087 ; 59.587,81.087 ccw(c59.587,83.087) 61.569,82.82 ; 59.587,81.087 ccw(c59.587,83.087) 61.569,82.82 ; 61.569,82.82 cw(c62.064,82.754) 62.064,83.254 ; 61.569,82.82 cw(c62.064,82.754) 62.064,83.254 ; 62.064,83.254 117.835,83.254 ; 62.064,83.254 117.835,83.254 ; 98.671,0 ccw(c98.671,5) 101.668,0.997 ; 98.671,0 ccw(c98.671,5) 101.668,0.997 ; 101.668,0.997 104.606,3.197 ; 101.668,0.997 104.606,3.197 ; 104.606,3.197 cw(c195.432,-118.089) 115.806,10.827 ; 104.606,3.197 cw(c195.432,-118.089) 115.806,10.827 ; 115.806,10.827 ccw(c93,47.752) 128.731,23.117 ; 115.806,10.827 ccw(c93,47.752) 128.731,23.117 ; 117.835,83.254 ccw(c123.124,99.41) 123.124,82.41 ; 117.835,83.254 ccw(c123.124,99.41) 123.124,82.41 ; 123.124,82.41 156.533,82.41 ; 123.124,82.41 156.533,82.41 ; 128.731,23.117 cw(c142.315,13.752) 142.315,30.252 ; 128.731,23.117 cw(c142.315,13.752) 142.315,30.252 ; 142.315,30.252 156.533,30.252 ; 142.315,30.252 156.533,30.252 ; 156.533,30.252 ccw(c156.533,32.252) 158.533,32.252 ; 156.533,30.252 ccw(c156.533,32.252) 158.533,32.252 ; 156.533,82.41 cw(c156.533,80.41) 158.533,80.41 ; 156.533,82.41 cw(c156.533,80.41) 158.533,80.41 ; 158.533,32.252 158.533,80.41 ; 158.533,32.252 158.533,80.41
  text "3" at 156.649,64.328 h2
  text "2" at 156.625,57.761 h2
  text "1" at 156.439,50.844 h2
  text "11" at 143.278,49.92 h2
  text "7" at 151.362,47.328 h2
  text "10" at 142.786,43.423 h2
  text "6" at 151.595,43.252 h2
  text "5" at 151.618,37.663 h2
  text "9" at 143.6,37.622 h2
  text "8" at 143.683,33.656 h2
  text "4" at 151.432,33.634 h2
  text ".Layer_Name" at -14.045,-36.597 h0.8
Top Paste:
  text ".Layer_Name" at -14.045,-36.597 h0.8
Bottom Paste:
  text ".Layer_Name" at -14.045,-36.597 h0.8
Top Solder:
  text ".Layer_Name" at -14.045,-36.597 h0.8
  text ".Layer_Name" at -14.045,-36.597 h0.8
Bottom Solder:
  region: 36.807,64.58 36.027,63.8 31.03,63.8 30.141,64.689 30.141,69.87 30.717,70.445 33.63,70.445 36.807,67.268
  region: 16.924,69.481 17.4,69.957 21.368,69.957 22.874,68.451 22.874,63.406 22.339,62.871 17.436,62.871 16.924,63.383
  region: 105.569,82.46 105.796,82.687 110.9,82.687 112.248,81.34 112.248,77.868 109.791,75.412 106.136,75.412 105.569,75.979
  region: 94.423,82.577 94.589,82.744 100.124,82.744 101.573,81.294 101.573,73.371 99.861,71.658 96.368,71.658 94.423,73.604
  region: 38.066,11.232 38.563,11.729 43.247,11.729 44.003,10.974 44.003,6.471 43.364,5.831 38.695,5.831 38.066,6.46
  region: 27.839,77.719 28.82,78.7 35.021,78.7 35.656,78.065 35.656,73.408 35.121,72.873 28.436,72.873 27.839,73.47
  region: 8.002,65.753 7.607,66.148 7.607,71.932 7.997,72.322 13.567,72.322 14.22,71.67 14.22,67.158 12.814,65.753
  region: 3.066,52.164 2.723,52.507 2.723,57.858 3.049,58.185 7.743,58.185 8.395,57.533 8.395,52.864 7.695,52.164
  region: 9.677,51.708 10.232,52.262 14.604,52.262 16.193,50.673 16.193,45.979 15.541,45.327 10.188,45.327 9.677,45.838
  text ".Layer_Name" at -14.045,-36.597 h0.8
Drill Guide:
  text ".Layer_Name" at -14.045,-36.597 h0.8
M1 Board Outline:
  lines w0.254: 0,56.202 0,47.752 ccw(c27,47.752) 21.686,21.28 cw(c19.718,11.475) 28.628,16.015 33.253,6.938 cw(c20.408,0.395) 34.412,3.814 ccw(c39.269,5) 39.269,0 98.671,0 ccw(c98.671,5) 101.669,0.997 104.606,3.197 cw(c195.432,-118.089) 115.806,10.827 ccw(c93,47.752) 128.731,23.118 cw(c142.315,13.752) 142.315,30.252 156.533,30.252 ccw(c156.533,32.252) 158.533,32.252 158.533,80.41 ccw(c156.533,80.41) 156.533,82.41 123.125,82.41 cw(c123.125,99.41) 117.836,83.254 62.065,83.254 ccw(c62.065,82.754) 61.569,82.82 cw(c59.587,83.087) 59.587,81.087 cw(c59.587,83.087) 57.605,82.82 ccw(c57.109,82.754) 57.109,83.254 45.87,83.254 ccw(c45.87,78.254) 43.559,82.687 cw(c29.334,109.974) 29.334,79.202 23,79.202 ; 0,56.202 0,56.202 ; 0,56.202 0,56.226 ; 0,56.226 cw(c23,56.202) 23,79.202 ; 0,56.226 0,56.226 ; 23,79.202 23,79.202
  text ".Layer_Name" at -14.045,-36.597 h0.8
M2 Board Dimensions:
  text ".Layer_Name" at -14.045,-36.597 h0.8
M3 3D STEP Top:
  text ".Layer_Name" at -14.045,-36.597 h0.8
M4 3D STEP Bottom:
  text ".Layer_Name" at -14.045,-36.597 h0.8
M5 Assembly Top:
  lines w0.254: -36.118,-38.417 131.522,-38.417 ; -36.118,-33.253 131.573,-33.253 ; -36.118,-28.088 -36.118,-43.582 65.609,-43.582 131.573,-43.582 131.573,-28.088 -36.105,-28.088 -36.105,-43.582 3.913,-43.582 ; 26.493,-43.582 26.493,-28.088 ; 58.675,-33.253 58.675,-28.088 ; 80.011,-33.253 80.011,-28.088 ; 95.81,-43.747 95.81,-38.595
  text "COMPONENTS MARKED 'DNP' SHOULD NOT BE POPULATED." at 0.598,-22.881 h0.8
  text "ASSEMBLY VARIANT:" at 0.585,-25.815 h0.8
  text ".VariantName" at 26.9,-25.815 h0.8
  text "PCB VIEWED FROM TOP SIDE" at -34.505,-31.445 h0.8
  text "BOARD #:" at 28.398,-31.445 h0.8
  text ".PRJ_Number" at 42.254,-31.445 h0.8
  text "REV:" at 63.704,-31.445 h0.8
  text ".PCB_Rev" at 71.108,-31.445 h0.8
  text "SVN REV:" at 84.989,-31.445 h0.8
  text ".VersionControl_RevNumber" at 97.842,-31.445 h0.8
  text "TID #:" at 28.398,-36.61 h0.8
  text ".TID" at 42.254,-36.61 h0.8
  text "PLOT NAME =" at -34.505,-41.825 h0.8
  text ".plot_File_Name" at -14.045,-41.825 h0.8
  text "GENERATED    :" at 28.449,-41.825 h0.8
  text ".Print_Date" at 50.534,-41.825 h0.8
  text ".Print_Time" at 69.051,-41.825 h0.8
  text "TEXAS INSTRUMENTS" at 101.169,-41.825 h0.8
M6 Assembly Bottom:
  lines w0.254: -36.13,-33.265 131.56,-33.265 ; -36.08,-38.43 131.56,-38.43 ; -0.367,-43.76 -0.367,-38.608 ; 15.432,-33.265 15.432,-28.101 ; 36.768,-33.265 36.768,-28.101 ; 68.949,-43.595 68.949,-28.101 ; 91.53,-43.595 131.548,-43.595 131.548,-28.101 -36.13,-28.101 -36.13,-43.595 29.833,-43.595 131.56,-43.595 131.56,-28.101
  text "COMPONENTS MARKED 'DNP' SHOULD NOT BE POPULATED." at 126.29,-22.868 h0.8
  text ".VariantName" at 99.772,-25.815 h0.8
  text "ASSEMBLY VARIANT:" at 126.163,-25.815 h0.8
  text ".VersionControl_RevNumber" at -2.399,-31.458 h0.8
  text "SVN REV:" at 10.453,-31.458 h0.8
  text ".PCB_Rev" at 24.334,-31.458 h0.8
  text "REV:" at 31.738,-31.458 h0.8
  text ".PRJ_Number" at 53.189,-31.458 h0.8
  text "BOARD #:" at 67.044,-31.458 h0.8
  text "PCB VIEWED FROM BOTTOM SIDE" at 129.947,-31.458 h0.8
  text ".TID" at 53.189,-36.622 h0.8
  text "TID #:" at 67.044,-36.622 h0.8
  text "TEXAS INSTRUMENTS" at -5.727,-41.838 h0.8
  text ".Print_Time" at 26.392,-41.838 h0.8
  text ".Print_Date" at 44.908,-41.838 h0.8
  text "GENERATED    :" at 66.994,-41.838 h0.8
  text ".plot_File_Name" at 109.488,-41.838 h0.8
  text "PLOT NAME =" at 129.947,-41.838 h0.8
M9 Title Sheet:
  drawing of 57 lines, arcs and shapes, not listed
  text "1" at -9.909,189.336 h1.78
  text "2" at 53.481,189.336 h1.78
  text "3" at 116.71,189.336 h1.78
  text "4" at 180.379,189.336 h1.78
  text "5" at 243.854,189.336 h1.78
  text "6" at 307.481,189.336 h1.78
  text "A" at -39.28,160.304 h1.78
  text "A" at 336.64,160.304 h1.78
  text "B" at -39.28,99.852 h1.78
  text "B" at 336.64,99.852 h1.78
  text "C" at -39.28,39.527 h1.78
  text "C" at 336.64,39.527 h1.78
  text "PROJECT TITLE:" at 259.424,-7.742 h1.14
  text ".PRJ_Title" at 260.694,-11.129 h1.78
  text "DESIGNED FOR:" at 259.424,-15.388 h1.14
  text ".PRJ_Customer" at 260.694,-18.944 h1.78
  text "D" at -39.28,-20.671 h1.78
  text "D" at 336.64,-20.671 h1.78
  text "FILE NAME:" at 259.424,-23.008 h1.14
  text ".PCB_File_Name_No_Path" at 260.694,-26.056 h1.78
  text "Texas Instruments (TI) and/or its licensors do not warrant the accuracy or completeness of this specification" at 133.199,-30.167 h1.14
  text "ENGINEER:" at 259.424,-30.374 h1.14
  text "LAYOUT BY:" at 297.651,-30.374 h1.14
  text "or any information contained therein. TI and/or its licensors do not warrant that this design will meet" at 132.056,-33.028 h1.14
  text ".PRJ_Engineer" at 260.694,-34.311 h1.78
  text ".PCB_Layout" at 298.934,-34.311 h1.78
  text "the specifications, will be suitable for your application or fit for any particular purpose, or will operate in" at 132.056,-35.89 h1.14
  text ".Layer_Name" at -14.045,-36.597 h0.8
  text "ALTIUM DESIGNER VERSION:" at 297.651,-38.248 h1.14
  text "an implementation. TI and/or its licensors do not warrant that the design is production worthy. You should" at 132.056,-38.752 h1.14
  text "completely validate and test your design implementation to confirm the system functionality for your application." at 133.199,-41.613 h1.14
  text ".print_Scale" at 260.694,-41.634 h1.78
  text ".Application_BuildNumber" at 298.934,-41.634 h1.78
  text "1" at -9.909,-46.884 h1.78
  text "2" at 53.481,-46.884 h1.78
  text "3" at 116.71,-46.884 h1.78
  text "4" at 180.379,-46.884 h1.78
  text "5" at 243.854,-46.884 h1.78
  text "6" at 307.481,-46.884 h1.78
M10 Fab Notes:
  drawing of 189 lines, arcs and shapes, not listed
  text "DESIGN INFORMATION" at 285.802,146.656 h0.8
  text "MIN. TRACK WIDTH:" at 269.43,143.3 h0.8
  text "8" at 297.275,143.3 h0.8
  text "MIL" at 301.206,143.3 h0.8
  text "7.874" at 293.049,140.209 h0.8
  text "MIN. CLEARANCE:" at 269.43,140.147 h0.8
  text "MIL" at 301.206,140.147 h0.8
  text "MIN. VIA PAD SIZE:" at 269.43,136.994 h0.8
  text "24" at 296.513,136.994 h0.8
  text "MIL" at 301.206,136.994 h0.8
  text "0.05mm (2MIL)" at 287.083,133.695 h0.8
  text "MINIMUM ANNULAR RING" at 261.068,133.486 h0.8
  text "EXTERNAL" at 305.067,133.486 h0.8
  text "PER" at 266.148,130.689 h0.8
  text "IPC-D-275 CLASS 2 LEVEL C" at 271.736,130.689 h0.8
  text "MIL, HOLES" at 309.537,128.137 h0.8
  text "+/-" at 299.569,127.918 h0.8
  text "+/-" at 321.26,127.918 h0.8
  text "REGISTRATION TOLERANCES:" at 261.068,127.891 h0.8
  text "METAL" at 291.542,127.891 h0.8
  text "5" at 306.178,127.892 h0.8
  text "3" at 327.336,127.892 h0.8
  text "MIL" at 330.289,127.891 h0.8
  text "HOLE SIZE TOLERANCE (UNLESS OTHERWISE SPECIFIED):" at 261.068,125.394 h0.8
  text "+/-" at 321.26,125.321 h0.8
  text "3" at 327.336,125.294 h0.8
  text "MIL" at 330.289,125.294 h0.8
  text "MATERIAL:" at 259.169,121.798 h0.8
  text "FR-4 High Tg" at 284.225,118.533 h0.8
  text "X" at 280.556,118.331 h0.8
  text "FR-4" at 269.862,118.216 h0.8
  text "OTHER" at 307.657,118.216 h0.8
  text "62 MIL (1.6mm) +/-10%" at 277.993,114.583 h0.8
  text "X" at 274.942,114.521 h0.8
  text "THICKNESS:" at 261.068,114.374 h0.8
  text "OTHER" at 310.629,114.374 h0.8
  text "TOLERANCE:" at 261.068,110.861 h0.8
  text "X" at 282.613,110.861 h0.8
  text "ANSI IPC-6012 TYPE 3 CLASS 2" at 287.135,110.861 h0.8
  text "OTHER +/-" at 287.134,107.198 h0.8
  text "BOW & TWIST:" at 261.068,103.511 h0.8
  text "X" at 282.613,103.511 h0.8
  text "ANSI IPC-6012 TYPE 3 CLASS 2" at 287.135,103.511 h0.8
  text "OTHER +/-" at 287.134,99.785 h0.8
  text "DRILLING:" at 259.169,96.467 h0.8
  text "NC_DRILL FILES" at 303.898,93.795 h0.8
  text "REFERENCE:" at 261.068,93.695 h0.8
  text "X" at 277.762,93.693 h0.8
  text "AS SHOWN" at 282.283,93.695 h0.8
  text "X" at 300.647,93.695 h0.8
  text "OTHER" at 311.467,90.082 h0.8
  text "PTH COPPER THICKNESS:" at 261.06,89.992 h0.8
  text "X" at 289.996,89.992 h0.8
  text "20-30 um" at 293.247,89.992 h0.8
  text "BOARD FINISH:" at 259.169,86.243 h0.8
  text "SILKSCREEN:" at 263.112,83.446 h0.8
  text "X" at 287.439,83.446 h0.8
  text "TOP" at 290.411,83.446 h0.8
  text "X" at 300.393,83.446 h0.8
  text "BOTTOM" at 303.39,83.446 h0.8
  text "SILKSCREEN COLOR:" at 263.112,79.504 h0.8
  text "X" at 287.414,79.504 h0.8
  text "WHITE" at 290.411,79.504 h0.8
  text "OTHER" at 303.39,79.504 h0.8
  text "X" at 290.741,75.861 h0.8
  text "GREEN" at 293.738,75.861 h0.8
  text "OTHER" at 309.435,75.861 h0.8
  text "SOLDER RESIST COLOR:" at 263.112,75.686 h0.8
  text "MATTE" at 293.738,71.943 h0.8
  text "SEMI-GLOSS" at 309.424,71.926 h0.8
  text "IMMERSION GOLD (ENIG)" at 286.118,67.554 h0.8
  text "ENEPIG" at 320.092,67.371 h0.8
  text "SURFACE FINISH:" at 259.169,67.345 h0.8
  text "X" at 281.597,67.345 h0.8
  text "IMM. TIN/SILVER OR EQUIV" at 267.539,63.858 h0.8
  text "OTHER" at 303.898,63.758 h0.8
  text "ARRAY/PANEL:" at 259.169,59.811 h0.8
  text "CUT AND TRIM PER M1 BOARD OUTLINE" at 286.118,59.602 h0.8
  text "N.C. ROUTE" at 286.118,56.149 h0.8
  text "X" at 303.594,56.149 h0.8
  text "V. SCORE" at 308.115,56.149 h0.8
  text "CERTIFICATION:" at 259.169,52.869 h0.8
  text "MATERIALS AND WORKMANSHIP FOR ALL PCBS" at 277.584,52.869 h0.8
  text "TO MEET OR EXCEED THE REQUIREMENTS OF:" at 277.584,50.48 h0.8
  text "X" at 268.377,47.212 h0.8
  text "ANSI IPC-A-600F CLASS ->" at 271.628,47.212 h0.8
  text "X" at 313.487,47.212 h0.8
  text "2" at 316.281,47.212 h0.8
  text "1" at 308.28,47.174 h0.8
  text "3" at 325.272,47.174 h0.8
  text "X" at 289.001,43.461 h0.8
  text "RoHS" at 292.252,43.461 h0.8
  text "OTHER" at 308.62,43.461 h0.8
  text "PER ORDER" at 318.706,43.461 h0.8
  text "ALL BOARDS MUST MEET OR EXCEED UL94-V0 REQUIREMENTS." at 259.868,39.554 h0.8
  text "PCB MUST BEAR THE UL94V-0 UL REGISTERED MATERIAL ID NUMBER" at 259.868,36.606 h0.8
  text "ADDITIONAL REQUIREMENTS:" at 259.169,32.303 h0.8
  text "MICROSECTION:" at 261.068,29.582 h0.8
  text "YES" at 284.074,29.582 h0.8
  text "REQUIRED" at 305.956,25.916 h0.8
  text "BARE BOARD ELEC. TEST:" at 261.068,25.843 h0.8
  text "NONE" at 294.234,25.843 h0.8
  text "X" at 302.959,25.843 h0.8
  text "PER ORDER" at 320.992,25.843 h0.8
  text "XX MIL VIAS REQUIRE NON-CONDUCTIVE FILL AND PLANARIZE" at 265.339,20.637 h1.5
  text "XX MIL VIAS REQUIRE CONDUCTIVE FILL AND PLANARIZE" at 265.542,17.996 h0.8
  text "OUTER XX MIL TRACES REQUIRE 50 OHM SINGLE-ENDED IMPEDANCE" at 265.517,13.846 h1.47
  text "LAYER 2 & 3 (INNER LAYERS) XX MIL WIDE, XX MIL SPACE / TRACES REQUIRE 100 OHM DIFFERENTIAL IMPEDANCE" at 265.314,7.859 h0.8
  text ".Layer_Name" at -14.045,-36.597 h0.8
M11 Gerber Information:
  lines w0.254: -36.118,-38.417 131.522,-38.417 ; -36.118,-33.253 131.573,-33.253 ; -36.118,-28.088 -36.118,-43.582 65.609,-43.582 131.573,-43.582 131.573,-28.088 -36.105,-28.088 -36.105,-43.582 3.913,-43.582 ; 26.493,-43.582 26.493,-28.088 ; 58.675,-33.253 58.675,-28.088 ; 80.011,-33.253 80.011,-28.088 ; 95.81,-43.747 95.81,-38.595
  text "ALL ARTWORK VIEWED FROM TOP SIDE" at -34.505,-31.445 h0.8
  text "BOARD #:" at 28.398,-31.445 h0.8
  text ".PRJ_Number" at 42.254,-31.445 h0.8
  text "REV:" at 63.704,-31.445 h0.8
  text ".PCB_Rev" at 71.108,-31.445 h0.8
  text "SVN REV:" at 84.989,-31.445 h0.8
  text ".VersionControl_RevNumber" at 97.842,-31.445 h0.8
  text "LAYER NAME =" at -34.505,-36.597 h0.8
  text "TID #:" at 28.398,-36.61 h0.8
  text ".TID" at 42.254,-36.61 h0.8
  text "PLOT NAME =" at -34.505,-41.825 h0.8
  text ".plot_File_Name" at -14.045,-41.825 h0.8
  text "GENERATED    :" at 28.449,-41.825 h0.8
  text ".Print_Date" at 50.534,-41.825 h0.8
  text ".Print_Time" at 69.051,-41.825 h0.8
  text "TEXAS INSTRUMENTS" at 101.169,-41.825 h0.8
M12 Stackup:
  lines w0.381: 276.335,157.2 282.042,157.2 294.68,157.2 306.385,157.2 315.291,157.2 323.13,157.2 ; 276.335,158.8 282.042,158.8 294.68,158.8 306.385,158.8 315.291,158.8 323.13,158.8 ; 276.335,160.4 282.042,160.4 294.68,160.4 306.385,160.4 315.291,160.4 323.13,160.4 ; 276.335,162 282.042,162 294.68,162 306.385,162 315.291,162 323.13,162 ; 276.335,163.6 282.042,163.6 294.68,163.6 306.385,163.6 315.291,163.6 323.13,163.6 ; 276.335,165.2 282.042,165.2 294.68,165.2 306.385,165.2 315.291,165.2 323.13,165.2 ; 276.335,166.8 282.042,166.8 294.68,166.8 306.385,166.8 315.291,166.8 323.13,166.8 ; 276.335,168.4 282.042,168.4 294.68,168.4 306.385,168.4 315.291,168.4 323.13,168.4 ; 276.335,170 282.042,170 294.68,170 306.385,170 315.291,170 323.13,170 ; 276.335,171.6 282.042,171.6 294.68,171.6 306.385,171.6 315.291,171.6 323.13,171.6 ; 276.335,173.2 282.042,173.2 294.68,173.2 306.385,173.2 315.291,173.2 323.13,173.2 ; 276.335,174.8 282.042,174.8 294.68,174.8 306.385,174.8 315.291,174.8 323.13,174.8 ; 276.335,176.4 282.042,176.4 294.68,176.4 306.385,176.4 315.291,176.4 323.13,176.4 ; 276.335,178 282.042,178 294.68,178 306.385,178 315.291,178 323.13,178 ; 276.335,179.6 323.13,179.6 ; 282.042,181.2 282.042,155.6 ; 294.68,181.2 294.68,155.6 ; 306.385,181.2 306.385,155.6 ; 315.291,181.2 315.291,155.6 ; 282.042,155.6 276.335,155.6 276.335,181.2 323.13,181.2 323.13,155.6 315.291,155.6 ; 282.042,155.6 294.68,155.6 ; 294.68,155.6 306.385,155.6 ; 306.385,155.6 315.291,155.6
  text "Layer" at 277.389,180 h0.8
  text "Name" at 283.096,180 h0.8
  text "Material" at 295.734,180 h0.8
  text "Thickness" at 307.439,180 h0.8
  text "Constant" at 316.345,180 h0.8
  text "Top Overlay" at 283.096,178.4 h0.8
  text "Top Solder" at 283.096,176.8 h0.8
  text "Solder Resist" at 295.734,176.8 h0.8
  text "0.010mm" at 307.439,176.8 h0.8
  text "3.5" at 316.345,176.8 h0.8
  text "1" at 277.389,175.2 h0.8
  text "Top Layer" at 283.096,175.2 h0.8
  text "0.035mm" at 307.439,175.2 h0.8
  text "Dielectric 1" at 283.096,173.6 h0.8
  text "PP-006" at 295.734,173.6 h0.8
  text "0.290mm" at 307.439,173.6 h0.8
  text "4.1" at 316.345,173.6 h0.8
  text "2" at 277.389,172 h0.8
  text "GND" at 283.096,172 h0.8
  text "CF-004" at 295.734,172 h0.8
  text "0.018mm" at 307.439,172 h0.8
  text "Dielectric 3" at 283.096,170.4 h0.8
  text "PP-006" at 295.734,170.4 h0.8
  text "0.290mm" at 307.439,170.4 h0.8
  text "4.1" at 316.345,170.4 h0.8
  text "3" at 277.389,168.8 h0.8
  text "Power" at 283.096,168.8 h0.8
  text "CF-004" at 295.734,168.8 h0.8
  text "0.018mm" at 307.439,168.8 h0.8
  text "Dielectric1" at 283.096,167.2 h0.8
  text "FR-4 High Tg" at 295.734,167.2 h0.8
  text "0.290mm" at 307.439,167.2 h0.8
  text "4.8" at 316.345,167.2 h0.8
  text "4" at 277.389,165.6 h0.8
  text "Sig4" at 283.096,165.6 h0.8
  text "CF-004" at 295.734,165.6 h0.8
  text "0.018mm" at 307.439,165.6 h0.8
  text "Dielectric 4" at 283.096,164 h0.8
  text "PP-006" at 295.734,164 h0.8
  text "0.290mm" at 307.439,164 h0.8
  text "4.1" at 316.345,164 h0.8
  text "5" at 277.389,162.4 h0.8
  text "GND" at 283.096,162.4 h0.8
  text "CF-004" at 295.734,162.4 h0.8
  text "0.018mm" at 307.439,162.4 h0.8
  text "Dielectric 2" at 283.096,160.8 h0.8
  text "PP-006" at 295.734,160.8 h0.8
  text "0.290mm" at 307.439,160.8 h0.8
  text "4.1" at 316.345,160.8 h0.8
  text "6" at 277.389,159.2 h0.8
  text "Bottom Layer" at 283.096,159.2 h0.8
  text "0.035mm" at 307.439,159.2 h0.8
  text "Bottom Solder" at 283.096,157.6 h0.8
  text "Solder Resist" at 295.734,157.6 h0.8
  text "0.010mm" at 307.439,157.6 h0.8
  text "3.5" at 316.345,157.6 h0.8
  text "Bottom Overlay" at 283.096,156 h0.8
  text ".Layer_Name" at -14.045,-36.597 h0.8
M13 Component Bodies Top:
  text ".Layer_Name" at -14.045,-36.597 h0.8
M14 Component Bodies Bottom:
  text ".Layer_Name" at -14.045,-36.597 h0.8
M15 Courtyards Top:
  text ".Layer_Name" at -14.045,-36.597 h0.8
M16 Courtyards Bottom:
  text ".Layer_Name" at -14.045,-36.597 h0.8
Drill Drawing:
  text ".Layer_Name" at -14.045,-36.597 h0.8
M17 Embedded Cavity:
  text ".Layer_Name" at -14.045,-36.597 h0.8
M18 Embedded Assembly:
  text ".Layer_Name" at -14.045,-36.597 h0.8
M19 Embedded Keepout:
  text ".Layer_Name" at -14.045,-36.597 h0.8

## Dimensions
45.87,83.254 to 39.269,0 on M14 Component Bodies Bottom
158.533,32.252 to 0,47.752 on M14 Component Bodies Bottom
